VERSION 5.8 ;
BUSBITCHARS "[]" ;
DIVIDERCHAR "/" ;
UNITS
    DATABASE MICRONS 1000 ;
END UNITS

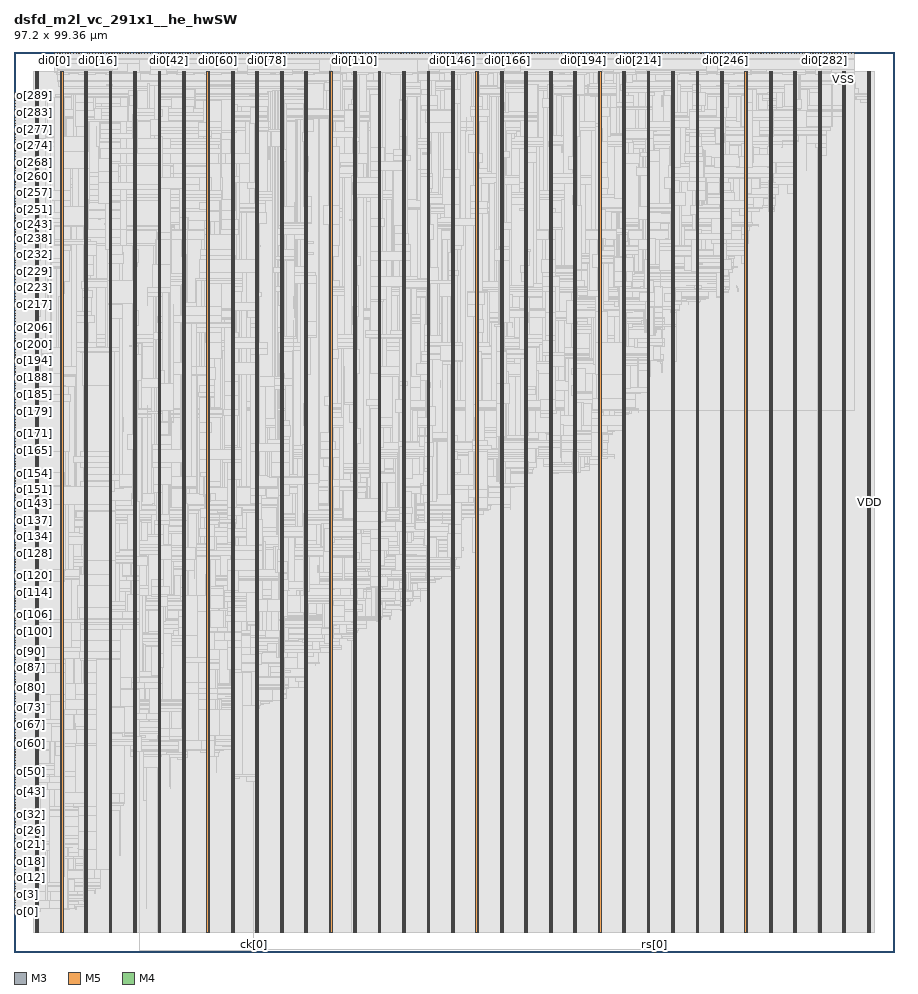
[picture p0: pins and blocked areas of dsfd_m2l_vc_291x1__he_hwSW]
MACRO dsfd_m2l_vc_291x1__he_hwSW
  FOREIGN dsfd_m2l_vc_291x1__he_hwSW 0 0 ;
  CLASS BLOCK ;
  SIZE 97.2 BY 99.36 ;
  PIN ck[0]
    DIRECTION INPUT ;
    USE SIGNAL ;
    PORT
      LAYER M3 ;
        RECT  26.46 0 26.478 0.144 ;
    END
    PORT
      LAYER M3 ;
        RECT  26.46 0.108 26.478 0.221 ;
    END
  END ck[0]
  PIN di0[0]
    DIRECTION INPUT ;
    USE SIGNAL ;
    PORT
      LAYER M3 ;
        RECT  4.464 99.216 4.482 99.36 ;
    END
  END di0[0]
  PIN di0[100]
    DIRECTION INPUT ;
    USE SIGNAL ;
    PORT
      LAYER M3 ;
        RECT  34.596 99.216 34.614 99.36 ;
    END
  END di0[100]
  PIN di0[101]
    DIRECTION INPUT ;
    USE SIGNAL ;
    PORT
      LAYER M5 ;
        RECT  34.896 99.168 34.92 99.36 ;
    END
  END di0[101]
  PIN di0[102]
    DIRECTION INPUT ;
    USE SIGNAL ;
    PORT
      LAYER M3 ;
        RECT  35.172 99.216 35.19 99.36 ;
    END
  END di0[102]
  PIN di0[103]
    DIRECTION INPUT ;
    USE SIGNAL ;
    PORT
      LAYER M5 ;
        RECT  35.472 99.168 35.496 99.36 ;
    END
  END di0[103]
  PIN di0[104]
    DIRECTION INPUT ;
    USE SIGNAL ;
    PORT
      LAYER M3 ;
        RECT  35.784 99.216 35.802 99.36 ;
    END
  END di0[104]
  PIN di0[105]
    DIRECTION INPUT ;
    USE SIGNAL ;
    PORT
      LAYER M5 ;
        RECT  36.096 99.168 36.12 99.36 ;
    END
  END di0[105]
  PIN di0[106]
    DIRECTION INPUT ;
    USE SIGNAL ;
    PORT
      LAYER M3 ;
        RECT  36.396 99.216 36.414 99.36 ;
    END
  END di0[106]
  PIN di0[107]
    DIRECTION INPUT ;
    USE SIGNAL ;
    PORT
      LAYER M5 ;
        RECT  36.672 99.168 36.696 99.36 ;
    END
  END di0[107]
  PIN di0[108]
    DIRECTION INPUT ;
    USE SIGNAL ;
    PORT
      LAYER M3 ;
        RECT  37.008 99.216 37.026 99.36 ;
    END
  END di0[108]
  PIN di0[109]
    DIRECTION INPUT ;
    USE SIGNAL ;
    PORT
      LAYER M5 ;
        RECT  37.296 99.168 37.32 99.36 ;
    END
  END di0[109]
  PIN di0[10]
    DIRECTION INPUT ;
    USE SIGNAL ;
    PORT
      LAYER M3 ;
        RECT  7.488 99.216 7.506 99.36 ;
    END
  END di0[10]
  PIN di0[110]
    DIRECTION INPUT ;
    USE SIGNAL ;
    PORT
      LAYER M3 ;
        RECT  37.584 99.216 37.602 99.36 ;
    END
  END di0[110]
  PIN di0[111]
    DIRECTION INPUT ;
    USE SIGNAL ;
    PORT
      LAYER M5 ;
        RECT  37.872 99.168 37.896 99.36 ;
    END
  END di0[111]
  PIN di0[112]
    DIRECTION INPUT ;
    USE SIGNAL ;
    PORT
      LAYER M3 ;
        RECT  38.196 99.216 38.214 99.36 ;
    END
  END di0[112]
  PIN di0[113]
    DIRECTION INPUT ;
    USE SIGNAL ;
    PORT
      LAYER M5 ;
        RECT  38.496 99.168 38.52 99.36 ;
    END
  END di0[113]
  PIN di0[114]
    DIRECTION INPUT ;
    USE SIGNAL ;
    PORT
      LAYER M3 ;
        RECT  38.808 99.216 38.826 99.36 ;
    END
  END di0[114]
  PIN di0[115]
    DIRECTION INPUT ;
    USE SIGNAL ;
    PORT
      LAYER M5 ;
        RECT  39.12 99.168 39.144 99.36 ;
    END
  END di0[115]
  PIN di0[116]
    DIRECTION INPUT ;
    USE SIGNAL ;
    PORT
      LAYER M3 ;
        RECT  39.42 99.216 39.438 99.36 ;
    END
  END di0[116]
  PIN di0[117]
    DIRECTION INPUT ;
    USE SIGNAL ;
    PORT
      LAYER M5 ;
        RECT  39.696 99.168 39.72 99.36 ;
    END
  END di0[117]
  PIN di0[118]
    DIRECTION INPUT ;
    USE SIGNAL ;
    PORT
      LAYER M3 ;
        RECT  39.996 99.216 40.014 99.36 ;
    END
  END di0[118]
  PIN di0[119]
    DIRECTION INPUT ;
    USE SIGNAL ;
    PORT
      LAYER M5 ;
        RECT  40.32 99.168 40.344 99.36 ;
    END
  END di0[119]
  PIN di0[11]
    DIRECTION INPUT ;
    USE SIGNAL ;
    PORT
      LAYER M5 ;
        RECT  7.776 99.168 7.8 99.36 ;
    END
  END di0[11]
  PIN di0[120]
    DIRECTION INPUT ;
    USE SIGNAL ;
    PORT
      LAYER M3 ;
        RECT  40.608 99.216 40.626 99.36 ;
    END
  END di0[120]
  PIN di0[121]
    DIRECTION INPUT ;
    USE SIGNAL ;
    PORT
      LAYER M5 ;
        RECT  40.896 99.168 40.92 99.36 ;
    END
  END di0[121]
  PIN di0[122]
    DIRECTION INPUT ;
    USE SIGNAL ;
    PORT
      LAYER M3 ;
        RECT  41.22 99.216 41.238 99.36 ;
    END
  END di0[122]
  PIN di0[123]
    DIRECTION INPUT ;
    USE SIGNAL ;
    PORT
      LAYER M5 ;
        RECT  41.52 99.168 41.544 99.36 ;
    END
  END di0[123]
  PIN di0[124]
    DIRECTION INPUT ;
    USE SIGNAL ;
    PORT
      LAYER M3 ;
        RECT  41.796 99.216 41.814 99.36 ;
    END
  END di0[124]
  PIN di0[125]
    DIRECTION INPUT ;
    USE SIGNAL ;
    PORT
      LAYER M5 ;
        RECT  42.096 99.168 42.12 99.36 ;
    END
  END di0[125]
  PIN di0[126]
    DIRECTION INPUT ;
    USE SIGNAL ;
    PORT
      LAYER M3 ;
        RECT  42.408 99.216 42.426 99.36 ;
    END
  END di0[126]
  PIN di0[127]
    DIRECTION INPUT ;
    USE SIGNAL ;
    PORT
      LAYER M5 ;
        RECT  42.72 99.168 42.744 99.36 ;
    END
  END di0[127]
  PIN di0[128]
    DIRECTION INPUT ;
    USE SIGNAL ;
    PORT
      LAYER M3 ;
        RECT  43.02 99.216 43.038 99.36 ;
    END
  END di0[128]
  PIN di0[129]
    DIRECTION INPUT ;
    USE SIGNAL ;
    PORT
      LAYER M5 ;
        RECT  43.296 99.168 43.32 99.36 ;
    END
  END di0[129]
  PIN di0[12]
    DIRECTION INPUT ;
    USE SIGNAL ;
    PORT
      LAYER M3 ;
        RECT  8.064 99.216 8.082 99.36 ;
    END
  END di0[12]
  PIN di0[130]
    DIRECTION INPUT ;
    USE SIGNAL ;
    PORT
      LAYER M3 ;
        RECT  43.632 99.216 43.65 99.36 ;
    END
  END di0[130]
  PIN di0[131]
    DIRECTION INPUT ;
    USE SIGNAL ;
    PORT
      LAYER M5 ;
        RECT  43.92 99.168 43.944 99.36 ;
    END
  END di0[131]
  PIN di0[132]
    DIRECTION INPUT ;
    USE SIGNAL ;
    PORT
      LAYER M3 ;
        RECT  44.208 99.216 44.226 99.36 ;
    END
  END di0[132]
  PIN di0[133]
    DIRECTION INPUT ;
    USE SIGNAL ;
    PORT
      LAYER M5 ;
        RECT  44.544 99.168 44.568 99.36 ;
    END
  END di0[133]
  PIN di0[134]
    DIRECTION INPUT ;
    USE SIGNAL ;
    PORT
      LAYER M3 ;
        RECT  44.82 99.216 44.838 99.36 ;
    END
  END di0[134]
  PIN di0[135]
    DIRECTION INPUT ;
    USE SIGNAL ;
    PORT
      LAYER M5 ;
        RECT  45.12 99.168 45.144 99.36 ;
    END
  END di0[135]
  PIN di0[136]
    DIRECTION INPUT ;
    USE SIGNAL ;
    PORT
      LAYER M3 ;
        RECT  45.432 99.216 45.45 99.36 ;
    END
  END di0[136]
  PIN di0[137]
    DIRECTION INPUT ;
    USE SIGNAL ;
    PORT
      LAYER M5 ;
        RECT  45.744 99.168 45.768 99.36 ;
    END
  END di0[137]
  PIN di0[138]
    DIRECTION INPUT ;
    USE SIGNAL ;
    PORT
      LAYER M3 ;
        RECT  46.044 99.216 46.062 99.36 ;
    END
  END di0[138]
  PIN di0[139]
    DIRECTION INPUT ;
    USE SIGNAL ;
    PORT
      LAYER M5 ;
        RECT  46.32 99.168 46.344 99.36 ;
    END
  END di0[139]
  PIN di0[13]
    DIRECTION INPUT ;
    USE SIGNAL ;
    PORT
      LAYER M5 ;
        RECT  8.352 99.168 8.376 99.36 ;
    END
  END di0[13]
  PIN di0[140]
    DIRECTION INPUT ;
    USE SIGNAL ;
    PORT
      LAYER M3 ;
        RECT  46.62 99.216 46.638 99.36 ;
    END
  END di0[140]
  PIN di0[141]
    DIRECTION INPUT ;
    USE SIGNAL ;
    PORT
      LAYER M5 ;
        RECT  46.944 99.168 46.968 99.36 ;
    END
  END di0[141]
  PIN di0[142]
    DIRECTION INPUT ;
    USE SIGNAL ;
    PORT
      LAYER M3 ;
        RECT  47.232 99.216 47.25 99.36 ;
    END
  END di0[142]
  PIN di0[143]
    DIRECTION INPUT ;
    USE SIGNAL ;
    PORT
      LAYER M5 ;
        RECT  47.52 99.168 47.544 99.36 ;
    END
  END di0[143]
  PIN di0[144]
    DIRECTION INPUT ;
    USE SIGNAL ;
    PORT
      LAYER M3 ;
        RECT  47.844 99.216 47.862 99.36 ;
    END
  END di0[144]
  PIN di0[145]
    DIRECTION INPUT ;
    USE SIGNAL ;
    PORT
      LAYER M5 ;
        RECT  48.144 99.168 48.168 99.36 ;
    END
  END di0[145]
  PIN di0[146]
    DIRECTION INPUT ;
    USE SIGNAL ;
    PORT
      LAYER M3 ;
        RECT  48.456 99.216 48.474 99.36 ;
    END
  END di0[146]
  PIN di0[147]
    DIRECTION INPUT ;
    USE SIGNAL ;
    PORT
      LAYER M5 ;
        RECT  48.72 99.168 48.744 99.36 ;
    END
  END di0[147]
  PIN di0[148]
    DIRECTION INPUT ;
    USE SIGNAL ;
    PORT
      LAYER M3 ;
        RECT  49.032 99.216 49.05 99.36 ;
    END
  END di0[148]
  PIN di0[149]
    DIRECTION INPUT ;
    USE SIGNAL ;
    PORT
      LAYER M5 ;
        RECT  49.344 99.168 49.368 99.36 ;
    END
  END di0[149]
  PIN di0[14]
    DIRECTION INPUT ;
    USE SIGNAL ;
    PORT
      LAYER M3 ;
        RECT  8.676 99.216 8.694 99.36 ;
    END
  END di0[14]
  PIN di0[150]
    DIRECTION INPUT ;
    USE SIGNAL ;
    PORT
      LAYER M3 ;
        RECT  49.644 99.216 49.662 99.36 ;
    END
  END di0[150]
  PIN di0[151]
    DIRECTION INPUT ;
    USE SIGNAL ;
    PORT
      LAYER M5 ;
        RECT  49.92 99.168 49.944 99.36 ;
    END
  END di0[151]
  PIN di0[152]
    DIRECTION INPUT ;
    USE SIGNAL ;
    PORT
      LAYER M3 ;
        RECT  50.256 99.216 50.274 99.36 ;
    END
  END di0[152]
  PIN di0[153]
    DIRECTION INPUT ;
    USE SIGNAL ;
    PORT
      LAYER M5 ;
        RECT  50.544 99.168 50.568 99.36 ;
    END
  END di0[153]
  PIN di0[154]
    DIRECTION INPUT ;
    USE SIGNAL ;
    PORT
      LAYER M3 ;
        RECT  50.868 99.216 50.886 99.36 ;
    END
  END di0[154]
  PIN di0[155]
    DIRECTION INPUT ;
    USE SIGNAL ;
    PORT
      LAYER M5 ;
        RECT  51.168 99.168 51.192 99.36 ;
    END
  END di0[155]
  PIN di0[156]
    DIRECTION INPUT ;
    USE SIGNAL ;
    PORT
      LAYER M3 ;
        RECT  51.444 99.216 51.462 99.36 ;
    END
  END di0[156]
  PIN di0[157]
    DIRECTION INPUT ;
    USE SIGNAL ;
    PORT
      LAYER M5 ;
        RECT  51.744 99.168 51.768 99.36 ;
    END
  END di0[157]
  PIN di0[158]
    DIRECTION INPUT ;
    USE SIGNAL ;
    PORT
      LAYER M3 ;
        RECT  52.056 99.216 52.074 99.36 ;
    END
  END di0[158]
  PIN di0[159]
    DIRECTION INPUT ;
    USE SIGNAL ;
    PORT
      LAYER M5 ;
        RECT  52.368 99.168 52.392 99.36 ;
    END
  END di0[159]
  PIN di0[15]
    DIRECTION INPUT ;
    USE SIGNAL ;
    PORT
      LAYER M5 ;
        RECT  8.976 99.168 9 99.36 ;
    END
  END di0[15]
  PIN di0[160]
    DIRECTION INPUT ;
    USE SIGNAL ;
    PORT
      LAYER M3 ;
        RECT  52.668 99.216 52.686 99.36 ;
    END
  END di0[160]
  PIN di0[161]
    DIRECTION INPUT ;
    USE SIGNAL ;
    PORT
      LAYER M5 ;
        RECT  52.944 99.168 52.968 99.36 ;
    END
  END di0[161]
  PIN di0[162]
    DIRECTION INPUT ;
    USE SIGNAL ;
    PORT
      LAYER M3 ;
        RECT  53.244 99.216 53.262 99.36 ;
    END
  END di0[162]
  PIN di0[163]
    DIRECTION INPUT ;
    USE SIGNAL ;
    PORT
      LAYER M5 ;
        RECT  53.568 99.168 53.592 99.36 ;
    END
  END di0[163]
  PIN di0[164]
    DIRECTION INPUT ;
    USE SIGNAL ;
    PORT
      LAYER M3 ;
        RECT  53.856 99.216 53.874 99.36 ;
    END
  END di0[164]
  PIN di0[165]
    DIRECTION INPUT ;
    USE SIGNAL ;
    PORT
      LAYER M5 ;
        RECT  54.144 99.168 54.168 99.36 ;
    END
  END di0[165]
  PIN di0[166]
    DIRECTION INPUT ;
    USE SIGNAL ;
    PORT
      LAYER M3 ;
        RECT  54.468 99.216 54.486 99.36 ;
    END
  END di0[166]
  PIN di0[167]
    DIRECTION INPUT ;
    USE SIGNAL ;
    PORT
      LAYER M5 ;
        RECT  54.768 99.168 54.792 99.36 ;
    END
  END di0[167]
  PIN di0[168]
    DIRECTION INPUT ;
    USE SIGNAL ;
    PORT
      LAYER M3 ;
        RECT  55.08 99.216 55.098 99.36 ;
    END
  END di0[168]
  PIN di0[169]
    DIRECTION INPUT ;
    USE SIGNAL ;
    PORT
      LAYER M5 ;
        RECT  55.344 99.168 55.368 99.36 ;
    END
  END di0[169]
  PIN di0[16]
    DIRECTION INPUT ;
    USE SIGNAL ;
    PORT
      LAYER M3 ;
        RECT  9.288 99.216 9.306 99.36 ;
    END
  END di0[16]
  PIN di0[170]
    DIRECTION INPUT ;
    USE SIGNAL ;
    PORT
      LAYER M3 ;
        RECT  55.656 99.216 55.674 99.36 ;
    END
  END di0[170]
  PIN di0[171]
    DIRECTION INPUT ;
    USE SIGNAL ;
    PORT
      LAYER M5 ;
        RECT  55.968 99.168 55.992 99.36 ;
    END
  END di0[171]
  PIN di0[172]
    DIRECTION INPUT ;
    USE SIGNAL ;
    PORT
      LAYER M3 ;
        RECT  56.268 99.216 56.286 99.36 ;
    END
  END di0[172]
  PIN di0[173]
    DIRECTION INPUT ;
    USE SIGNAL ;
    PORT
      LAYER M5 ;
        RECT  56.592 99.168 56.616 99.36 ;
    END
  END di0[173]
  PIN di0[174]
    DIRECTION INPUT ;
    USE SIGNAL ;
    PORT
      LAYER M3 ;
        RECT  56.88 99.216 56.898 99.36 ;
    END
  END di0[174]
  PIN di0[175]
    DIRECTION INPUT ;
    USE SIGNAL ;
    PORT
      LAYER M5 ;
        RECT  57.168 99.168 57.192 99.36 ;
    END
  END di0[175]
  PIN di0[176]
    DIRECTION INPUT ;
    USE SIGNAL ;
    PORT
      LAYER M3 ;
        RECT  57.492 99.216 57.51 99.36 ;
    END
  END di0[176]
  PIN di0[177]
    DIRECTION INPUT ;
    USE SIGNAL ;
    PORT
      LAYER M5 ;
        RECT  57.792 99.168 57.816 99.36 ;
    END
  END di0[177]
  PIN di0[178]
    DIRECTION INPUT ;
    USE SIGNAL ;
    PORT
      LAYER M3 ;
        RECT  58.068 99.216 58.086 99.36 ;
    END
  END di0[178]
  PIN di0[179]
    DIRECTION INPUT ;
    USE SIGNAL ;
    PORT
      LAYER M5 ;
        RECT  58.368 99.168 58.392 99.36 ;
    END
  END di0[179]
  PIN di0[17]
    DIRECTION INPUT ;
    USE SIGNAL ;
    PORT
      LAYER M5 ;
        RECT  9.6 99.168 9.624 99.36 ;
    END
  END di0[17]
  PIN di0[180]
    DIRECTION INPUT ;
    USE SIGNAL ;
    PORT
      LAYER M3 ;
        RECT  58.68 99.216 58.698 99.36 ;
    END
  END di0[180]
  PIN di0[181]
    DIRECTION INPUT ;
    USE SIGNAL ;
    PORT
      LAYER M5 ;
        RECT  58.992 99.168 59.016 99.36 ;
    END
  END di0[181]
  PIN di0[182]
    DIRECTION INPUT ;
    USE SIGNAL ;
    PORT
      LAYER M3 ;
        RECT  59.292 99.216 59.31 99.36 ;
    END
  END di0[182]
  PIN di0[183]
    DIRECTION INPUT ;
    USE SIGNAL ;
    PORT
      LAYER M5 ;
        RECT  59.568 99.168 59.592 99.36 ;
    END
  END di0[183]
  PIN di0[184]
    DIRECTION INPUT ;
    USE SIGNAL ;
    PORT
      LAYER M3 ;
        RECT  59.904 99.216 59.922 99.36 ;
    END
  END di0[184]
  PIN di0[185]
    DIRECTION INPUT ;
    USE SIGNAL ;
    PORT
      LAYER M5 ;
        RECT  60.192 99.168 60.216 99.36 ;
    END
  END di0[185]
  PIN di0[186]
    DIRECTION INPUT ;
    USE SIGNAL ;
    PORT
      LAYER M3 ;
        RECT  60.48 99.216 60.498 99.36 ;
    END
  END di0[186]
  PIN di0[187]
    DIRECTION INPUT ;
    USE SIGNAL ;
    PORT
      LAYER M5 ;
        RECT  60.768 99.168 60.792 99.36 ;
    END
  END di0[187]
  PIN di0[188]
    DIRECTION INPUT ;
    USE SIGNAL ;
    PORT
      LAYER M3 ;
        RECT  61.092 99.216 61.11 99.36 ;
    END
  END di0[188]
  PIN di0[189]
    DIRECTION INPUT ;
    USE SIGNAL ;
    PORT
      LAYER M5 ;
        RECT  61.392 99.168 61.416 99.36 ;
    END
  END di0[189]
  PIN di0[18]
    DIRECTION INPUT ;
    USE SIGNAL ;
    PORT
      LAYER M3 ;
        RECT  9.9 99.216 9.918 99.36 ;
    END
  END di0[18]
  PIN di0[190]
    DIRECTION INPUT ;
    USE SIGNAL ;
    PORT
      LAYER M3 ;
        RECT  61.704 99.216 61.722 99.36 ;
    END
  END di0[190]
  PIN di0[191]
    DIRECTION INPUT ;
    USE SIGNAL ;
    PORT
      LAYER M5 ;
        RECT  62.016 99.168 62.04 99.36 ;
    END
  END di0[191]
  PIN di0[192]
    DIRECTION INPUT ;
    USE SIGNAL ;
    PORT
      LAYER M3 ;
        RECT  62.28 99.216 62.298 99.36 ;
    END
  END di0[192]
  PIN di0[193]
    DIRECTION INPUT ;
    USE SIGNAL ;
    PORT
      LAYER M5 ;
        RECT  62.592 99.168 62.616 99.36 ;
    END
  END di0[193]
  PIN di0[194]
    DIRECTION INPUT ;
    USE SIGNAL ;
    PORT
      LAYER M3 ;
        RECT  62.892 99.216 62.91 99.36 ;
    END
  END di0[194]
  PIN di0[195]
    DIRECTION INPUT ;
    USE SIGNAL ;
    PORT
      LAYER M5 ;
        RECT  63.216 99.168 63.24 99.36 ;
    END
  END di0[195]
  PIN di0[196]
    DIRECTION INPUT ;
    USE SIGNAL ;
    PORT
      LAYER M3 ;
        RECT  63.504 99.216 63.522 99.36 ;
    END
  END di0[196]
  PIN di0[197]
    DIRECTION INPUT ;
    USE SIGNAL ;
    PORT
      LAYER M5 ;
        RECT  63.792 99.168 63.816 99.36 ;
    END
  END di0[197]
  PIN di0[198]
    DIRECTION INPUT ;
    USE SIGNAL ;
    PORT
      LAYER M3 ;
        RECT  64.116 99.216 64.134 99.36 ;
    END
  END di0[198]
  PIN di0[199]
    DIRECTION INPUT ;
    USE SIGNAL ;
    PORT
      LAYER M5 ;
        RECT  64.416 99.168 64.44 99.36 ;
    END
  END di0[199]
  PIN di0[19]
    DIRECTION INPUT ;
    USE SIGNAL ;
    PORT
      LAYER M5 ;
        RECT  10.176 99.168 10.2 99.36 ;
    END
  END di0[19]
  PIN di0[1]
    DIRECTION INPUT ;
    USE SIGNAL ;
    PORT
      LAYER M5 ;
        RECT  4.752 99.168 4.776 99.36 ;
    END
  END di0[1]
  PIN di0[200]
    DIRECTION INPUT ;
    USE SIGNAL ;
    PORT
      LAYER M3 ;
        RECT  64.692 99.216 64.71 99.36 ;
    END
  END di0[200]
  PIN di0[201]
    DIRECTION INPUT ;
    USE SIGNAL ;
    PORT
      LAYER M5 ;
        RECT  64.992 99.168 65.016 99.36 ;
    END
  END di0[201]
  PIN di0[202]
    DIRECTION INPUT ;
    USE SIGNAL ;
    PORT
      LAYER M3 ;
        RECT  65.304 99.216 65.322 99.36 ;
    END
  END di0[202]
  PIN di0[203]
    DIRECTION INPUT ;
    USE SIGNAL ;
    PORT
      LAYER M5 ;
        RECT  65.616 99.168 65.64 99.36 ;
    END
  END di0[203]
  PIN di0[204]
    DIRECTION INPUT ;
    USE SIGNAL ;
    PORT
      LAYER M3 ;
        RECT  65.916 99.216 65.934 99.36 ;
    END
  END di0[204]
  PIN di0[205]
    DIRECTION INPUT ;
    USE SIGNAL ;
    PORT
      LAYER M5 ;
        RECT  66.192 99.168 66.216 99.36 ;
    END
  END di0[205]
  PIN di0[206]
    DIRECTION INPUT ;
    USE SIGNAL ;
    PORT
      LAYER M3 ;
        RECT  66.528 99.216 66.546 99.36 ;
    END
  END di0[206]
  PIN di0[207]
    DIRECTION INPUT ;
    USE SIGNAL ;
    PORT
      LAYER M5 ;
        RECT  66.816 99.168 66.84 99.36 ;
    END
  END di0[207]
  PIN di0[208]
    DIRECTION INPUT ;
    USE SIGNAL ;
    PORT
      LAYER M3 ;
        RECT  67.104 99.216 67.122 99.36 ;
    END
  END di0[208]
  PIN di0[209]
    DIRECTION INPUT ;
    USE SIGNAL ;
    PORT
      LAYER M5 ;
        RECT  67.392 99.168 67.416 99.36 ;
    END
  END di0[209]
  PIN di0[20]
    DIRECTION INPUT ;
    USE SIGNAL ;
    PORT
      LAYER M3 ;
        RECT  10.476 99.216 10.494 99.36 ;
    END
  END di0[20]
  PIN di0[210]
    DIRECTION INPUT ;
    USE SIGNAL ;
    PORT
      LAYER M3 ;
        RECT  67.716 99.216 67.734 99.36 ;
    END
  END di0[210]
  PIN di0[211]
    DIRECTION INPUT ;
    USE SIGNAL ;
    PORT
      LAYER M5 ;
        RECT  68.016 99.168 68.04 99.36 ;
    END
  END di0[211]
  PIN di0[212]
    DIRECTION INPUT ;
    USE SIGNAL ;
    PORT
      LAYER M3 ;
        RECT  68.328 99.216 68.346 99.36 ;
    END
  END di0[212]
  PIN di0[213]
    DIRECTION INPUT ;
    USE SIGNAL ;
    PORT
      LAYER M5 ;
        RECT  68.64 99.168 68.664 99.36 ;
    END
  END di0[213]
  PIN di0[214]
    DIRECTION INPUT ;
    USE SIGNAL ;
    PORT
      LAYER M3 ;
        RECT  68.94 99.216 68.958 99.36 ;
    END
  END di0[214]
  PIN di0[215]
    DIRECTION INPUT ;
    USE SIGNAL ;
    PORT
      LAYER M5 ;
        RECT  69.216 99.168 69.24 99.36 ;
    END
  END di0[215]
  PIN di0[216]
    DIRECTION INPUT ;
    USE SIGNAL ;
    PORT
      LAYER M3 ;
        RECT  69.516 99.216 69.534 99.36 ;
    END
  END di0[216]
  PIN di0[217]
    DIRECTION INPUT ;
    USE SIGNAL ;
    PORT
      LAYER M5 ;
        RECT  69.84 99.168 69.864 99.36 ;
    END
  END di0[217]
  PIN di0[218]
    DIRECTION INPUT ;
    USE SIGNAL ;
    PORT
      LAYER M3 ;
        RECT  70.128 99.216 70.146 99.36 ;
    END
  END di0[218]
  PIN di0[219]
    DIRECTION INPUT ;
    USE SIGNAL ;
    PORT
      LAYER M5 ;
        RECT  70.416 99.168 70.44 99.36 ;
    END
  END di0[219]
  PIN di0[21]
    DIRECTION INPUT ;
    USE SIGNAL ;
    PORT
      LAYER M5 ;
        RECT  10.8 99.168 10.824 99.36 ;
    END
  END di0[21]
  PIN di0[220]
    DIRECTION INPUT ;
    USE SIGNAL ;
    PORT
      LAYER M3 ;
        RECT  70.74 99.216 70.758 99.36 ;
    END
  END di0[220]
  PIN di0[221]
    DIRECTION INPUT ;
    USE SIGNAL ;
    PORT
      LAYER M5 ;
        RECT  71.04 99.168 71.064 99.36 ;
    END
  END di0[221]
  PIN di0[222]
    DIRECTION INPUT ;
    USE SIGNAL ;
    PORT
      LAYER M3 ;
        RECT  71.316 99.216 71.334 99.36 ;
    END
  END di0[222]
  PIN di0[223]
    DIRECTION INPUT ;
    USE SIGNAL ;
    PORT
      LAYER M5 ;
        RECT  71.616 99.168 71.64 99.36 ;
    END
  END di0[223]
  PIN di0[224]
    DIRECTION INPUT ;
    USE SIGNAL ;
    PORT
      LAYER M3 ;
        RECT  71.928 99.216 71.946 99.36 ;
    END
  END di0[224]
  PIN di0[225]
    DIRECTION INPUT ;
    USE SIGNAL ;
    PORT
      LAYER M5 ;
        RECT  72.24 99.168 72.264 99.36 ;
    END
  END di0[225]
  PIN di0[226]
    DIRECTION INPUT ;
    USE SIGNAL ;
    PORT
      LAYER M3 ;
        RECT  72.54 99.216 72.558 99.36 ;
    END
  END di0[226]
  PIN di0[227]
    DIRECTION INPUT ;
    USE SIGNAL ;
    PORT
      LAYER M5 ;
        RECT  72.816 99.168 72.84 99.36 ;
    END
  END di0[227]
  PIN di0[228]
    DIRECTION INPUT ;
    USE SIGNAL ;
    PORT
      LAYER M3 ;
        RECT  73.152 99.216 73.17 99.36 ;
    END
  END di0[228]
  PIN di0[229]
    DIRECTION INPUT ;
    USE SIGNAL ;
    PORT
      LAYER M5 ;
        RECT  73.44 99.168 73.464 99.36 ;
    END
  END di0[229]
  PIN di0[22]
    DIRECTION INPUT ;
    USE SIGNAL ;
    PORT
      LAYER M3 ;
        RECT  11.088 99.216 11.106 99.36 ;
    END
  END di0[22]
  PIN di0[230]
    DIRECTION INPUT ;
    USE SIGNAL ;
    PORT
      LAYER M3 ;
        RECT  73.728 99.216 73.746 99.36 ;
    END
  END di0[230]
  PIN di0[231]
    DIRECTION INPUT ;
    USE SIGNAL ;
    PORT
      LAYER M5 ;
        RECT  74.064 99.168 74.088 99.36 ;
    END
  END di0[231]
  PIN di0[232]
    DIRECTION INPUT ;
    USE SIGNAL ;
    PORT
      LAYER M3 ;
        RECT  74.34 99.216 74.358 99.36 ;
    END
  END di0[232]
  PIN di0[233]
    DIRECTION INPUT ;
    USE SIGNAL ;
    PORT
      LAYER M5 ;
        RECT  74.64 99.168 74.664 99.36 ;
    END
  END di0[233]
  PIN di0[234]
    DIRECTION INPUT ;
    USE SIGNAL ;
    PORT
      LAYER M3 ;
        RECT  74.952 99.216 74.97 99.36 ;
    END
  END di0[234]
  PIN di0[235]
    DIRECTION INPUT ;
    USE SIGNAL ;
    PORT
      LAYER M5 ;
        RECT  75.264 99.168 75.288 99.36 ;
    END
  END di0[235]
  PIN di0[236]
    DIRECTION INPUT ;
    USE SIGNAL ;
    PORT
      LAYER M3 ;
        RECT  75.564 99.216 75.582 99.36 ;
    END
  END di0[236]
  PIN di0[237]
    DIRECTION INPUT ;
    USE SIGNAL ;
    PORT
      LAYER M5 ;
        RECT  75.84 99.168 75.864 99.36 ;
    END
  END di0[237]
  PIN di0[238]
    DIRECTION INPUT ;
    USE SIGNAL ;
    PORT
      LAYER M3 ;
        RECT  76.14 99.216 76.158 99.36 ;
    END
  END di0[238]
  PIN di0[239]
    DIRECTION INPUT ;
    USE SIGNAL ;
    PORT
      LAYER M5 ;
        RECT  76.464 99.168 76.488 99.36 ;
    END
  END di0[239]
  PIN di0[23]
    DIRECTION INPUT ;
    USE SIGNAL ;
    PORT
      LAYER M5 ;
        RECT  11.376 99.168 11.4 99.36 ;
    END
  END di0[23]
  PIN di0[240]
    DIRECTION INPUT ;
    USE SIGNAL ;
    PORT
      LAYER M3 ;
        RECT  76.752 99.216 76.77 99.36 ;
    END
  END di0[240]
  PIN di0[241]
    DIRECTION INPUT ;
    USE SIGNAL ;
    PORT
      LAYER M5 ;
        RECT  77.04 99.168 77.064 99.36 ;
    END
  END di0[241]
  PIN di0[242]
    DIRECTION INPUT ;
    USE SIGNAL ;
    PORT
      LAYER M3 ;
        RECT  77.364 99.216 77.382 99.36 ;
    END
  END di0[242]
  PIN di0[243]
    DIRECTION INPUT ;
    USE SIGNAL ;
    PORT
      LAYER M5 ;
        RECT  77.664 99.168 77.688 99.36 ;
    END
  END di0[243]
  PIN di0[244]
    DIRECTION INPUT ;
    USE SIGNAL ;
    PORT
      LAYER M3 ;
        RECT  77.976 99.216 77.994 99.36 ;
    END
  END di0[244]
  PIN di0[245]
    DIRECTION INPUT ;
    USE SIGNAL ;
    PORT
      LAYER M5 ;
        RECT  78.24 99.168 78.264 99.36 ;
    END
  END di0[245]
  PIN di0[246]
    DIRECTION INPUT ;
    USE SIGNAL ;
    PORT
      LAYER M3 ;
        RECT  78.552 99.216 78.57 99.36 ;
    END
  END di0[246]
  PIN di0[247]
    DIRECTION INPUT ;
    USE SIGNAL ;
    PORT
      LAYER M5 ;
        RECT  78.864 99.168 78.888 99.36 ;
    END
  END di0[247]
  PIN di0[248]
    DIRECTION INPUT ;
    USE SIGNAL ;
    PORT
      LAYER M3 ;
        RECT  79.164 99.216 79.182 99.36 ;
    END
  END di0[248]
  PIN di0[249]
    DIRECTION INPUT ;
    USE SIGNAL ;
    PORT
      LAYER M5 ;
        RECT  79.44 99.168 79.464 99.36 ;
    END
  END di0[249]
  PIN di0[24]
    DIRECTION INPUT ;
    USE SIGNAL ;
    PORT
      LAYER M3 ;
        RECT  11.7 99.216 11.718 99.36 ;
    END
  END di0[24]
  PIN di0[250]
    DIRECTION INPUT ;
    USE SIGNAL ;
    PORT
      LAYER M3 ;
        RECT  79.776 99.216 79.794 99.36 ;
    END
  END di0[250]
  PIN di0[251]
    DIRECTION INPUT ;
    USE SIGNAL ;
    PORT
      LAYER M5 ;
        RECT  80.064 99.168 80.088 99.36 ;
    END
  END di0[251]
  PIN di0[252]
    DIRECTION INPUT ;
    USE SIGNAL ;
    PORT
      LAYER M3 ;
        RECT  80.388 99.216 80.406 99.36 ;
    END
  END di0[252]
  PIN di0[253]
    DIRECTION INPUT ;
    USE SIGNAL ;
    PORT
      LAYER M5 ;
        RECT  80.688 99.168 80.712 99.36 ;
    END
  END di0[253]
  PIN di0[254]
    DIRECTION INPUT ;
    USE SIGNAL ;
    PORT
      LAYER M3 ;
        RECT  80.964 99.216 80.982 99.36 ;
    END
  END di0[254]
  PIN di0[255]
    DIRECTION INPUT ;
    USE SIGNAL ;
    PORT
      LAYER M5 ;
        RECT  81.264 99.168 81.288 99.36 ;
    END
  END di0[255]
  PIN di0[256]
    DIRECTION INPUT ;
    USE SIGNAL ;
    PORT
      LAYER M3 ;
        RECT  81.576 99.216 81.594 99.36 ;
    END
  END di0[256]
  PIN di0[257]
    DIRECTION INPUT ;
    USE SIGNAL ;
    PORT
      LAYER M5 ;
        RECT  81.888 99.168 81.912 99.36 ;
    END
  END di0[257]
  PIN di0[258]
    DIRECTION INPUT ;
    USE SIGNAL ;
    PORT
      LAYER M3 ;
        RECT  82.188 99.216 82.206 99.36 ;
    END
  END di0[258]
  PIN di0[259]
    DIRECTION INPUT ;
    USE SIGNAL ;
    PORT
      LAYER M5 ;
        RECT  82.464 99.168 82.488 99.36 ;
    END
  END di0[259]
  PIN di0[25]
    DIRECTION INPUT ;
    USE SIGNAL ;
    PORT
      LAYER M5 ;
        RECT  12 99.168 12.024 99.36 ;
    END
  END di0[25]
  PIN di0[260]
    DIRECTION INPUT ;
    USE SIGNAL ;
    PORT
      LAYER M3 ;
        RECT  82.764 99.216 82.782 99.36 ;
    END
  END di0[260]
  PIN di0[261]
    DIRECTION INPUT ;
    USE SIGNAL ;
    PORT
      LAYER M5 ;
        RECT  83.088 99.168 83.112 99.36 ;
    END
  END di0[261]
  PIN di0[262]
    DIRECTION INPUT ;
    USE SIGNAL ;
    PORT
      LAYER M3 ;
        RECT  83.376 99.216 83.394 99.36 ;
    END
  END di0[262]
  PIN di0[263]
    DIRECTION INPUT ;
    USE SIGNAL ;
    PORT
      LAYER M5 ;
        RECT  83.664 99.168 83.688 99.36 ;
    END
  END di0[263]
  PIN di0[264]
    DIRECTION INPUT ;
    USE SIGNAL ;
    PORT
      LAYER M3 ;
        RECT  83.988 99.216 84.006 99.36 ;
    END
  END di0[264]
  PIN di0[265]
    DIRECTION INPUT ;
    USE SIGNAL ;
    PORT
      LAYER M5 ;
        RECT  84.288 99.168 84.312 99.36 ;
    END
  END di0[265]
  PIN di0[266]
    DIRECTION INPUT ;
    USE SIGNAL ;
    PORT
      LAYER M3 ;
        RECT  84.6 99.216 84.618 99.36 ;
    END
  END di0[266]
  PIN di0[267]
    DIRECTION INPUT ;
    USE SIGNAL ;
    PORT
      LAYER M5 ;
        RECT  84.864 99.168 84.888 99.36 ;
    END
  END di0[267]
  PIN di0[268]
    DIRECTION INPUT ;
    USE SIGNAL ;
    PORT
      LAYER M3 ;
        RECT  85.176 99.216 85.194 99.36 ;
    END
  END di0[268]
  PIN di0[269]
    DIRECTION INPUT ;
    USE SIGNAL ;
    PORT
      LAYER M5 ;
        RECT  85.488 99.168 85.512 99.36 ;
    END
  END di0[269]
  PIN di0[26]
    DIRECTION INPUT ;
    USE SIGNAL ;
    PORT
      LAYER M3 ;
        RECT  12.276 99.216 12.294 99.36 ;
    END
  END di0[26]
  PIN di0[270]
    DIRECTION INPUT ;
    USE SIGNAL ;
    PORT
      LAYER M3 ;
        RECT  85.788 99.216 85.806 99.36 ;
    END
  END di0[270]
  PIN di0[271]
    DIRECTION INPUT ;
    USE SIGNAL ;
    PORT
      LAYER M5 ;
        RECT  86.112 99.168 86.136 99.36 ;
    END
  END di0[271]
  PIN di0[272]
    DIRECTION INPUT ;
    USE SIGNAL ;
    PORT
      LAYER M3 ;
        RECT  86.4 99.216 86.418 99.36 ;
    END
  END di0[272]
  PIN di0[273]
    DIRECTION INPUT ;
    USE SIGNAL ;
    PORT
      LAYER M5 ;
        RECT  86.688 99.168 86.712 99.36 ;
    END
  END di0[273]
  PIN di0[274]
    DIRECTION INPUT ;
    USE SIGNAL ;
    PORT
      LAYER M3 ;
        RECT  87.012 99.216 87.03 99.36 ;
    END
  END di0[274]
  PIN di0[275]
    DIRECTION INPUT ;
    USE SIGNAL ;
    PORT
      LAYER M5 ;
        RECT  87.312 99.168 87.336 99.36 ;
    END
  END di0[275]
  PIN di0[276]
    DIRECTION INPUT ;
    USE SIGNAL ;
    PORT
      LAYER M3 ;
        RECT  87.588 99.216 87.606 99.36 ;
    END
  END di0[276]
  PIN di0[277]
    DIRECTION INPUT ;
    USE SIGNAL ;
    PORT
      LAYER M5 ;
        RECT  87.888 99.168 87.912 99.36 ;
    END
  END di0[277]
  PIN di0[278]
    DIRECTION INPUT ;
    USE SIGNAL ;
    PORT
      LAYER M3 ;
        RECT  88.2 99.216 88.218 99.36 ;
    END
  END di0[278]
  PIN di0[279]
    DIRECTION INPUT ;
    USE SIGNAL ;
    PORT
      LAYER M5 ;
        RECT  88.512 99.168 88.536 99.36 ;
    END
  END di0[279]
  PIN di0[27]
    DIRECTION INPUT ;
    USE SIGNAL ;
    PORT
      LAYER M5 ;
        RECT  12.576 99.168 12.6 99.36 ;
    END
  END di0[27]
  PIN di0[280]
    DIRECTION INPUT ;
    USE SIGNAL ;
    PORT
      LAYER M3 ;
        RECT  88.812 99.216 88.83 99.36 ;
    END
  END di0[280]
  PIN di0[281]
    DIRECTION INPUT ;
    USE SIGNAL ;
    PORT
      LAYER M5 ;
        RECT  89.088 99.168 89.112 99.36 ;
    END
  END di0[281]
  PIN di0[282]
    DIRECTION INPUT ;
    USE SIGNAL ;
    PORT
      LAYER M3 ;
        RECT  89.424 99.216 89.442 99.36 ;
    END
  END di0[282]
  PIN di0[283]
    DIRECTION INPUT ;
    USE SIGNAL ;
    PORT
      LAYER M5 ;
        RECT  89.712 99.168 89.736 99.36 ;
    END
  END di0[283]
  PIN di0[284]
    DIRECTION INPUT ;
    USE SIGNAL ;
    PORT
      LAYER M3 ;
        RECT  90 99.216 90.018 99.36 ;
    END
  END di0[284]
  PIN di0[285]
    DIRECTION INPUT ;
    USE SIGNAL ;
    PORT
      LAYER M5 ;
        RECT  90.288 99.168 90.312 99.36 ;
    END
  END di0[285]
  PIN di0[286]
    DIRECTION INPUT ;
    USE SIGNAL ;
    PORT
      LAYER M3 ;
        RECT  90.612 99.216 90.63 99.36 ;
    END
  END di0[286]
  PIN di0[287]
    DIRECTION INPUT ;
    USE SIGNAL ;
    PORT
      LAYER M5 ;
        RECT  90.912 99.168 90.936 99.36 ;
    END
  END di0[287]
  PIN di0[288]
    DIRECTION INPUT ;
    USE SIGNAL ;
    PORT
      LAYER M3 ;
        RECT  91.224 99.216 91.242 99.36 ;
    END
  END di0[288]
  PIN di0[289]
    DIRECTION INPUT ;
    USE SIGNAL ;
    PORT
      LAYER M5 ;
        RECT  91.536 99.168 91.56 99.36 ;
    END
  END di0[289]
  PIN di0[28]
    DIRECTION INPUT ;
    USE SIGNAL ;
    PORT
      LAYER M3 ;
        RECT  12.888 99.216 12.906 99.36 ;
    END
  END di0[28]
  PIN di0[290]
    DIRECTION INPUT ;
    USE SIGNAL ;
    PORT
      LAYER M3 ;
        RECT  91.8 99.216 91.818 99.36 ;
    END
  END di0[290]
  PIN di0[291]
    DIRECTION INPUT ;
    USE SIGNAL ;
    PORT
      LAYER M5 ;
        RECT  92.112 99.168 92.136 99.36 ;
    END
  END di0[291]
  PIN di0[292]
    DIRECTION INPUT ;
    USE SIGNAL ;
    PORT
      LAYER M3 ;
        RECT  92.412 99.216 92.43 99.36 ;
    END
  END di0[292]
  PIN di0[29]
    DIRECTION INPUT ;
    USE SIGNAL ;
    PORT
      LAYER M5 ;
        RECT  13.2 99.168 13.224 99.36 ;
    END
  END di0[29]
  PIN di0[2]
    DIRECTION INPUT ;
    USE SIGNAL ;
    PORT
      LAYER M3 ;
        RECT  5.076 99.216 5.094 99.36 ;
    END
  END di0[2]
  PIN di0[30]
    DIRECTION INPUT ;
    USE SIGNAL ;
    PORT
      LAYER M3 ;
        RECT  13.5 99.216 13.518 99.36 ;
    END
  END di0[30]
  PIN di0[31]
    DIRECTION INPUT ;
    USE SIGNAL ;
    PORT
      LAYER M5 ;
        RECT  13.776 99.168 13.8 99.36 ;
    END
  END di0[31]
  PIN di0[32]
    DIRECTION INPUT ;
    USE SIGNAL ;
    PORT
      LAYER M3 ;
        RECT  14.112 99.216 14.13 99.36 ;
    END
  END di0[32]
  PIN di0[33]
    DIRECTION INPUT ;
    USE SIGNAL ;
    PORT
      LAYER M5 ;
        RECT  14.4 99.168 14.424 99.36 ;
    END
  END di0[33]
  PIN di0[34]
    DIRECTION INPUT ;
    USE SIGNAL ;
    PORT
      LAYER M3 ;
        RECT  14.688 99.216 14.706 99.36 ;
    END
  END di0[34]
  PIN di0[35]
    DIRECTION INPUT ;
    USE SIGNAL ;
    PORT
      LAYER M5 ;
        RECT  15.024 99.168 15.048 99.36 ;
    END
  END di0[35]
  PIN di0[36]
    DIRECTION INPUT ;
    USE SIGNAL ;
    PORT
      LAYER M3 ;
        RECT  15.3 99.216 15.318 99.36 ;
    END
  END di0[36]
  PIN di0[37]
    DIRECTION INPUT ;
    USE SIGNAL ;
    PORT
      LAYER M5 ;
        RECT  15.6 99.168 15.624 99.36 ;
    END
  END di0[37]
  PIN di0[38]
    DIRECTION INPUT ;
    USE SIGNAL ;
    PORT
      LAYER M3 ;
        RECT  15.912 99.216 15.93 99.36 ;
    END
  END di0[38]
  PIN di0[39]
    DIRECTION INPUT ;
    USE SIGNAL ;
    PORT
      LAYER M5 ;
        RECT  16.224 99.168 16.248 99.36 ;
    END
  END di0[39]
  PIN di0[3]
    DIRECTION INPUT ;
    USE SIGNAL ;
    PORT
      LAYER M5 ;
        RECT  5.376 99.168 5.4 99.36 ;
    END
  END di0[3]
  PIN di0[40]
    DIRECTION INPUT ;
    USE SIGNAL ;
    PORT
      LAYER M3 ;
        RECT  16.524 99.216 16.542 99.36 ;
    END
  END di0[40]
  PIN di0[41]
    DIRECTION INPUT ;
    USE SIGNAL ;
    PORT
      LAYER M5 ;
        RECT  16.8 99.168 16.824 99.36 ;
    END
  END di0[41]
  PIN di0[42]
    DIRECTION INPUT ;
    USE SIGNAL ;
    PORT
      LAYER M3 ;
        RECT  17.1 99.216 17.118 99.36 ;
    END
  END di0[42]
  PIN di0[43]
    DIRECTION INPUT ;
    USE SIGNAL ;
    PORT
      LAYER M5 ;
        RECT  17.424 99.168 17.448 99.36 ;
    END
  END di0[43]
  PIN di0[44]
    DIRECTION INPUT ;
    USE SIGNAL ;
    PORT
      LAYER M3 ;
        RECT  17.712 99.216 17.73 99.36 ;
    END
  END di0[44]
  PIN di0[45]
    DIRECTION INPUT ;
    USE SIGNAL ;
    PORT
      LAYER M5 ;
        RECT  18 99.168 18.024 99.36 ;
    END
  END di0[45]
  PIN di0[46]
    DIRECTION INPUT ;
    USE SIGNAL ;
    PORT
      LAYER M3 ;
        RECT  18.324 99.216 18.342 99.36 ;
    END
  END di0[46]
  PIN di0[47]
    DIRECTION INPUT ;
    USE SIGNAL ;
    PORT
      LAYER M5 ;
        RECT  18.624 99.168 18.648 99.36 ;
    END
  END di0[47]
  PIN di0[48]
    DIRECTION INPUT ;
    USE SIGNAL ;
    PORT
      LAYER M3 ;
        RECT  18.936 99.216 18.954 99.36 ;
    END
  END di0[48]
  PIN di0[49]
    DIRECTION INPUT ;
    USE SIGNAL ;
    PORT
      LAYER M5 ;
        RECT  19.2 99.168 19.224 99.36 ;
    END
  END di0[49]
  PIN di0[4]
    DIRECTION INPUT ;
    USE SIGNAL ;
    PORT
      LAYER M3 ;
        RECT  5.652 99.216 5.67 99.36 ;
    END
  END di0[4]
  PIN di0[50]
    DIRECTION INPUT ;
    USE SIGNAL ;
    PORT
      LAYER M3 ;
        RECT  19.512 99.216 19.53 99.36 ;
    END
  END di0[50]
  PIN di0[51]
    DIRECTION INPUT ;
    USE SIGNAL ;
    PORT
      LAYER M5 ;
        RECT  19.824 99.168 19.848 99.36 ;
    END
  END di0[51]
  PIN di0[52]
    DIRECTION INPUT ;
    USE SIGNAL ;
    PORT
      LAYER M3 ;
        RECT  20.124 99.216 20.142 99.36 ;
    END
  END di0[52]
  PIN di0[53]
    DIRECTION INPUT ;
    USE SIGNAL ;
    PORT
      LAYER M5 ;
        RECT  20.4 99.168 20.424 99.36 ;
    END
  END di0[53]
  PIN di0[54]
    DIRECTION INPUT ;
    USE SIGNAL ;
    PORT
      LAYER M3 ;
        RECT  20.736 99.216 20.754 99.36 ;
    END
  END di0[54]
  PIN di0[55]
    DIRECTION INPUT ;
    USE SIGNAL ;
    PORT
      LAYER M5 ;
        RECT  21.024 99.168 21.048 99.36 ;
    END
  END di0[55]
  PIN di0[56]
    DIRECTION INPUT ;
    USE SIGNAL ;
    PORT
      LAYER M3 ;
        RECT  21.348 99.216 21.366 99.36 ;
    END
  END di0[56]
  PIN di0[57]
    DIRECTION INPUT ;
    USE SIGNAL ;
    PORT
      LAYER M5 ;
        RECT  21.648 99.168 21.672 99.36 ;
    END
  END di0[57]
  PIN di0[58]
    DIRECTION INPUT ;
    USE SIGNAL ;
    PORT
      LAYER M3 ;
        RECT  21.924 99.216 21.942 99.36 ;
    END
  END di0[58]
  PIN di0[59]
    DIRECTION INPUT ;
    USE SIGNAL ;
    PORT
      LAYER M5 ;
        RECT  22.224 99.168 22.248 99.36 ;
    END
  END di0[59]
  PIN di0[5]
    DIRECTION INPUT ;
    USE SIGNAL ;
    PORT
      LAYER M5 ;
        RECT  5.952 99.168 5.976 99.36 ;
    END
  END di0[5]
  PIN di0[60]
    DIRECTION INPUT ;
    USE SIGNAL ;
    PORT
      LAYER M3 ;
        RECT  22.536 99.216 22.554 99.36 ;
    END
  END di0[60]
  PIN di0[61]
    DIRECTION INPUT ;
    USE SIGNAL ;
    PORT
      LAYER M5 ;
        RECT  22.848 99.168 22.872 99.36 ;
    END
  END di0[61]
  PIN di0[62]
    DIRECTION INPUT ;
    USE SIGNAL ;
    PORT
      LAYER M3 ;
        RECT  23.148 99.216 23.166 99.36 ;
    END
  END di0[62]
  PIN di0[63]
    DIRECTION INPUT ;
    USE SIGNAL ;
    PORT
      LAYER M5 ;
        RECT  23.424 99.168 23.448 99.36 ;
    END
  END di0[63]
  PIN di0[64]
    DIRECTION INPUT ;
    USE SIGNAL ;
    PORT
      LAYER M3 ;
        RECT  23.724 99.216 23.742 99.36 ;
    END
  END di0[64]
  PIN di0[65]
    DIRECTION INPUT ;
    USE SIGNAL ;
    PORT
      LAYER M5 ;
        RECT  24.048 99.168 24.072 99.36 ;
    END
  END di0[65]
  PIN di0[66]
    DIRECTION INPUT ;
    USE SIGNAL ;
    PORT
      LAYER M3 ;
        RECT  24.336 99.216 24.354 99.36 ;
    END
  END di0[66]
  PIN di0[67]
    DIRECTION INPUT ;
    USE SIGNAL ;
    PORT
      LAYER M5 ;
        RECT  24.624 99.168 24.648 99.36 ;
    END
  END di0[67]
  PIN di0[68]
    DIRECTION INPUT ;
    USE SIGNAL ;
    PORT
      LAYER M3 ;
        RECT  24.948 99.216 24.966 99.36 ;
    END
  END di0[68]
  PIN di0[69]
    DIRECTION INPUT ;
    USE SIGNAL ;
    PORT
      LAYER M5 ;
        RECT  25.248 99.168 25.272 99.36 ;
    END
  END di0[69]
  PIN di0[6]
    DIRECTION INPUT ;
    USE SIGNAL ;
    PORT
      LAYER M3 ;
        RECT  6.264 99.216 6.282 99.36 ;
    END
  END di0[6]
  PIN di0[70]
    DIRECTION INPUT ;
    USE SIGNAL ;
    PORT
      LAYER M3 ;
        RECT  25.56 99.216 25.578 99.36 ;
    END
  END di0[70]
  PIN di0[71]
    DIRECTION INPUT ;
    USE SIGNAL ;
    PORT
      LAYER M5 ;
        RECT  25.824 99.168 25.848 99.36 ;
    END
  END di0[71]
  PIN di0[72]
    DIRECTION INPUT ;
    USE SIGNAL ;
    PORT
      LAYER M3 ;
        RECT  26.136 99.216 26.154 99.36 ;
    END
  END di0[72]
  PIN di0[73]
    DIRECTION INPUT ;
    USE SIGNAL ;
    PORT
      LAYER M5 ;
        RECT  26.448 99.168 26.472 99.36 ;
    END
  END di0[73]
  PIN di0[74]
    DIRECTION INPUT ;
    USE SIGNAL ;
    PORT
      LAYER M3 ;
        RECT  26.748 99.216 26.766 99.36 ;
    END
  END di0[74]
  PIN di0[75]
    DIRECTION INPUT ;
    USE SIGNAL ;
    PORT
      LAYER M5 ;
        RECT  27.072 99.168 27.096 99.36 ;
    END
  END di0[75]
  PIN di0[76]
    DIRECTION INPUT ;
    USE SIGNAL ;
    PORT
      LAYER M3 ;
        RECT  27.36 99.216 27.378 99.36 ;
    END
  END di0[76]
  PIN di0[77]
    DIRECTION INPUT ;
    USE SIGNAL ;
    PORT
      LAYER M5 ;
        RECT  27.648 99.168 27.672 99.36 ;
    END
  END di0[77]
  PIN di0[78]
    DIRECTION INPUT ;
    USE SIGNAL ;
    PORT
      LAYER M3 ;
        RECT  27.972 99.216 27.99 99.36 ;
    END
  END di0[78]
  PIN di0[79]
    DIRECTION INPUT ;
    USE SIGNAL ;
    PORT
      LAYER M5 ;
        RECT  28.272 99.168 28.296 99.36 ;
    END
  END di0[79]
  PIN di0[7]
    DIRECTION INPUT ;
    USE SIGNAL ;
    PORT
      LAYER M5 ;
        RECT  6.576 99.168 6.6 99.36 ;
    END
  END di0[7]
  PIN di0[80]
    DIRECTION INPUT ;
    USE SIGNAL ;
    PORT
      LAYER M3 ;
        RECT  28.548 99.216 28.566 99.36 ;
    END
  END di0[80]
  PIN di0[81]
    DIRECTION INPUT ;
    USE SIGNAL ;
    PORT
      LAYER M5 ;
        RECT  28.848 99.168 28.872 99.36 ;
    END
  END di0[81]
  PIN di0[82]
    DIRECTION INPUT ;
    USE SIGNAL ;
    PORT
      LAYER M3 ;
        RECT  29.16 99.216 29.178 99.36 ;
    END
  END di0[82]
  PIN di0[83]
    DIRECTION INPUT ;
    USE SIGNAL ;
    PORT
      LAYER M5 ;
        RECT  29.472 99.168 29.496 99.36 ;
    END
  END di0[83]
  PIN di0[84]
    DIRECTION INPUT ;
    USE SIGNAL ;
    PORT
      LAYER M3 ;
        RECT  29.772 99.216 29.79 99.36 ;
    END
  END di0[84]
  PIN di0[85]
    DIRECTION INPUT ;
    USE SIGNAL ;
    PORT
      LAYER M5 ;
        RECT  30.048 99.168 30.072 99.36 ;
    END
  END di0[85]
  PIN di0[86]
    DIRECTION INPUT ;
    USE SIGNAL ;
    PORT
      LAYER M3 ;
        RECT  30.384 99.216 30.402 99.36 ;
    END
  END di0[86]
  PIN di0[87]
    DIRECTION INPUT ;
    USE SIGNAL ;
    PORT
      LAYER M5 ;
        RECT  30.672 99.168 30.696 99.36 ;
    END
  END di0[87]
  PIN di0[88]
    DIRECTION INPUT ;
    USE SIGNAL ;
    PORT
      LAYER M3 ;
        RECT  30.96 99.216 30.978 99.36 ;
    END
  END di0[88]
  PIN di0[89]
    DIRECTION INPUT ;
    USE SIGNAL ;
    PORT
      LAYER M5 ;
        RECT  31.248 99.168 31.272 99.36 ;
    END
  END di0[89]
  PIN di0[8]
    DIRECTION INPUT ;
    USE SIGNAL ;
    PORT
      LAYER M3 ;
        RECT  6.876 99.216 6.894 99.36 ;
    END
  END di0[8]
  PIN di0[90]
    DIRECTION INPUT ;
    USE SIGNAL ;
    PORT
      LAYER M3 ;
        RECT  31.572 99.216 31.59 99.36 ;
    END
  END di0[90]
  PIN di0[91]
    DIRECTION INPUT ;
    USE SIGNAL ;
    PORT
      LAYER M5 ;
        RECT  31.872 99.168 31.896 99.36 ;
    END
  END di0[91]
  PIN di0[92]
    DIRECTION INPUT ;
    USE SIGNAL ;
    PORT
      LAYER M3 ;
        RECT  32.184 99.216 32.202 99.36 ;
    END
  END di0[92]
  PIN di0[93]
    DIRECTION INPUT ;
    USE SIGNAL ;
    PORT
      LAYER M5 ;
        RECT  32.496 99.168 32.52 99.36 ;
    END
  END di0[93]
  PIN di0[94]
    DIRECTION INPUT ;
    USE SIGNAL ;
    PORT
      LAYER M3 ;
        RECT  32.76 99.216 32.778 99.36 ;
    END
  END di0[94]
  PIN di0[95]
    DIRECTION INPUT ;
    USE SIGNAL ;
    PORT
      LAYER M5 ;
        RECT  33.072 99.168 33.096 99.36 ;
    END
  END di0[95]
  PIN di0[96]
    DIRECTION INPUT ;
    USE SIGNAL ;
    PORT
      LAYER M3 ;
        RECT  33.372 99.216 33.39 99.36 ;
    END
  END di0[96]
  PIN di0[97]
    DIRECTION INPUT ;
    USE SIGNAL ;
    PORT
      LAYER M5 ;
        RECT  33.696 99.168 33.72 99.36 ;
    END
  END di0[97]
  PIN di0[98]
    DIRECTION INPUT ;
    USE SIGNAL ;
    PORT
      LAYER M3 ;
        RECT  33.984 99.216 34.002 99.36 ;
    END
  END di0[98]
  PIN di0[99]
    DIRECTION INPUT ;
    USE SIGNAL ;
    PORT
      LAYER M5 ;
        RECT  34.272 99.168 34.296 99.36 ;
    END
  END di0[99]
  PIN di0[9]
    DIRECTION INPUT ;
    USE SIGNAL ;
    PORT
      LAYER M5 ;
        RECT  7.152 99.168 7.176 99.36 ;
    END
  END di0[9]
  PIN fi0[0]
    DIRECTION INPUT ;
    USE SIGNAL ;
    PORT
      LAYER M5 ;
        RECT  92.736 99.168 92.76 99.36 ;
    END
  END fi0[0]
  PIN o[0]
    DIRECTION OUTPUT ;
    USE SIGNAL ;
    PORT
      LAYER M4 ;
        RECT  0 4.464 0.192 4.488 ;
    END
  END o[0]
  PIN o[100]
    DIRECTION OUTPUT ;
    USE SIGNAL ;
    PORT
      LAYER M4 ;
        RECT  0 35.328 0.192 35.352 ;
    END
  END o[100]
  PIN o[101]
    DIRECTION OUTPUT ;
    USE SIGNAL ;
    PORT
      LAYER M4 ;
        RECT  0 35.664 0.192 35.688 ;
    END
  END o[101]
  PIN o[102]
    DIRECTION OUTPUT ;
    USE SIGNAL ;
    PORT
      LAYER M4 ;
        RECT  0 35.952 0.192 35.976 ;
    END
  END o[102]
  PIN o[103]
    DIRECTION OUTPUT ;
    USE SIGNAL ;
    PORT
      LAYER M4 ;
        RECT  0 36.288 0.192 36.312 ;
    END
  END o[103]
  PIN o[104]
    DIRECTION OUTPUT ;
    USE SIGNAL ;
    PORT
      LAYER M4 ;
        RECT  0 36.576 0.192 36.6 ;
    END
  END o[104]
  PIN o[105]
    DIRECTION OUTPUT ;
    USE SIGNAL ;
    PORT
      LAYER M4 ;
        RECT  0 36.864 0.192 36.888 ;
    END
  END o[105]
  PIN o[106]
    DIRECTION OUTPUT ;
    USE SIGNAL ;
    PORT
      LAYER M4 ;
        RECT  0 37.2 0.192 37.224 ;
    END
  END o[106]
  PIN o[107]
    DIRECTION OUTPUT ;
    USE SIGNAL ;
    PORT
      LAYER M4 ;
        RECT  0 37.488 0.192 37.512 ;
    END
  END o[107]
  PIN o[108]
    DIRECTION OUTPUT ;
    USE SIGNAL ;
    PORT
      LAYER M4 ;
        RECT  0 37.824 0.192 37.848 ;
    END
  END o[108]
  PIN o[109]
    DIRECTION OUTPUT ;
    USE SIGNAL ;
    PORT
      LAYER M4 ;
        RECT  0 38.112 0.192 38.136 ;
    END
  END o[109]
  PIN o[10]
    DIRECTION OUTPUT ;
    USE SIGNAL ;
    PORT
      LAYER M4 ;
        RECT  0 7.584 0.192 7.608 ;
    END
  END o[10]
  PIN o[110]
    DIRECTION OUTPUT ;
    USE SIGNAL ;
    PORT
      LAYER M4 ;
        RECT  0 38.448 0.192 38.472 ;
    END
  END o[110]
  PIN o[111]
    DIRECTION OUTPUT ;
    USE SIGNAL ;
    PORT
      LAYER M4 ;
        RECT  0 38.736 0.192 38.76 ;
    END
  END o[111]
  PIN o[112]
    DIRECTION OUTPUT ;
    USE SIGNAL ;
    PORT
      LAYER M4 ;
        RECT  0 39.024 0.192 39.048 ;
    END
  END o[112]
  PIN o[113]
    DIRECTION OUTPUT ;
    USE SIGNAL ;
    PORT
      LAYER M4 ;
        RECT  0 39.36 0.192 39.384 ;
    END
  END o[113]
  PIN o[114]
    DIRECTION OUTPUT ;
    USE SIGNAL ;
    PORT
      LAYER M4 ;
        RECT  0 39.648 0.192 39.672 ;
    END
  END o[114]
  PIN o[115]
    DIRECTION OUTPUT ;
    USE SIGNAL ;
    PORT
      LAYER M4 ;
        RECT  0 39.984 0.192 40.008 ;
    END
  END o[115]
  PIN o[116]
    DIRECTION OUTPUT ;
    USE SIGNAL ;
    PORT
      LAYER M4 ;
        RECT  0 40.272 0.192 40.296 ;
    END
  END o[116]
  PIN o[117]
    DIRECTION OUTPUT ;
    USE SIGNAL ;
    PORT
      LAYER M4 ;
        RECT  0 40.608 0.192 40.632 ;
    END
  END o[117]
  PIN o[118]
    DIRECTION OUTPUT ;
    USE SIGNAL ;
    PORT
      LAYER M4 ;
        RECT  0 40.896 0.192 40.92 ;
    END
  END o[118]
  PIN o[119]
    DIRECTION OUTPUT ;
    USE SIGNAL ;
    PORT
      LAYER M4 ;
        RECT  0 41.184 0.192 41.208 ;
    END
  END o[119]
  PIN o[11]
    DIRECTION OUTPUT ;
    USE SIGNAL ;
    PORT
      LAYER M4 ;
        RECT  0 7.872 0.192 7.896 ;
    END
  END o[11]
  PIN o[120]
    DIRECTION OUTPUT ;
    USE SIGNAL ;
    PORT
      LAYER M4 ;
        RECT  0 41.52 0.192 41.544 ;
    END
  END o[120]
  PIN o[121]
    DIRECTION OUTPUT ;
    USE SIGNAL ;
    PORT
      LAYER M4 ;
        RECT  0 41.808 0.192 41.832 ;
    END
  END o[121]
  PIN o[122]
    DIRECTION OUTPUT ;
    USE SIGNAL ;
    PORT
      LAYER M4 ;
        RECT  0 42.144 0.192 42.168 ;
    END
  END o[122]
  PIN o[123]
    DIRECTION OUTPUT ;
    USE SIGNAL ;
    PORT
      LAYER M4 ;
        RECT  0 42.432 0.192 42.456 ;
    END
  END o[123]
  PIN o[124]
    DIRECTION OUTPUT ;
    USE SIGNAL ;
    PORT
      LAYER M4 ;
        RECT  0 42.768 0.192 42.792 ;
    END
  END o[124]
  PIN o[125]
    DIRECTION OUTPUT ;
    USE SIGNAL ;
    PORT
      LAYER M4 ;
        RECT  0 43.056 0.192 43.08 ;
    END
  END o[125]
  PIN o[126]
    DIRECTION OUTPUT ;
    USE SIGNAL ;
    PORT
      LAYER M4 ;
        RECT  0 43.344 0.192 43.368 ;
    END
  END o[126]
  PIN o[127]
    DIRECTION OUTPUT ;
    USE SIGNAL ;
    PORT
      LAYER M4 ;
        RECT  0 43.68 0.192 43.704 ;
    END
  END o[127]
  PIN o[128]
    DIRECTION OUTPUT ;
    USE SIGNAL ;
    PORT
      LAYER M4 ;
        RECT  0 43.968 0.192 43.992 ;
    END
  END o[128]
  PIN o[129]
    DIRECTION OUTPUT ;
    USE SIGNAL ;
    PORT
      LAYER M4 ;
        RECT  0 44.304 0.192 44.328 ;
    END
  END o[129]
  PIN o[12]
    DIRECTION OUTPUT ;
    USE SIGNAL ;
    PORT
      LAYER M4 ;
        RECT  0 8.208 0.192 8.232 ;
    END
  END o[12]
  PIN o[130]
    DIRECTION OUTPUT ;
    USE SIGNAL ;
    PORT
      LAYER M4 ;
        RECT  0 44.592 0.192 44.616 ;
    END
  END o[130]
  PIN o[131]
    DIRECTION OUTPUT ;
    USE SIGNAL ;
    PORT
      LAYER M4 ;
        RECT  0 44.928 0.192 44.952 ;
    END
  END o[131]
  PIN o[132]
    DIRECTION OUTPUT ;
    USE SIGNAL ;
    PORT
      LAYER M4 ;
        RECT  0 45.216 0.192 45.24 ;
    END
  END o[132]
  PIN o[133]
    DIRECTION OUTPUT ;
    USE SIGNAL ;
    PORT
      LAYER M4 ;
        RECT  0 45.504 0.192 45.528 ;
    END
  END o[133]
  PIN o[134]
    DIRECTION OUTPUT ;
    USE SIGNAL ;
    PORT
      LAYER M4 ;
        RECT  0 45.84 0.192 45.864 ;
    END
  END o[134]
  PIN o[135]
    DIRECTION OUTPUT ;
    USE SIGNAL ;
    PORT
      LAYER M4 ;
        RECT  0 46.128 0.192 46.152 ;
    END
  END o[135]
  PIN o[136]
    DIRECTION OUTPUT ;
    USE SIGNAL ;
    PORT
      LAYER M4 ;
        RECT  0 46.464 0.192 46.488 ;
    END
  END o[136]
  PIN o[137]
    DIRECTION OUTPUT ;
    USE SIGNAL ;
    PORT
      LAYER M4 ;
        RECT  0 46.752 0.192 46.776 ;
    END
  END o[137]
  PIN o[138]
    DIRECTION OUTPUT ;
    USE SIGNAL ;
    PORT
      LAYER M4 ;
        RECT  0 47.088 0.192 47.112 ;
    END
  END o[138]
  PIN o[139]
    DIRECTION OUTPUT ;
    USE SIGNAL ;
    PORT
      LAYER M4 ;
        RECT  0 47.376 0.192 47.4 ;
    END
  END o[139]
  PIN o[13]
    DIRECTION OUTPUT ;
    USE SIGNAL ;
    PORT
      LAYER M4 ;
        RECT  0 8.496 0.192 8.52 ;
    END
  END o[13]
  PIN o[140]
    DIRECTION OUTPUT ;
    USE SIGNAL ;
    PORT
      LAYER M4 ;
        RECT  0 47.664 0.192 47.688 ;
    END
  END o[140]
  PIN o[141]
    DIRECTION OUTPUT ;
    USE SIGNAL ;
    PORT
      LAYER M4 ;
        RECT  0 48 0.192 48.024 ;
    END
  END o[141]
  PIN o[142]
    DIRECTION OUTPUT ;
    USE SIGNAL ;
    PORT
      LAYER M4 ;
        RECT  0 48.288 0.192 48.312 ;
    END
  END o[142]
  PIN o[143]
    DIRECTION OUTPUT ;
    USE SIGNAL ;
    PORT
      LAYER M4 ;
        RECT  0 48.624 0.192 48.648 ;
    END
  END o[143]
  PIN o[144]
    DIRECTION OUTPUT ;
    USE SIGNAL ;
    PORT
      LAYER M4 ;
        RECT  0 48.912 0.192 48.936 ;
    END
  END o[144]
  PIN o[145]
    DIRECTION OUTPUT ;
    USE SIGNAL ;
    PORT
      LAYER M4 ;
        RECT  0 49.248 0.192 49.272 ;
    END
  END o[145]
  PIN o[146]
    DIRECTION OUTPUT ;
    USE SIGNAL ;
    PORT
      LAYER M4 ;
        RECT  0 49.536 0.192 49.56 ;
    END
  END o[146]
  PIN o[147]
    DIRECTION OUTPUT ;
    USE SIGNAL ;
    PORT
      LAYER M4 ;
        RECT  0 49.824 0.192 49.848 ;
    END
  END o[147]
  PIN o[148]
    DIRECTION OUTPUT ;
    USE SIGNAL ;
    PORT
      LAYER M4 ;
        RECT  0 50.16 0.192 50.184 ;
    END
  END o[148]
  PIN o[149]
    DIRECTION OUTPUT ;
    USE SIGNAL ;
    PORT
      LAYER M4 ;
        RECT  0 50.448 0.192 50.472 ;
    END
  END o[149]
  PIN o[14]
    DIRECTION OUTPUT ;
    USE SIGNAL ;
    PORT
      LAYER M4 ;
        RECT  0 8.784 0.192 8.808 ;
    END
  END o[14]
  PIN o[150]
    DIRECTION OUTPUT ;
    USE SIGNAL ;
    PORT
      LAYER M4 ;
        RECT  0 50.784 0.192 50.808 ;
    END
  END o[150]
  PIN o[151]
    DIRECTION OUTPUT ;
    USE SIGNAL ;
    PORT
      LAYER M4 ;
        RECT  0 51.072 0.192 51.096 ;
    END
  END o[151]
  PIN o[152]
    DIRECTION OUTPUT ;
    USE SIGNAL ;
    PORT
      LAYER M4 ;
        RECT  0 51.408 0.192 51.432 ;
    END
  END o[152]
  PIN o[153]
    DIRECTION OUTPUT ;
    USE SIGNAL ;
    PORT
      LAYER M4 ;
        RECT  0 51.696 0.192 51.72 ;
    END
  END o[153]
  PIN o[154]
    DIRECTION OUTPUT ;
    USE SIGNAL ;
    PORT
      LAYER M4 ;
        RECT  0 51.984 0.192 52.008 ;
    END
  END o[154]
  PIN o[155]
    DIRECTION OUTPUT ;
    USE SIGNAL ;
    PORT
      LAYER M4 ;
        RECT  0 52.32 0.192 52.344 ;
    END
  END o[155]
  PIN o[156]
    DIRECTION OUTPUT ;
    USE SIGNAL ;
    PORT
      LAYER M4 ;
        RECT  0 52.608 0.192 52.632 ;
    END
  END o[156]
  PIN o[157]
    DIRECTION OUTPUT ;
    USE SIGNAL ;
    PORT
      LAYER M4 ;
        RECT  0 52.944 0.192 52.968 ;
    END
  END o[157]
  PIN o[158]
    DIRECTION OUTPUT ;
    USE SIGNAL ;
    PORT
      LAYER M4 ;
        RECT  0 53.232 0.192 53.256 ;
    END
  END o[158]
  PIN o[159]
    DIRECTION OUTPUT ;
    USE SIGNAL ;
    PORT
      LAYER M4 ;
        RECT  0 53.568 0.192 53.592 ;
    END
  END o[159]
  PIN o[15]
    DIRECTION OUTPUT ;
    USE SIGNAL ;
    PORT
      LAYER M4 ;
        RECT  0 9.12 0.192 9.144 ;
    END
  END o[15]
  PIN o[160]
    DIRECTION OUTPUT ;
    USE SIGNAL ;
    PORT
      LAYER M4 ;
        RECT  0 53.856 0.192 53.88 ;
    END
  END o[160]
  PIN o[161]
    DIRECTION OUTPUT ;
    USE SIGNAL ;
    PORT
      LAYER M4 ;
        RECT  0 54.144 0.192 54.168 ;
    END
  END o[161]
  PIN o[162]
    DIRECTION OUTPUT ;
    USE SIGNAL ;
    PORT
      LAYER M4 ;
        RECT  0 54.48 0.192 54.504 ;
    END
  END o[162]
  PIN o[163]
    DIRECTION OUTPUT ;
    USE SIGNAL ;
    PORT
      LAYER M4 ;
        RECT  0 54.768 0.192 54.792 ;
    END
  END o[163]
  PIN o[164]
    DIRECTION OUTPUT ;
    USE SIGNAL ;
    PORT
      LAYER M4 ;
        RECT  0 55.104 0.192 55.128 ;
    END
  END o[164]
  PIN o[165]
    DIRECTION OUTPUT ;
    USE SIGNAL ;
    PORT
      LAYER M4 ;
        RECT  0 55.392 0.192 55.416 ;
    END
  END o[165]
  PIN o[166]
    DIRECTION OUTPUT ;
    USE SIGNAL ;
    PORT
      LAYER M4 ;
        RECT  0 55.728 0.192 55.752 ;
    END
  END o[166]
  PIN o[167]
    DIRECTION OUTPUT ;
    USE SIGNAL ;
    PORT
      LAYER M4 ;
        RECT  0 56.016 0.192 56.04 ;
    END
  END o[167]
  PIN o[168]
    DIRECTION OUTPUT ;
    USE SIGNAL ;
    PORT
      LAYER M4 ;
        RECT  0 56.304 0.192 56.328 ;
    END
  END o[168]
  PIN o[169]
    DIRECTION OUTPUT ;
    USE SIGNAL ;
    PORT
      LAYER M4 ;
        RECT  0 56.64 0.192 56.664 ;
    END
  END o[169]
  PIN o[16]
    DIRECTION OUTPUT ;
    USE SIGNAL ;
    PORT
      LAYER M4 ;
        RECT  0 9.408 0.192 9.432 ;
    END
  END o[16]
  PIN o[170]
    DIRECTION OUTPUT ;
    USE SIGNAL ;
    PORT
      LAYER M4 ;
        RECT  0 56.928 0.192 56.952 ;
    END
  END o[170]
  PIN o[171]
    DIRECTION OUTPUT ;
    USE SIGNAL ;
    PORT
      LAYER M4 ;
        RECT  0 57.264 0.192 57.288 ;
    END
  END o[171]
  PIN o[172]
    DIRECTION OUTPUT ;
    USE SIGNAL ;
    PORT
      LAYER M4 ;
        RECT  0 57.552 0.192 57.576 ;
    END
  END o[172]
  PIN o[173]
    DIRECTION OUTPUT ;
    USE SIGNAL ;
    PORT
      LAYER M4 ;
        RECT  0 57.888 0.192 57.912 ;
    END
  END o[173]
  PIN o[174]
    DIRECTION OUTPUT ;
    USE SIGNAL ;
    PORT
      LAYER M4 ;
        RECT  0 58.176 0.192 58.2 ;
    END
  END o[174]
  PIN o[175]
    DIRECTION OUTPUT ;
    USE SIGNAL ;
    PORT
      LAYER M4 ;
        RECT  0 58.464 0.192 58.488 ;
    END
  END o[175]
  PIN o[176]
    DIRECTION OUTPUT ;
    USE SIGNAL ;
    PORT
      LAYER M4 ;
        RECT  0 58.8 0.192 58.824 ;
    END
  END o[176]
  PIN o[177]
    DIRECTION OUTPUT ;
    USE SIGNAL ;
    PORT
      LAYER M4 ;
        RECT  0 59.088 0.192 59.112 ;
    END
  END o[177]
  PIN o[178]
    DIRECTION OUTPUT ;
    USE SIGNAL ;
    PORT
      LAYER M4 ;
        RECT  0 59.424 0.192 59.448 ;
    END
  END o[178]
  PIN o[179]
    DIRECTION OUTPUT ;
    USE SIGNAL ;
    PORT
      LAYER M4 ;
        RECT  0 59.712 0.192 59.736 ;
    END
  END o[179]
  PIN o[17]
    DIRECTION OUTPUT ;
    USE SIGNAL ;
    PORT
      LAYER M4 ;
        RECT  0 9.744 0.192 9.768 ;
    END
  END o[17]
  PIN o[180]
    DIRECTION OUTPUT ;
    USE SIGNAL ;
    PORT
      LAYER M4 ;
        RECT  0 60.048 0.192 60.072 ;
    END
  END o[180]
  PIN o[181]
    DIRECTION OUTPUT ;
    USE SIGNAL ;
    PORT
      LAYER M4 ;
        RECT  0 60.336 0.192 60.36 ;
    END
  END o[181]
  PIN o[182]
    DIRECTION OUTPUT ;
    USE SIGNAL ;
    PORT
      LAYER M4 ;
        RECT  0 60.624 0.192 60.648 ;
    END
  END o[182]
  PIN o[183]
    DIRECTION OUTPUT ;
    USE SIGNAL ;
    PORT
      LAYER M4 ;
        RECT  0 60.96 0.192 60.984 ;
    END
  END o[183]
  PIN o[184]
    DIRECTION OUTPUT ;
    USE SIGNAL ;
    PORT
      LAYER M4 ;
        RECT  0 61.248 0.192 61.272 ;
    END
  END o[184]
  PIN o[185]
    DIRECTION OUTPUT ;
    USE SIGNAL ;
    PORT
      LAYER M4 ;
        RECT  0 61.584 0.192 61.608 ;
    END
  END o[185]
  PIN o[186]
    DIRECTION OUTPUT ;
    USE SIGNAL ;
    PORT
      LAYER M4 ;
        RECT  0 61.872 0.192 61.896 ;
    END
  END o[186]
  PIN o[187]
    DIRECTION OUTPUT ;
    USE SIGNAL ;
    PORT
      LAYER M4 ;
        RECT  0 62.208 0.192 62.232 ;
    END
  END o[187]
  PIN o[188]
    DIRECTION OUTPUT ;
    USE SIGNAL ;
    PORT
      LAYER M4 ;
        RECT  0 62.496 0.192 62.52 ;
    END
  END o[188]
  PIN o[189]
    DIRECTION OUTPUT ;
    USE SIGNAL ;
    PORT
      LAYER M4 ;
        RECT  0 62.784 0.192 62.808 ;
    END
  END o[189]
  PIN o[18]
    DIRECTION OUTPUT ;
    USE SIGNAL ;
    PORT
      LAYER M4 ;
        RECT  0 10.032 0.192 10.056 ;
    END
  END o[18]
  PIN o[190]
    DIRECTION OUTPUT ;
    USE SIGNAL ;
    PORT
      LAYER M4 ;
        RECT  0 63.12 0.192 63.144 ;
    END
  END o[190]
  PIN o[191]
    DIRECTION OUTPUT ;
    USE SIGNAL ;
    PORT
      LAYER M4 ;
        RECT  0 63.408 0.192 63.432 ;
    END
  END o[191]
  PIN o[192]
    DIRECTION OUTPUT ;
    USE SIGNAL ;
    PORT
      LAYER M4 ;
        RECT  0 63.744 0.192 63.768 ;
    END
  END o[192]
  PIN o[193]
    DIRECTION OUTPUT ;
    USE SIGNAL ;
    PORT
      LAYER M4 ;
        RECT  0 64.032 0.192 64.056 ;
    END
  END o[193]
  PIN o[194]
    DIRECTION OUTPUT ;
    USE SIGNAL ;
    PORT
      LAYER M4 ;
        RECT  0 64.368 0.192 64.392 ;
    END
  END o[194]
  PIN o[195]
    DIRECTION OUTPUT ;
    USE SIGNAL ;
    PORT
      LAYER M4 ;
        RECT  0 64.656 0.192 64.68 ;
    END
  END o[195]
  PIN o[196]
    DIRECTION OUTPUT ;
    USE SIGNAL ;
    PORT
      LAYER M4 ;
        RECT  0 64.944 0.192 64.968 ;
    END
  END o[196]
  PIN o[197]
    DIRECTION OUTPUT ;
    USE SIGNAL ;
    PORT
      LAYER M4 ;
        RECT  0 65.28 0.192 65.304 ;
    END
  END o[197]
  PIN o[198]
    DIRECTION OUTPUT ;
    USE SIGNAL ;
    PORT
      LAYER M4 ;
        RECT  0 65.568 0.192 65.592 ;
    END
  END o[198]
  PIN o[199]
    DIRECTION OUTPUT ;
    USE SIGNAL ;
    PORT
      LAYER M4 ;
        RECT  0 65.904 0.192 65.928 ;
    END
  END o[199]
  PIN o[19]
    DIRECTION OUTPUT ;
    USE SIGNAL ;
    PORT
      LAYER M4 ;
        RECT  0 10.368 0.192 10.392 ;
    END
  END o[19]
  PIN o[1]
    DIRECTION OUTPUT ;
    USE SIGNAL ;
    PORT
      LAYER M4 ;
        RECT  0 4.8 0.192 4.824 ;
    END
  END o[1]
  PIN o[200]
    DIRECTION OUTPUT ;
    USE SIGNAL ;
    PORT
      LAYER M4 ;
        RECT  0 66.192 0.192 66.216 ;
    END
  END o[200]
  PIN o[201]
    DIRECTION OUTPUT ;
    USE SIGNAL ;
    PORT
      LAYER M4 ;
        RECT  0 66.528 0.192 66.552 ;
    END
  END o[201]
  PIN o[202]
    DIRECTION OUTPUT ;
    USE SIGNAL ;
    PORT
      LAYER M4 ;
        RECT  0 66.816 0.192 66.84 ;
    END
  END o[202]
  PIN o[203]
    DIRECTION OUTPUT ;
    USE SIGNAL ;
    PORT
      LAYER M4 ;
        RECT  0 67.104 0.192 67.128 ;
    END
  END o[203]
  PIN o[204]
    DIRECTION OUTPUT ;
    USE SIGNAL ;
    PORT
      LAYER M4 ;
        RECT  0 67.44 0.192 67.464 ;
    END
  END o[204]
  PIN o[205]
    DIRECTION OUTPUT ;
    USE SIGNAL ;
    PORT
      LAYER M4 ;
        RECT  0 67.728 0.192 67.752 ;
    END
  END o[205]
  PIN o[206]
    DIRECTION OUTPUT ;
    USE SIGNAL ;
    PORT
      LAYER M4 ;
        RECT  0 68.064 0.192 68.088 ;
    END
  END o[206]
  PIN o[207]
    DIRECTION OUTPUT ;
    USE SIGNAL ;
    PORT
      LAYER M4 ;
        RECT  0 68.352 0.192 68.376 ;
    END
  END o[207]
  PIN o[208]
    DIRECTION OUTPUT ;
    USE SIGNAL ;
    PORT
      LAYER M4 ;
        RECT  0 68.688 0.192 68.712 ;
    END
  END o[208]
  PIN o[209]
    DIRECTION OUTPUT ;
    USE SIGNAL ;
    PORT
      LAYER M4 ;
        RECT  0 68.976 0.192 69 ;
    END
  END o[209]
  PIN o[20]
    DIRECTION OUTPUT ;
    USE SIGNAL ;
    PORT
      LAYER M4 ;
        RECT  0 10.656 0.192 10.68 ;
    END
  END o[20]
  PIN o[210]
    DIRECTION OUTPUT ;
    USE SIGNAL ;
    PORT
      LAYER M4 ;
        RECT  0 69.264 0.192 69.288 ;
    END
  END o[210]
  PIN o[211]
    DIRECTION OUTPUT ;
    USE SIGNAL ;
    PORT
      LAYER M4 ;
        RECT  0 69.6 0.192 69.624 ;
    END
  END o[211]
  PIN o[212]
    DIRECTION OUTPUT ;
    USE SIGNAL ;
    PORT
      LAYER M4 ;
        RECT  0 69.888 0.192 69.912 ;
    END
  END o[212]
  PIN o[213]
    DIRECTION OUTPUT ;
    USE SIGNAL ;
    PORT
      LAYER M4 ;
        RECT  0 70.224 0.192 70.248 ;
    END
  END o[213]
  PIN o[214]
    DIRECTION OUTPUT ;
    USE SIGNAL ;
    PORT
      LAYER M4 ;
        RECT  0 70.512 0.192 70.536 ;
    END
  END o[214]
  PIN o[215]
    DIRECTION OUTPUT ;
    USE SIGNAL ;
    PORT
      LAYER M4 ;
        RECT  0 70.848 0.192 70.872 ;
    END
  END o[215]
  PIN o[216]
    DIRECTION OUTPUT ;
    USE SIGNAL ;
    PORT
      LAYER M4 ;
        RECT  0 71.136 0.192 71.16 ;
    END
  END o[216]
  PIN o[217]
    DIRECTION OUTPUT ;
    USE SIGNAL ;
    PORT
      LAYER M4 ;
        RECT  0 71.424 0.192 71.448 ;
    END
  END o[217]
  PIN o[218]
    DIRECTION OUTPUT ;
    USE SIGNAL ;
    PORT
      LAYER M4 ;
        RECT  0 71.76 0.192 71.784 ;
    END
  END o[218]
  PIN o[219]
    DIRECTION OUTPUT ;
    USE SIGNAL ;
    PORT
      LAYER M4 ;
        RECT  0 72.048 0.192 72.072 ;
    END
  END o[219]
  PIN o[21]
    DIRECTION OUTPUT ;
    USE SIGNAL ;
    PORT
      LAYER M4 ;
        RECT  0 10.944 0.192 10.968 ;
    END
  END o[21]
  PIN o[220]
    DIRECTION OUTPUT ;
    USE SIGNAL ;
    PORT
      LAYER M4 ;
        RECT  0 72.384 0.192 72.408 ;
    END
  END o[220]
  PIN o[221]
    DIRECTION OUTPUT ;
    USE SIGNAL ;
    PORT
      LAYER M4 ;
        RECT  0 72.672 0.192 72.696 ;
    END
  END o[221]
  PIN o[222]
    DIRECTION OUTPUT ;
    USE SIGNAL ;
    PORT
      LAYER M4 ;
        RECT  0 73.008 0.192 73.032 ;
    END
  END o[222]
  PIN o[223]
    DIRECTION OUTPUT ;
    USE SIGNAL ;
    PORT
      LAYER M4 ;
        RECT  0 73.296 0.192 73.32 ;
    END
  END o[223]
  PIN o[224]
    DIRECTION OUTPUT ;
    USE SIGNAL ;
    PORT
      LAYER M4 ;
        RECT  0 73.584 0.192 73.608 ;
    END
  END o[224]
  PIN o[225]
    DIRECTION OUTPUT ;
    USE SIGNAL ;
    PORT
      LAYER M4 ;
        RECT  0 73.92 0.192 73.944 ;
    END
  END o[225]
  PIN o[226]
    DIRECTION OUTPUT ;
    USE SIGNAL ;
    PORT
      LAYER M4 ;
        RECT  0 74.208 0.192 74.232 ;
    END
  END o[226]
  PIN o[227]
    DIRECTION OUTPUT ;
    USE SIGNAL ;
    PORT
      LAYER M4 ;
        RECT  0 74.544 0.192 74.568 ;
    END
  END o[227]
  PIN o[228]
    DIRECTION OUTPUT ;
    USE SIGNAL ;
    PORT
      LAYER M4 ;
        RECT  0 74.832 0.192 74.856 ;
    END
  END o[228]
  PIN o[229]
    DIRECTION OUTPUT ;
    USE SIGNAL ;
    PORT
      LAYER M4 ;
        RECT  0 75.168 0.192 75.192 ;
    END
  END o[229]
  PIN o[22]
    DIRECTION OUTPUT ;
    USE SIGNAL ;
    PORT
      LAYER M4 ;
        RECT  0 11.28 0.192 11.304 ;
    END
  END o[22]
  PIN o[230]
    DIRECTION OUTPUT ;
    USE SIGNAL ;
    PORT
      LAYER M4 ;
        RECT  0 75.456 0.192 75.48 ;
    END
  END o[230]
  PIN o[231]
    DIRECTION OUTPUT ;
    USE SIGNAL ;
    PORT
      LAYER M4 ;
        RECT  0 75.744 0.192 75.768 ;
    END
  END o[231]
  PIN o[232]
    DIRECTION OUTPUT ;
    USE SIGNAL ;
    PORT
      LAYER M4 ;
        RECT  0 76.08 0.192 76.104 ;
    END
  END o[232]
  PIN o[233]
    DIRECTION OUTPUT ;
    USE SIGNAL ;
    PORT
      LAYER M4 ;
        RECT  0 76.368 0.192 76.392 ;
    END
  END o[233]
  PIN o[234]
    DIRECTION OUTPUT ;
    USE SIGNAL ;
    PORT
      LAYER M4 ;
        RECT  0 76.704 0.192 76.728 ;
    END
  END o[234]
  PIN o[235]
    DIRECTION OUTPUT ;
    USE SIGNAL ;
    PORT
      LAYER M4 ;
        RECT  0 76.992 0.192 77.016 ;
    END
  END o[235]
  PIN o[236]
    DIRECTION OUTPUT ;
    USE SIGNAL ;
    PORT
      LAYER M4 ;
        RECT  0 77.328 0.192 77.352 ;
    END
  END o[236]
  PIN o[237]
    DIRECTION OUTPUT ;
    USE SIGNAL ;
    PORT
      LAYER M4 ;
        RECT  0 77.616 0.192 77.64 ;
    END
  END o[237]
  PIN o[238]
    DIRECTION OUTPUT ;
    USE SIGNAL ;
    PORT
      LAYER M4 ;
        RECT  0 77.904 0.192 77.928 ;
    END
  END o[238]
  PIN o[239]
    DIRECTION OUTPUT ;
    USE SIGNAL ;
    PORT
      LAYER M4 ;
        RECT  0 78.24 0.192 78.264 ;
    END
  END o[239]
  PIN o[23]
    DIRECTION OUTPUT ;
    USE SIGNAL ;
    PORT
      LAYER M4 ;
        RECT  0 11.568 0.192 11.592 ;
    END
  END o[23]
  PIN o[240]
    DIRECTION OUTPUT ;
    USE SIGNAL ;
    PORT
      LAYER M4 ;
        RECT  0 78.528 0.192 78.552 ;
    END
  END o[240]
  PIN o[241]
    DIRECTION OUTPUT ;
    USE SIGNAL ;
    PORT
      LAYER M4 ;
        RECT  0 78.864 0.192 78.888 ;
    END
  END o[241]
  PIN o[242]
    DIRECTION OUTPUT ;
    USE SIGNAL ;
    PORT
      LAYER M4 ;
        RECT  0 79.152 0.192 79.176 ;
    END
  END o[242]
  PIN o[243]
    DIRECTION OUTPUT ;
    USE SIGNAL ;
    PORT
      LAYER M4 ;
        RECT  0 79.488 0.192 79.512 ;
    END
  END o[243]
  PIN o[244]
    DIRECTION OUTPUT ;
    USE SIGNAL ;
    PORT
      LAYER M4 ;
        RECT  0 79.776 0.192 79.8 ;
    END
  END o[244]
  PIN o[245]
    DIRECTION OUTPUT ;
    USE SIGNAL ;
    PORT
      LAYER M4 ;
        RECT  0 80.064 0.192 80.088 ;
    END
  END o[245]
  PIN o[246]
    DIRECTION OUTPUT ;
    USE SIGNAL ;
    PORT
      LAYER M4 ;
        RECT  0 80.4 0.192 80.424 ;
    END
  END o[246]
  PIN o[247]
    DIRECTION OUTPUT ;
    USE SIGNAL ;
    PORT
      LAYER M4 ;
        RECT  0 80.688 0.192 80.712 ;
    END
  END o[247]
  PIN o[248]
    DIRECTION OUTPUT ;
    USE SIGNAL ;
    PORT
      LAYER M4 ;
        RECT  0 81.024 0.192 81.048 ;
    END
  END o[248]
  PIN o[249]
    DIRECTION OUTPUT ;
    USE SIGNAL ;
    PORT
      LAYER M4 ;
        RECT  0 81.312 0.192 81.336 ;
    END
  END o[249]
  PIN o[24]
    DIRECTION OUTPUT ;
    USE SIGNAL ;
    PORT
      LAYER M4 ;
        RECT  0 11.904 0.192 11.928 ;
    END
  END o[24]
  PIN o[250]
    DIRECTION OUTPUT ;
    USE SIGNAL ;
    PORT
      LAYER M4 ;
        RECT  0 81.648 0.192 81.672 ;
    END
  END o[250]
  PIN o[251]
    DIRECTION OUTPUT ;
    USE SIGNAL ;
    PORT
      LAYER M4 ;
        RECT  0 81.936 0.192 81.96 ;
    END
  END o[251]
  PIN o[252]
    DIRECTION OUTPUT ;
    USE SIGNAL ;
    PORT
      LAYER M4 ;
        RECT  0 82.224 0.192 82.248 ;
    END
  END o[252]
  PIN o[253]
    DIRECTION OUTPUT ;
    USE SIGNAL ;
    PORT
      LAYER M4 ;
        RECT  0 82.56 0.192 82.584 ;
    END
  END o[253]
  PIN o[254]
    DIRECTION OUTPUT ;
    USE SIGNAL ;
    PORT
      LAYER M4 ;
        RECT  0 82.848 0.192 82.872 ;
    END
  END o[254]
  PIN o[255]
    DIRECTION OUTPUT ;
    USE SIGNAL ;
    PORT
      LAYER M4 ;
        RECT  0 83.184 0.192 83.208 ;
    END
  END o[255]
  PIN o[256]
    DIRECTION OUTPUT ;
    USE SIGNAL ;
    PORT
      LAYER M4 ;
        RECT  0 83.472 0.192 83.496 ;
    END
  END o[256]
  PIN o[257]
    DIRECTION OUTPUT ;
    USE SIGNAL ;
    PORT
      LAYER M4 ;
        RECT  0 83.808 0.192 83.832 ;
    END
  END o[257]
  PIN o[258]
    DIRECTION OUTPUT ;
    USE SIGNAL ;
    PORT
      LAYER M4 ;
        RECT  0 84.096 0.192 84.12 ;
    END
  END o[258]
  PIN o[259]
    DIRECTION OUTPUT ;
    USE SIGNAL ;
    PORT
      LAYER M4 ;
        RECT  0 84.384 0.192 84.408 ;
    END
  END o[259]
  PIN o[25]
    DIRECTION OUTPUT ;
    USE SIGNAL ;
    PORT
      LAYER M4 ;
        RECT  0 12.192 0.192 12.216 ;
    END
  END o[25]
  PIN o[260]
    DIRECTION OUTPUT ;
    USE SIGNAL ;
    PORT
      LAYER M4 ;
        RECT  0 84.72 0.192 84.744 ;
    END
  END o[260]
  PIN o[261]
    DIRECTION OUTPUT ;
    USE SIGNAL ;
    PORT
      LAYER M4 ;
        RECT  0 85.008 0.192 85.032 ;
    END
  END o[261]
  PIN o[262]
    DIRECTION OUTPUT ;
    USE SIGNAL ;
    PORT
      LAYER M4 ;
        RECT  0 85.344 0.192 85.368 ;
    END
  END o[262]
  PIN o[263]
    DIRECTION OUTPUT ;
    USE SIGNAL ;
    PORT
      LAYER M4 ;
        RECT  0 85.632 0.192 85.656 ;
    END
  END o[263]
  PIN o[264]
    DIRECTION OUTPUT ;
    USE SIGNAL ;
    PORT
      LAYER M4 ;
        RECT  0 85.968 0.192 85.992 ;
    END
  END o[264]
  PIN o[265]
    DIRECTION OUTPUT ;
    USE SIGNAL ;
    PORT
      LAYER M4 ;
        RECT  0 86.256 0.192 86.28 ;
    END
  END o[265]
  PIN o[266]
    DIRECTION OUTPUT ;
    USE SIGNAL ;
    PORT
      LAYER M4 ;
        RECT  0 86.544 0.192 86.568 ;
    END
  END o[266]
  PIN o[267]
    DIRECTION OUTPUT ;
    USE SIGNAL ;
    PORT
      LAYER M4 ;
        RECT  0 86.88 0.192 86.904 ;
    END
  END o[267]
  PIN o[268]
    DIRECTION OUTPUT ;
    USE SIGNAL ;
    PORT
      LAYER M4 ;
        RECT  0 87.168 0.192 87.192 ;
    END
  END o[268]
  PIN o[269]
    DIRECTION OUTPUT ;
    USE SIGNAL ;
    PORT
      LAYER M4 ;
        RECT  0 87.504 0.192 87.528 ;
    END
  END o[269]
  PIN o[26]
    DIRECTION OUTPUT ;
    USE SIGNAL ;
    PORT
      LAYER M4 ;
        RECT  0 12.528 0.192 12.552 ;
    END
  END o[26]
  PIN o[270]
    DIRECTION OUTPUT ;
    USE SIGNAL ;
    PORT
      LAYER M4 ;
        RECT  0 87.792 0.192 87.816 ;
    END
  END o[270]
  PIN o[271]
    DIRECTION OUTPUT ;
    USE SIGNAL ;
    PORT
      LAYER M4 ;
        RECT  0 88.128 0.192 88.152 ;
    END
  END o[271]
  PIN o[272]
    DIRECTION OUTPUT ;
    USE SIGNAL ;
    PORT
      LAYER M4 ;
        RECT  0 88.416 0.192 88.44 ;
    END
  END o[272]
  PIN o[273]
    DIRECTION OUTPUT ;
    USE SIGNAL ;
    PORT
      LAYER M4 ;
        RECT  0 88.704 0.192 88.728 ;
    END
  END o[273]
  PIN o[274]
    DIRECTION OUTPUT ;
    USE SIGNAL ;
    PORT
      LAYER M4 ;
        RECT  0 89.04 0.192 89.064 ;
    END
  END o[274]
  PIN o[275]
    DIRECTION OUTPUT ;
    USE SIGNAL ;
    PORT
      LAYER M4 ;
        RECT  0 89.328 0.192 89.352 ;
    END
  END o[275]
  PIN o[276]
    DIRECTION OUTPUT ;
    USE SIGNAL ;
    PORT
      LAYER M4 ;
        RECT  0 89.664 0.192 89.688 ;
    END
  END o[276]
  PIN o[277]
    DIRECTION OUTPUT ;
    USE SIGNAL ;
    PORT
      LAYER M4 ;
        RECT  0 89.952 0.192 89.976 ;
    END
  END o[277]
  PIN o[278]
    DIRECTION OUTPUT ;
    USE SIGNAL ;
    PORT
      LAYER M4 ;
        RECT  0 90.288 0.192 90.312 ;
    END
  END o[278]
  PIN o[279]
    DIRECTION OUTPUT ;
    USE SIGNAL ;
    PORT
      LAYER M4 ;
        RECT  0 90.576 0.192 90.6 ;
    END
  END o[279]
  PIN o[27]
    DIRECTION OUTPUT ;
    USE SIGNAL ;
    PORT
      LAYER M4 ;
        RECT  0 12.816 0.192 12.84 ;
    END
  END o[27]
  PIN o[280]
    DIRECTION OUTPUT ;
    USE SIGNAL ;
    PORT
      LAYER M4 ;
        RECT  0 90.864 0.192 90.888 ;
    END
  END o[280]
  PIN o[281]
    DIRECTION OUTPUT ;
    USE SIGNAL ;
    PORT
      LAYER M4 ;
        RECT  0 91.2 0.192 91.224 ;
    END
  END o[281]
  PIN o[282]
    DIRECTION OUTPUT ;
    USE SIGNAL ;
    PORT
      LAYER M4 ;
        RECT  0 91.488 0.192 91.512 ;
    END
  END o[282]
  PIN o[283]
    DIRECTION OUTPUT ;
    USE SIGNAL ;
    PORT
      LAYER M4 ;
        RECT  0 91.824 0.192 91.848 ;
    END
  END o[283]
  PIN o[284]
    DIRECTION OUTPUT ;
    USE SIGNAL ;
    PORT
      LAYER M4 ;
        RECT  0 92.112 0.192 92.136 ;
    END
  END o[284]
  PIN o[285]
    DIRECTION OUTPUT ;
    USE SIGNAL ;
    PORT
      LAYER M4 ;
        RECT  0 92.448 0.192 92.472 ;
    END
  END o[285]
  PIN o[286]
    DIRECTION OUTPUT ;
    USE SIGNAL ;
    PORT
      LAYER M4 ;
        RECT  0 92.736 0.192 92.76 ;
    END
  END o[286]
  PIN o[287]
    DIRECTION OUTPUT ;
    USE SIGNAL ;
    PORT
      LAYER M4 ;
        RECT  0 93.024 0.192 93.048 ;
    END
  END o[287]
  PIN o[288]
    DIRECTION OUTPUT ;
    USE SIGNAL ;
    PORT
      LAYER M4 ;
        RECT  0 93.36 0.192 93.384 ;
    END
  END o[288]
  PIN o[289]
    DIRECTION OUTPUT ;
    USE SIGNAL ;
    PORT
      LAYER M4 ;
        RECT  0 93.648 0.192 93.672 ;
    END
  END o[289]
  PIN o[28]
    DIRECTION OUTPUT ;
    USE SIGNAL ;
    PORT
      LAYER M4 ;
        RECT  0 13.104 0.192 13.128 ;
    END
  END o[28]
  PIN o[290]
    DIRECTION OUTPUT ;
    USE SIGNAL ;
    PORT
      LAYER M4 ;
        RECT  0 93.984 0.192 94.008 ;
    END
  END o[290]
  PIN o[291]
    DIRECTION OUTPUT ;
    USE SIGNAL ;
    PORT
      LAYER M4 ;
        RECT  0 94.272 0.192 94.296 ;
    END
  END o[291]
  PIN o[292]
    DIRECTION OUTPUT ;
    USE SIGNAL ;
    PORT
      LAYER M4 ;
        RECT  0 94.608 0.192 94.632 ;
    END
  END o[292]
  PIN o[293]
    DIRECTION OUTPUT ;
    USE SIGNAL ;
    PORT
      LAYER M4 ;
        RECT  0 94.896 0.192 94.92 ;
    END
  END o[293]
  PIN o[29]
    DIRECTION OUTPUT ;
    USE SIGNAL ;
    PORT
      LAYER M4 ;
        RECT  0 13.44 0.192 13.464 ;
    END
  END o[29]
  PIN o[2]
    DIRECTION OUTPUT ;
    USE SIGNAL ;
    PORT
      LAYER M4 ;
        RECT  0 5.088 0.192 5.112 ;
    END
  END o[2]
  PIN o[30]
    DIRECTION OUTPUT ;
    USE SIGNAL ;
    PORT
      LAYER M4 ;
        RECT  0 13.728 0.192 13.752 ;
    END
  END o[30]
  PIN o[31]
    DIRECTION OUTPUT ;
    USE SIGNAL ;
    PORT
      LAYER M4 ;
        RECT  0 14.064 0.192 14.088 ;
    END
  END o[31]
  PIN o[32]
    DIRECTION OUTPUT ;
    USE SIGNAL ;
    PORT
      LAYER M4 ;
        RECT  0 14.352 0.192 14.376 ;
    END
  END o[32]
  PIN o[33]
    DIRECTION OUTPUT ;
    USE SIGNAL ;
    PORT
      LAYER M4 ;
        RECT  0 14.688 0.192 14.712 ;
    END
  END o[33]
  PIN o[34]
    DIRECTION OUTPUT ;
    USE SIGNAL ;
    PORT
      LAYER M4 ;
        RECT  0 14.976 0.192 15 ;
    END
  END o[34]
  PIN o[35]
    DIRECTION OUTPUT ;
    USE SIGNAL ;
    PORT
      LAYER M4 ;
        RECT  0 15.264 0.192 15.288 ;
    END
  END o[35]
  PIN o[36]
    DIRECTION OUTPUT ;
    USE SIGNAL ;
    PORT
      LAYER M4 ;
        RECT  0 15.6 0.192 15.624 ;
    END
  END o[36]
  PIN o[37]
    DIRECTION OUTPUT ;
    USE SIGNAL ;
    PORT
      LAYER M4 ;
        RECT  0 15.888 0.192 15.912 ;
    END
  END o[37]
  PIN o[38]
    DIRECTION OUTPUT ;
    USE SIGNAL ;
    PORT
      LAYER M4 ;
        RECT  0 16.224 0.192 16.248 ;
    END
  END o[38]
  PIN o[39]
    DIRECTION OUTPUT ;
    USE SIGNAL ;
    PORT
      LAYER M4 ;
        RECT  0 16.512 0.192 16.536 ;
    END
  END o[39]
  PIN o[3]
    DIRECTION OUTPUT ;
    USE SIGNAL ;
    PORT
      LAYER M4 ;
        RECT  0 5.424 0.192 5.448 ;
    END
  END o[3]
  PIN o[40]
    DIRECTION OUTPUT ;
    USE SIGNAL ;
    PORT
      LAYER M4 ;
        RECT  0 16.848 0.192 16.872 ;
    END
  END o[40]
  PIN o[41]
    DIRECTION OUTPUT ;
    USE SIGNAL ;
    PORT
      LAYER M4 ;
        RECT  0 17.136 0.192 17.16 ;
    END
  END o[41]
  PIN o[42]
    DIRECTION OUTPUT ;
    USE SIGNAL ;
    PORT
      LAYER M4 ;
        RECT  0 17.424 0.192 17.448 ;
    END
  END o[42]
  PIN o[43]
    DIRECTION OUTPUT ;
    USE SIGNAL ;
    PORT
      LAYER M4 ;
        RECT  0 17.76 0.192 17.784 ;
    END
  END o[43]
  PIN o[44]
    DIRECTION OUTPUT ;
    USE SIGNAL ;
    PORT
      LAYER M4 ;
        RECT  0 18.048 0.192 18.072 ;
    END
  END o[44]
  PIN o[45]
    DIRECTION OUTPUT ;
    USE SIGNAL ;
    PORT
      LAYER M4 ;
        RECT  0 18.384 0.192 18.408 ;
    END
  END o[45]
  PIN o[46]
    DIRECTION OUTPUT ;
    USE SIGNAL ;
    PORT
      LAYER M4 ;
        RECT  0 18.672 0.192 18.696 ;
    END
  END o[46]
  PIN o[47]
    DIRECTION OUTPUT ;
    USE SIGNAL ;
    PORT
      LAYER M4 ;
        RECT  0 19.008 0.192 19.032 ;
    END
  END o[47]
  PIN o[48]
    DIRECTION OUTPUT ;
    USE SIGNAL ;
    PORT
      LAYER M4 ;
        RECT  0 19.296 0.192 19.32 ;
    END
  END o[48]
  PIN o[49]
    DIRECTION OUTPUT ;
    USE SIGNAL ;
    PORT
      LAYER M4 ;
        RECT  0 19.584 0.192 19.608 ;
    END
  END o[49]
  PIN o[4]
    DIRECTION OUTPUT ;
    USE SIGNAL ;
    PORT
      LAYER M4 ;
        RECT  0 5.712 0.192 5.736 ;
    END
  END o[4]
  PIN o[50]
    DIRECTION OUTPUT ;
    USE SIGNAL ;
    PORT
      LAYER M4 ;
        RECT  0 19.92 0.192 19.944 ;
    END
  END o[50]
  PIN o[51]
    DIRECTION OUTPUT ;
    USE SIGNAL ;
    PORT
      LAYER M4 ;
        RECT  0 20.208 0.192 20.232 ;
    END
  END o[51]
  PIN o[52]
    DIRECTION OUTPUT ;
    USE SIGNAL ;
    PORT
      LAYER M4 ;
        RECT  0 20.544 0.192 20.568 ;
    END
  END o[52]
  PIN o[53]
    DIRECTION OUTPUT ;
    USE SIGNAL ;
    PORT
      LAYER M4 ;
        RECT  0 20.832 0.192 20.856 ;
    END
  END o[53]
  PIN o[54]
    DIRECTION OUTPUT ;
    USE SIGNAL ;
    PORT
      LAYER M4 ;
        RECT  0 21.168 0.192 21.192 ;
    END
  END o[54]
  PIN o[55]
    DIRECTION OUTPUT ;
    USE SIGNAL ;
    PORT
      LAYER M4 ;
        RECT  0 21.456 0.192 21.48 ;
    END
  END o[55]
  PIN o[56]
    DIRECTION OUTPUT ;
    USE SIGNAL ;
    PORT
      LAYER M4 ;
        RECT  0 21.744 0.192 21.768 ;
    END
  END o[56]
  PIN o[57]
    DIRECTION OUTPUT ;
    USE SIGNAL ;
    PORT
      LAYER M4 ;
        RECT  0 22.08 0.192 22.104 ;
    END
  END o[57]
  PIN o[58]
    DIRECTION OUTPUT ;
    USE SIGNAL ;
    PORT
      LAYER M4 ;
        RECT  0 22.368 0.192 22.392 ;
    END
  END o[58]
  PIN o[59]
    DIRECTION OUTPUT ;
    USE SIGNAL ;
    PORT
      LAYER M4 ;
        RECT  0 22.704 0.192 22.728 ;
    END
  END o[59]
  PIN o[5]
    DIRECTION OUTPUT ;
    USE SIGNAL ;
    PORT
      LAYER M4 ;
        RECT  0 6.048 0.192 6.072 ;
    END
  END o[5]
  PIN o[60]
    DIRECTION OUTPUT ;
    USE SIGNAL ;
    PORT
      LAYER M4 ;
        RECT  0 22.992 0.192 23.016 ;
    END
  END o[60]
  PIN o[61]
    DIRECTION OUTPUT ;
    USE SIGNAL ;
    PORT
      LAYER M4 ;
        RECT  0 23.328 0.192 23.352 ;
    END
  END o[61]
  PIN o[62]
    DIRECTION OUTPUT ;
    USE SIGNAL ;
    PORT
      LAYER M4 ;
        RECT  0 23.616 0.192 23.64 ;
    END
  END o[62]
  PIN o[63]
    DIRECTION OUTPUT ;
    USE SIGNAL ;
    PORT
      LAYER M4 ;
        RECT  0 23.904 0.192 23.928 ;
    END
  END o[63]
  PIN o[64]
    DIRECTION OUTPUT ;
    USE SIGNAL ;
    PORT
      LAYER M4 ;
        RECT  0 24.24 0.192 24.264 ;
    END
  END o[64]
  PIN o[65]
    DIRECTION OUTPUT ;
    USE SIGNAL ;
    PORT
      LAYER M4 ;
        RECT  0 24.528 0.192 24.552 ;
    END
  END o[65]
  PIN o[66]
    DIRECTION OUTPUT ;
    USE SIGNAL ;
    PORT
      LAYER M4 ;
        RECT  0 24.864 0.192 24.888 ;
    END
  END o[66]
  PIN o[67]
    DIRECTION OUTPUT ;
    USE SIGNAL ;
    PORT
      LAYER M4 ;
        RECT  0 25.152 0.192 25.176 ;
    END
  END o[67]
  PIN o[68]
    DIRECTION OUTPUT ;
    USE SIGNAL ;
    PORT
      LAYER M4 ;
        RECT  0 25.488 0.192 25.512 ;
    END
  END o[68]
  PIN o[69]
    DIRECTION OUTPUT ;
    USE SIGNAL ;
    PORT
      LAYER M4 ;
        RECT  0 25.776 0.192 25.8 ;
    END
  END o[69]
  PIN o[6]
    DIRECTION OUTPUT ;
    USE SIGNAL ;
    PORT
      LAYER M4 ;
        RECT  0 6.336 0.192 6.36 ;
    END
  END o[6]
  PIN o[70]
    DIRECTION OUTPUT ;
    USE SIGNAL ;
    PORT
      LAYER M4 ;
        RECT  0 26.064 0.192 26.088 ;
    END
  END o[70]
  PIN o[71]
    DIRECTION OUTPUT ;
    USE SIGNAL ;
    PORT
      LAYER M4 ;
        RECT  0 26.4 0.192 26.424 ;
    END
  END o[71]
  PIN o[72]
    DIRECTION OUTPUT ;
    USE SIGNAL ;
    PORT
      LAYER M4 ;
        RECT  0 26.688 0.192 26.712 ;
    END
  END o[72]
  PIN o[73]
    DIRECTION OUTPUT ;
    USE SIGNAL ;
    PORT
      LAYER M4 ;
        RECT  0 27.024 0.192 27.048 ;
    END
  END o[73]
  PIN o[74]
    DIRECTION OUTPUT ;
    USE SIGNAL ;
    PORT
      LAYER M4 ;
        RECT  0 27.312 0.192 27.336 ;
    END
  END o[74]
  PIN o[75]
    DIRECTION OUTPUT ;
    USE SIGNAL ;
    PORT
      LAYER M4 ;
        RECT  0 27.648 0.192 27.672 ;
    END
  END o[75]
  PIN o[76]
    DIRECTION OUTPUT ;
    USE SIGNAL ;
    PORT
      LAYER M4 ;
        RECT  0 27.936 0.192 27.96 ;
    END
  END o[76]
  PIN o[77]
    DIRECTION OUTPUT ;
    USE SIGNAL ;
    PORT
      LAYER M4 ;
        RECT  0 28.224 0.192 28.248 ;
    END
  END o[77]
  PIN o[78]
    DIRECTION OUTPUT ;
    USE SIGNAL ;
    PORT
      LAYER M4 ;
        RECT  0 28.56 0.192 28.584 ;
    END
  END o[78]
  PIN o[79]
    DIRECTION OUTPUT ;
    USE SIGNAL ;
    PORT
      LAYER M4 ;
        RECT  0 28.848 0.192 28.872 ;
    END
  END o[79]
  PIN o[7]
    DIRECTION OUTPUT ;
    USE SIGNAL ;
    PORT
      LAYER M4 ;
        RECT  0 6.624 0.192 6.648 ;
    END
  END o[7]
  PIN o[80]
    DIRECTION OUTPUT ;
    USE SIGNAL ;
    PORT
      LAYER M4 ;
        RECT  0 29.184 0.192 29.208 ;
    END
  END o[80]
  PIN o[81]
    DIRECTION OUTPUT ;
    USE SIGNAL ;
    PORT
      LAYER M4 ;
        RECT  0 29.472 0.192 29.496 ;
    END
  END o[81]
  PIN o[82]
    DIRECTION OUTPUT ;
    USE SIGNAL ;
    PORT
      LAYER M4 ;
        RECT  0 29.808 0.192 29.832 ;
    END
  END o[82]
  PIN o[83]
    DIRECTION OUTPUT ;
    USE SIGNAL ;
    PORT
      LAYER M4 ;
        RECT  0 30.096 0.192 30.12 ;
    END
  END o[83]
  PIN o[84]
    DIRECTION OUTPUT ;
    USE SIGNAL ;
    PORT
      LAYER M4 ;
        RECT  0 30.384 0.192 30.408 ;
    END
  END o[84]
  PIN o[85]
    DIRECTION OUTPUT ;
    USE SIGNAL ;
    PORT
      LAYER M4 ;
        RECT  0 30.72 0.192 30.744 ;
    END
  END o[85]
  PIN o[86]
    DIRECTION OUTPUT ;
    USE SIGNAL ;
    PORT
      LAYER M4 ;
        RECT  0 31.008 0.192 31.032 ;
    END
  END o[86]
  PIN o[87]
    DIRECTION OUTPUT ;
    USE SIGNAL ;
    PORT
      LAYER M4 ;
        RECT  0 31.344 0.192 31.368 ;
    END
  END o[87]
  PIN o[88]
    DIRECTION OUTPUT ;
    USE SIGNAL ;
    PORT
      LAYER M4 ;
        RECT  0 31.632 0.192 31.656 ;
    END
  END o[88]
  PIN o[89]
    DIRECTION OUTPUT ;
    USE SIGNAL ;
    PORT
      LAYER M4 ;
        RECT  0 31.968 0.192 31.992 ;
    END
  END o[89]
  PIN o[8]
    DIRECTION OUTPUT ;
    USE SIGNAL ;
    PORT
      LAYER M4 ;
        RECT  0 6.96 0.192 6.984 ;
    END
  END o[8]
  PIN o[90]
    DIRECTION OUTPUT ;
    USE SIGNAL ;
    PORT
      LAYER M4 ;
        RECT  0 32.256 0.192 32.28 ;
    END
  END o[90]
  PIN o[91]
    DIRECTION OUTPUT ;
    USE SIGNAL ;
    PORT
      LAYER M4 ;
        RECT  0 32.544 0.192 32.568 ;
    END
  END o[91]
  PIN o[92]
    DIRECTION OUTPUT ;
    USE SIGNAL ;
    PORT
      LAYER M4 ;
        RECT  0 32.88 0.192 32.904 ;
    END
  END o[92]
  PIN o[93]
    DIRECTION OUTPUT ;
    USE SIGNAL ;
    PORT
      LAYER M4 ;
        RECT  0 33.168 0.192 33.192 ;
    END
  END o[93]
  PIN o[94]
    DIRECTION OUTPUT ;
    USE SIGNAL ;
    PORT
      LAYER M4 ;
        RECT  0 33.504 0.192 33.528 ;
    END
  END o[94]
  PIN o[95]
    DIRECTION OUTPUT ;
    USE SIGNAL ;
    PORT
      LAYER M4 ;
        RECT  0 33.792 0.192 33.816 ;
    END
  END o[95]
  PIN o[96]
    DIRECTION OUTPUT ;
    USE SIGNAL ;
    PORT
      LAYER M4 ;
        RECT  0 34.128 0.192 34.152 ;
    END
  END o[96]
  PIN o[97]
    DIRECTION OUTPUT ;
    USE SIGNAL ;
    PORT
      LAYER M4 ;
        RECT  0 34.416 0.192 34.44 ;
    END
  END o[97]
  PIN o[98]
    DIRECTION OUTPUT ;
    USE SIGNAL ;
    PORT
      LAYER M4 ;
        RECT  0 34.704 0.192 34.728 ;
    END
  END o[98]
  PIN o[99]
    DIRECTION OUTPUT ;
    USE SIGNAL ;
    PORT
      LAYER M4 ;
        RECT  0 35.04 0.192 35.064 ;
    END
  END o[99]
  PIN o[9]
    DIRECTION OUTPUT ;
    USE SIGNAL ;
    PORT
      LAYER M4 ;
        RECT  0 7.248 0.192 7.272 ;
    END
  END o[9]
  PIN rs[0]
    DIRECTION INPUT ;
    USE SIGNAL ;
    PORT
      LAYER M5 ;
        RECT  70.752 0 70.776 0.192 ;
    END
    PORT
      LAYER M5 ;
        RECT  70.752 0.144 70.776 0.323 ;
    END
  END rs[0]
  PIN VDD
    DIRECTION INOUT ;
    USE POWER ;
    PORT
      LAYER M5 ;
        RECT  94.392 2.151 94.512 97.209 ;
        RECT  91.692 2.151 91.812 97.209 ;
        RECT  88.992 2.151 89.112 97.209 ;
        RECT  86.292 2.151 86.412 97.209 ;
        RECT  83.592 2.151 83.712 97.209 ;
        RECT  80.892 2.151 81.012 97.209 ;
        RECT  78.192 2.151 78.312 97.209 ;
        RECT  75.492 2.151 75.612 97.209 ;
        RECT  72.792 2.151 72.912 97.209 ;
        RECT  70.092 2.151 70.212 97.209 ;
        RECT  67.392 2.151 67.512 97.209 ;
        RECT  64.692 2.151 64.812 97.209 ;
        RECT  61.992 2.151 62.112 97.209 ;
        RECT  59.292 2.151 59.412 97.209 ;
        RECT  56.592 2.151 56.712 97.209 ;
        RECT  53.892 2.151 54.012 97.209 ;
        RECT  51.192 2.151 51.312 97.209 ;
        RECT  48.492 2.151 48.612 97.209 ;
        RECT  45.792 2.151 45.912 97.209 ;
        RECT  43.092 2.151 43.212 97.209 ;
        RECT  40.392 2.151 40.512 97.209 ;
        RECT  37.692 2.151 37.812 97.209 ;
        RECT  34.992 2.151 35.112 97.209 ;
        RECT  32.292 2.151 32.412 97.209 ;
        RECT  29.592 2.151 29.712 97.209 ;
        RECT  26.892 2.151 27.012 97.209 ;
        RECT  24.192 2.151 24.312 97.209 ;
        RECT  21.492 2.151 21.612 97.209 ;
        RECT  18.792 2.151 18.912 97.209 ;
        RECT  16.092 2.151 16.212 97.209 ;
        RECT  13.392 2.151 13.512 97.209 ;
        RECT  10.692 2.151 10.812 97.209 ;
        RECT  7.992 2.151 8.112 97.209 ;
        RECT  5.292 2.151 5.412 97.209 ;
        RECT  2.592 2.151 2.712 97.209 ;
    END
  END VDD
  PIN VSS
    DIRECTION INOUT ;
    USE GROUND ;
    PORT
      LAYER M5 ;
        RECT  94.2 2.137 94.32 97.223 ;
        RECT  91.5 2.137 91.62 97.223 ;
        RECT  88.8 2.137 88.92 97.223 ;
        RECT  86.1 2.137 86.22 97.223 ;
        RECT  83.4 2.137 83.52 97.223 ;
        RECT  80.7 2.137 80.82 97.223 ;
        RECT  78 2.137 78.12 97.223 ;
        RECT  75.3 2.137 75.42 97.223 ;
        RECT  72.6 2.137 72.72 97.223 ;
        RECT  69.9 2.137 70.02 97.223 ;
        RECT  67.2 2.137 67.32 97.223 ;
        RECT  64.5 2.137 64.62 97.223 ;
        RECT  61.8 2.137 61.92 97.223 ;
        RECT  59.1 2.137 59.22 97.223 ;
        RECT  56.4 2.137 56.52 97.223 ;
        RECT  53.7 2.137 53.82 97.223 ;
        RECT  51 2.137 51.12 97.223 ;
        RECT  48.3 2.137 48.42 97.223 ;
        RECT  45.6 2.137 45.72 97.223 ;
        RECT  42.9 2.137 43.02 97.223 ;
        RECT  40.2 2.137 40.32 97.223 ;
        RECT  37.5 2.137 37.62 97.223 ;
        RECT  34.8 2.137 34.92 97.223 ;
        RECT  32.1 2.137 32.22 97.223 ;
        RECT  29.4 2.137 29.52 97.223 ;
        RECT  26.7 2.137 26.82 97.223 ;
        RECT  24 2.137 24.12 97.223 ;
        RECT  21.3 2.137 21.42 97.223 ;
        RECT  18.6 2.137 18.72 97.223 ;
        RECT  15.9 2.137 16.02 97.223 ;
        RECT  13.2 2.137 13.32 97.223 ;
        RECT  10.5 2.137 10.62 97.223 ;
        RECT  7.8 2.137 7.92 97.223 ;
        RECT  5.1 2.137 5.22 97.223 ;
        RECT  2.4 2.137 2.52 97.223 ;
    END
  END VSS
  # OT_OBS_CLOSED layer=M5 d_um=1.536 added=591
  OBS
    LAYER RVTN ;
     RECT  2.16 2.16 95.04 2.295 ;
     RECT  2.16 2.565 95.04 2.835 ;
     RECT  2.16 3.105 95.04 3.375 ;
     RECT  2.16 3.645 95.04 3.915 ;
     RECT  2.16 4.185 95.04 4.455 ;
     RECT  2.16 4.725 95.04 4.995 ;
     RECT  2.16 5.265 95.04 5.535 ;
     RECT  2.16 5.805 95.04 6.075 ;
     RECT  2.16 6.345 95.04 6.615 ;
     RECT  2.16 6.885 95.04 7.155 ;
     RECT  2.16 7.425 95.04 7.695 ;
     RECT  2.16 7.965 95.04 8.235 ;
     RECT  2.16 8.505 95.04 8.775 ;
     RECT  2.16 9.045 95.04 9.315 ;
     RECT  2.16 9.585 95.04 9.855 ;
     RECT  2.16 10.125 95.04 10.395 ;
     RECT  2.16 10.665 95.04 10.935 ;
     RECT  2.16 11.205 95.04 11.475 ;
     RECT  2.16 11.745 95.04 12.015 ;
     RECT  2.16 12.285 95.04 12.555 ;
     RECT  2.16 12.825 95.04 13.095 ;
     RECT  2.16 13.365 95.04 13.635 ;
     RECT  2.16 13.905 95.04 14.175 ;
     RECT  2.16 14.445 95.04 14.715 ;
     RECT  2.16 14.985 95.04 15.255 ;
     RECT  2.16 15.525 95.04 15.795 ;
     RECT  2.16 16.065 95.04 16.335 ;
     RECT  2.16 16.605 95.04 16.875 ;
     RECT  2.16 17.145 95.04 17.415 ;
     RECT  2.16 17.685 95.04 17.955 ;
     RECT  2.16 18.225 95.04 18.495 ;
     RECT  2.16 18.765 95.04 19.035 ;
     RECT  2.16 19.305 95.04 19.575 ;
     RECT  2.16 19.845 95.04 20.115 ;
     RECT  2.16 20.385 95.04 20.655 ;
     RECT  2.16 20.925 95.04 21.195 ;
     RECT  2.16 21.465 95.04 21.735 ;
     RECT  2.16 22.005 95.04 22.275 ;
     RECT  2.16 22.545 95.04 22.815 ;
     RECT  2.16 23.085 95.04 23.355 ;
     RECT  2.16 23.625 95.04 23.895 ;
     RECT  2.16 24.165 95.04 24.435 ;
     RECT  2.16 24.705 95.04 24.975 ;
     RECT  2.16 25.245 95.04 25.515 ;
     RECT  2.16 25.785 95.04 26.055 ;
     RECT  2.16 26.325 95.04 26.595 ;
     RECT  2.16 26.865 95.04 27.135 ;
     RECT  2.16 27.405 95.04 27.675 ;
     RECT  2.16 27.945 95.04 28.215 ;
     RECT  2.16 28.485 95.04 28.755 ;
     RECT  2.16 29.025 95.04 29.295 ;
     RECT  2.16 29.565 95.04 29.835 ;
     RECT  2.16 30.105 95.04 30.375 ;
     RECT  2.16 30.645 95.04 30.915 ;
     RECT  2.16 31.185 95.04 31.455 ;
     RECT  2.16 31.725 95.04 31.995 ;
     RECT  2.16 32.265 95.04 32.535 ;
     RECT  2.16 32.805 95.04 33.075 ;
     RECT  2.16 33.345 95.04 33.615 ;
     RECT  2.16 33.885 95.04 34.155 ;
     RECT  2.16 34.425 95.04 34.695 ;
     RECT  2.16 34.965 95.04 35.235 ;
     RECT  2.16 35.505 95.04 35.775 ;
     RECT  2.16 36.045 95.04 36.315 ;
     RECT  2.16 36.585 95.04 36.855 ;
     RECT  2.16 37.125 95.04 37.395 ;
     RECT  2.16 37.665 95.04 37.935 ;
     RECT  2.16 38.205 95.04 38.475 ;
     RECT  2.16 38.745 95.04 39.015 ;
     RECT  2.16 39.285 95.04 39.555 ;
     RECT  2.16 39.825 95.04 40.095 ;
     RECT  2.16 40.365 95.04 40.635 ;
     RECT  2.16 40.905 95.04 41.175 ;
     RECT  2.16 41.445 95.04 41.715 ;
     RECT  2.16 41.985 95.04 42.255 ;
     RECT  2.16 42.525 95.04 42.795 ;
     RECT  2.16 43.065 95.04 43.335 ;
     RECT  2.16 43.605 95.04 43.875 ;
     RECT  2.16 44.145 95.04 44.415 ;
     RECT  2.16 44.685 95.04 44.955 ;
     RECT  2.16 45.225 95.04 45.495 ;
     RECT  2.16 45.765 95.04 46.035 ;
     RECT  2.16 46.305 95.04 46.575 ;
     RECT  2.16 46.845 95.04 47.115 ;
     RECT  2.16 47.385 95.04 47.655 ;
     RECT  2.16 47.925 95.04 48.195 ;
     RECT  2.16 48.465 95.04 48.735 ;
     RECT  2.16 49.005 95.04 49.275 ;
     RECT  2.16 49.545 95.04 49.815 ;
     RECT  2.16 50.085 95.04 50.355 ;
     RECT  2.16 50.625 95.04 50.895 ;
     RECT  2.16 51.165 95.04 51.435 ;
     RECT  2.16 51.705 95.04 51.975 ;
     RECT  2.16 52.245 95.04 52.515 ;
     RECT  2.16 52.785 95.04 53.055 ;
     RECT  2.16 53.325 95.04 53.595 ;
     RECT  2.16 53.865 95.04 54.135 ;
     RECT  2.16 54.405 95.04 54.675 ;
     RECT  2.16 54.945 95.04 55.215 ;
     RECT  2.16 55.485 95.04 55.755 ;
     RECT  2.16 56.025 95.04 56.295 ;
     RECT  2.16 56.565 95.04 56.835 ;
     RECT  2.16 57.105 95.04 57.375 ;
     RECT  2.16 57.645 95.04 57.915 ;
     RECT  2.16 58.185 95.04 58.455 ;
     RECT  2.16 58.725 95.04 58.995 ;
     RECT  2.16 59.265 95.04 59.535 ;
     RECT  2.16 59.805 95.04 60.075 ;
     RECT  2.16 60.345 95.04 60.615 ;
     RECT  2.16 60.885 95.04 61.155 ;
     RECT  2.16 61.425 95.04 61.695 ;
     RECT  2.16 61.965 95.04 62.235 ;
     RECT  2.16 62.505 95.04 62.775 ;
     RECT  2.16 63.045 95.04 63.315 ;
     RECT  2.16 63.585 95.04 63.855 ;
     RECT  2.16 64.125 95.04 64.395 ;
     RECT  2.16 64.665 95.04 64.935 ;
     RECT  2.16 65.205 95.04 65.475 ;
     RECT  2.16 65.745 95.04 66.015 ;
     RECT  2.16 66.285 95.04 66.555 ;
     RECT  2.16 66.825 95.04 67.095 ;
     RECT  2.16 67.365 95.04 67.635 ;
     RECT  2.16 67.905 95.04 68.175 ;
     RECT  2.16 68.445 95.04 68.715 ;
     RECT  2.16 68.985 95.04 69.255 ;
     RECT  2.16 69.525 95.04 69.795 ;
     RECT  2.16 70.065 95.04 70.335 ;
     RECT  2.16 70.605 95.04 70.875 ;
     RECT  2.16 71.145 95.04 71.415 ;
     RECT  2.16 71.685 95.04 71.955 ;
     RECT  2.16 72.225 95.04 72.495 ;
     RECT  2.16 72.765 95.04 73.035 ;
     RECT  2.16 73.305 95.04 73.575 ;
     RECT  2.16 73.845 95.04 74.115 ;
     RECT  2.16 74.385 95.04 74.655 ;
     RECT  2.16 74.925 95.04 75.195 ;
     RECT  2.16 75.465 95.04 75.735 ;
     RECT  2.16 76.005 95.04 76.275 ;
     RECT  2.16 76.545 95.04 76.815 ;
     RECT  2.16 77.085 95.04 77.355 ;
     RECT  2.16 77.625 95.04 77.895 ;
     RECT  2.16 78.165 95.04 78.435 ;
     RECT  2.16 78.705 95.04 78.975 ;
     RECT  2.16 79.245 95.04 79.515 ;
     RECT  2.16 79.785 95.04 80.055 ;
     RECT  2.16 80.325 95.04 80.595 ;
     RECT  2.16 80.865 95.04 81.135 ;
     RECT  2.16 81.405 95.04 81.675 ;
     RECT  2.16 81.945 95.04 82.215 ;
     RECT  2.16 82.485 95.04 82.755 ;
     RECT  2.16 83.025 95.04 83.295 ;
     RECT  2.16 83.565 95.04 83.835 ;
     RECT  2.16 84.105 95.04 84.375 ;
     RECT  2.16 84.645 95.04 84.915 ;
     RECT  2.16 85.185 95.04 85.455 ;
     RECT  2.16 85.725 95.04 85.995 ;
     RECT  2.16 86.265 95.04 86.535 ;
     RECT  2.16 86.805 95.04 87.075 ;
     RECT  2.16 87.345 95.04 87.615 ;
     RECT  2.16 87.885 95.04 88.155 ;
     RECT  2.16 88.425 95.04 88.695 ;
     RECT  2.16 88.965 95.04 89.235 ;
     RECT  2.16 89.505 95.04 89.775 ;
     RECT  2.16 90.045 95.04 90.315 ;
     RECT  2.16 90.585 95.04 90.855 ;
     RECT  2.16 91.125 95.04 91.395 ;
     RECT  2.16 91.665 95.04 91.935 ;
     RECT  2.16 92.205 95.04 92.475 ;
     RECT  2.16 92.745 95.04 93.015 ;
     RECT  2.16 93.285 95.04 93.555 ;
     RECT  2.16 93.825 95.04 94.095 ;
     RECT  2.16 94.365 95.04 94.635 ;
     RECT  2.16 94.905 95.04 95.175 ;
     RECT  2.16 95.445 95.04 95.715 ;
     RECT  2.16 95.985 95.04 96.255 ;
     RECT  2.16 96.525 95.04 96.795 ;
     RECT  2.16 97.065 95.04 97.2 ;
    LAYER RVTP ;
     RECT  2.16 2.295 95.04 2.565 ;
     RECT  2.16 2.835 95.04 3.105 ;
     RECT  2.16 3.375 95.04 3.645 ;
     RECT  2.16 3.915 95.04 4.185 ;
     RECT  2.16 4.455 95.04 4.725 ;
     RECT  2.16 4.995 95.04 5.265 ;
     RECT  2.16 5.535 95.04 5.805 ;
     RECT  2.16 6.075 95.04 6.345 ;
     RECT  2.16 6.615 95.04 6.885 ;
     RECT  2.16 7.155 95.04 7.425 ;
     RECT  2.16 7.695 95.04 7.965 ;
     RECT  2.16 8.235 95.04 8.505 ;
     RECT  2.16 8.775 95.04 9.045 ;
     RECT  2.16 9.315 95.04 9.585 ;
     RECT  2.16 9.855 95.04 10.125 ;
     RECT  2.16 10.395 95.04 10.665 ;
     RECT  2.16 10.935 95.04 11.205 ;
     RECT  2.16 11.475 95.04 11.745 ;
     RECT  2.16 12.015 95.04 12.285 ;
     RECT  2.16 12.555 95.04 12.825 ;
     RECT  2.16 13.095 95.04 13.365 ;
     RECT  2.16 13.635 95.04 13.905 ;
     RECT  2.16 14.175 95.04 14.445 ;
     RECT  2.16 14.715 95.04 14.985 ;
     RECT  2.16 15.255 95.04 15.525 ;
     RECT  2.16 15.795 95.04 16.065 ;
     RECT  2.16 16.335 95.04 16.605 ;
     RECT  2.16 16.875 95.04 17.145 ;
     RECT  2.16 17.415 95.04 17.685 ;
     RECT  2.16 17.955 95.04 18.225 ;
     RECT  2.16 18.495 95.04 18.765 ;
     RECT  2.16 19.035 95.04 19.305 ;
     RECT  2.16 19.575 95.04 19.845 ;
     RECT  2.16 20.115 95.04 20.385 ;
     RECT  2.16 20.655 95.04 20.925 ;
     RECT  2.16 21.195 95.04 21.465 ;
     RECT  2.16 21.735 95.04 22.005 ;
     RECT  2.16 22.275 95.04 22.545 ;
     RECT  2.16 22.815 95.04 23.085 ;
     RECT  2.16 23.355 95.04 23.625 ;
     RECT  2.16 23.895 95.04 24.165 ;
     RECT  2.16 24.435 95.04 24.705 ;
     RECT  2.16 24.975 95.04 25.245 ;
     RECT  2.16 25.515 95.04 25.785 ;
     RECT  2.16 26.055 95.04 26.325 ;
     RECT  2.16 26.595 95.04 26.865 ;
     RECT  2.16 27.135 95.04 27.405 ;
     RECT  2.16 27.675 95.04 27.945 ;
     RECT  2.16 28.215 95.04 28.485 ;
     RECT  2.16 28.755 95.04 29.025 ;
     RECT  2.16 29.295 95.04 29.565 ;
     RECT  2.16 29.835 95.04 30.105 ;
     RECT  2.16 30.375 95.04 30.645 ;
     RECT  2.16 30.915 95.04 31.185 ;
     RECT  2.16 31.455 95.04 31.725 ;
     RECT  2.16 31.995 95.04 32.265 ;
     RECT  2.16 32.535 95.04 32.805 ;
     RECT  2.16 33.075 95.04 33.345 ;
     RECT  2.16 33.615 95.04 33.885 ;
     RECT  2.16 34.155 95.04 34.425 ;
     RECT  2.16 34.695 95.04 34.965 ;
     RECT  2.16 35.235 95.04 35.505 ;
     RECT  2.16 35.775 95.04 36.045 ;
     RECT  2.16 36.315 95.04 36.585 ;
     RECT  2.16 36.855 95.04 37.125 ;
     RECT  2.16 37.395 95.04 37.665 ;
     RECT  2.16 37.935 95.04 38.205 ;
     RECT  2.16 38.475 95.04 38.745 ;
     RECT  2.16 39.015 95.04 39.285 ;
     RECT  2.16 39.555 95.04 39.825 ;
     RECT  2.16 40.095 95.04 40.365 ;
     RECT  2.16 40.635 95.04 40.905 ;
     RECT  2.16 41.175 95.04 41.445 ;
     RECT  2.16 41.715 95.04 41.985 ;
     RECT  2.16 42.255 95.04 42.525 ;
     RECT  2.16 42.795 95.04 43.065 ;
     RECT  2.16 43.335 95.04 43.605 ;
     RECT  2.16 43.875 95.04 44.145 ;
     RECT  2.16 44.415 95.04 44.685 ;
     RECT  2.16 44.955 95.04 45.225 ;
     RECT  2.16 45.495 95.04 45.765 ;
     RECT  2.16 46.035 95.04 46.305 ;
     RECT  2.16 46.575 95.04 46.845 ;
     RECT  2.16 47.115 95.04 47.385 ;
     RECT  2.16 47.655 95.04 47.925 ;
     RECT  2.16 48.195 95.04 48.465 ;
     RECT  2.16 48.735 95.04 49.005 ;
     RECT  2.16 49.275 95.04 49.545 ;
     RECT  2.16 49.815 95.04 50.085 ;
     RECT  2.16 50.355 95.04 50.625 ;
     RECT  2.16 50.895 95.04 51.165 ;
     RECT  2.16 51.435 95.04 51.705 ;
     RECT  2.16 51.975 95.04 52.245 ;
     RECT  2.16 52.515 95.04 52.785 ;
     RECT  2.16 53.055 95.04 53.325 ;
     RECT  2.16 53.595 95.04 53.865 ;
     RECT  2.16 54.135 95.04 54.405 ;
     RECT  2.16 54.675 95.04 54.945 ;
     RECT  2.16 55.215 95.04 55.485 ;
     RECT  2.16 55.755 95.04 56.025 ;
     RECT  2.16 56.295 95.04 56.565 ;
     RECT  2.16 56.835 95.04 57.105 ;
     RECT  2.16 57.375 95.04 57.645 ;
     RECT  2.16 57.915 95.04 58.185 ;
     RECT  2.16 58.455 95.04 58.725 ;
     RECT  2.16 58.995 95.04 59.265 ;
     RECT  2.16 59.535 95.04 59.805 ;
     RECT  2.16 60.075 95.04 60.345 ;
     RECT  2.16 60.615 95.04 60.885 ;
     RECT  2.16 61.155 95.04 61.425 ;
     RECT  2.16 61.695 95.04 61.965 ;
     RECT  2.16 62.235 95.04 62.505 ;
     RECT  2.16 62.775 95.04 63.045 ;
     RECT  2.16 63.315 95.04 63.585 ;
     RECT  2.16 63.855 95.04 64.125 ;
     RECT  2.16 64.395 95.04 64.665 ;
     RECT  2.16 64.935 95.04 65.205 ;
     RECT  2.16 65.475 95.04 65.745 ;
     RECT  2.16 66.015 95.04 66.285 ;
     RECT  2.16 66.555 95.04 66.825 ;
     RECT  2.16 67.095 95.04 67.365 ;
     RECT  2.16 67.635 95.04 67.905 ;
     RECT  2.16 68.175 95.04 68.445 ;
     RECT  2.16 68.715 95.04 68.985 ;
     RECT  2.16 69.255 95.04 69.525 ;
     RECT  2.16 69.795 95.04 70.065 ;
     RECT  2.16 70.335 95.04 70.605 ;
     RECT  2.16 70.875 95.04 71.145 ;
     RECT  2.16 71.415 95.04 71.685 ;
     RECT  2.16 71.955 95.04 72.225 ;
     RECT  2.16 72.495 95.04 72.765 ;
     RECT  2.16 73.035 95.04 73.305 ;
     RECT  2.16 73.575 95.04 73.845 ;
     RECT  2.16 74.115 95.04 74.385 ;
     RECT  2.16 74.655 95.04 74.925 ;
     RECT  2.16 75.195 95.04 75.465 ;
     RECT  2.16 75.735 95.04 76.005 ;
     RECT  2.16 76.275 95.04 76.545 ;
     RECT  2.16 76.815 95.04 77.085 ;
     RECT  2.16 77.355 95.04 77.625 ;
     RECT  2.16 77.895 95.04 78.165 ;
     RECT  2.16 78.435 95.04 78.705 ;
     RECT  2.16 78.975 95.04 79.245 ;
     RECT  2.16 79.515 95.04 79.785 ;
     RECT  2.16 80.055 95.04 80.325 ;
     RECT  2.16 80.595 95.04 80.865 ;
     RECT  2.16 81.135 95.04 81.405 ;
     RECT  2.16 81.675 95.04 81.945 ;
     RECT  2.16 82.215 95.04 82.485 ;
     RECT  2.16 82.755 95.04 83.025 ;
     RECT  2.16 83.295 95.04 83.565 ;
     RECT  2.16 83.835 95.04 84.105 ;
     RECT  2.16 84.375 95.04 84.645 ;
     RECT  2.16 84.915 95.04 85.185 ;
     RECT  2.16 85.455 95.04 85.725 ;
     RECT  2.16 85.995 95.04 86.265 ;
     RECT  2.16 86.535 95.04 86.805 ;
     RECT  2.16 87.075 95.04 87.345 ;
     RECT  2.16 87.615 95.04 87.885 ;
     RECT  2.16 88.155 95.04 88.425 ;
     RECT  2.16 88.695 95.04 88.965 ;
     RECT  2.16 89.235 95.04 89.505 ;
     RECT  2.16 89.775 95.04 90.045 ;
     RECT  2.16 90.315 95.04 90.585 ;
     RECT  2.16 90.855 95.04 91.125 ;
     RECT  2.16 91.395 95.04 91.665 ;
     RECT  2.16 91.935 95.04 92.205 ;
     RECT  2.16 92.475 95.04 92.745 ;
     RECT  2.16 93.015 95.04 93.285 ;
     RECT  2.16 93.555 95.04 93.825 ;
     RECT  2.16 94.095 95.04 94.365 ;
     RECT  2.16 94.635 95.04 94.905 ;
     RECT  2.16 95.175 95.04 95.445 ;
     RECT  2.16 95.715 95.04 95.985 ;
     RECT  2.16 96.255 95.04 96.525 ;
     RECT  2.16 96.795 95.04 97.065 ;
    LAYER M1 ;
     RECT  2.16 2.151 95.04 97.209 ;
    LAYER M2 ;
     RECT  0.211 88.326 0.535 88.344 ;
     RECT  0.211 93.996 0.535 94.014 ;
     RECT  0.211 5.004 2.16 5.022 ;
     RECT  0.535 6.156 2.16 6.174 ;
     RECT  0.535 8.586 2.16 8.604 ;
     RECT  0.211 11.556 2.16 11.574 ;
     RECT  0.211 15.498 2.16 16.254 ;
     RECT  0.211 19.548 2.16 19.566 ;
     RECT  0.211 20.394 2.16 20.412 ;
     RECT  0.247 22.716 2.16 22.734 ;
     RECT  0.211 37.026 2.16 37.044 ;
     RECT  0.247 42.426 2.16 42.444 ;
     RECT  0.211 43.236 2.16 43.254 ;
     RECT  0.211 52.416 2.16 52.434 ;
     RECT  0.211 53.496 2.16 53.514 ;
     RECT  0.535 66.096 2.16 66.114 ;
     RECT  0.535 73.476 2.16 73.494 ;
     RECT  0.535 76.518 2.16 76.536 ;
     RECT  0.535 81.414 2.16 81.432 ;
     RECT  0.535 87.048 2.16 87.066 ;
     RECT  0.535 87.93 2.16 88.344 ;
     RECT  0.535 90.018 2.16 90.036 ;
     RECT  0.535 93.996 2.16 94.554 ;
     RECT  2.16 2.151 15.835 97.209 ;
     RECT  15.835 2.151 15.935 97.29 ;
     RECT  15.935 2.151 21.343 97.209 ;
     RECT  21.343 2.151 21.479 97.29 ;
     RECT  26.671 98.586 26.771 98.604 ;
     RECT  21.479 2.151 32.071 97.209 ;
     RECT  32.071 2.151 32.207 97.29 ;
     RECT  32.207 2.151 37.219 97.209 ;
     RECT  37.219 2.151 37.607 97.29 ;
     RECT  42.871 98.586 43.043 98.604 ;
     RECT  70.123 98.586 70.259 98.604 ;
     RECT  75.451 98.586 75.587 98.604 ;
     RECT  37.607 2.151 88.735 97.209 ;
     RECT  88.735 2.151 88.835 97.29 ;
     RECT  88.835 2.151 95.04 97.209 ;
    LAYER M3 ;
     RECT  26.388 0.283 26.406 2.143 ;
     RECT  2.415 2.143 2.505 2.413 ;
     RECT  5.115 2.143 5.205 2.413 ;
     RECT  7.815 2.143 7.905 2.413 ;
     RECT  10.515 2.143 10.605 2.413 ;
     RECT  13.215 2.143 13.305 2.413 ;
     RECT  15.915 2.143 16.005 2.413 ;
     RECT  18.615 2.143 18.705 2.413 ;
     RECT  21.315 2.143 21.405 2.413 ;
     RECT  24.015 2.143 24.105 2.413 ;
     RECT  26.388 2.143 26.805 2.413 ;
     RECT  29.415 2.143 29.505 2.413 ;
     RECT  32.115 2.143 32.205 2.413 ;
     RECT  34.815 2.143 34.905 2.413 ;
     RECT  37.515 2.143 37.605 2.413 ;
     RECT  40.215 2.143 40.305 2.413 ;
     RECT  42.915 2.143 43.005 2.413 ;
     RECT  45.615 2.143 45.705 2.413 ;
     RECT  48.315 2.143 48.405 2.413 ;
     RECT  51.015 2.143 51.105 2.413 ;
     RECT  53.715 2.143 53.805 2.413 ;
     RECT  56.415 2.143 56.505 2.413 ;
     RECT  59.115 2.143 59.205 2.413 ;
     RECT  61.815 2.143 61.905 2.413 ;
     RECT  64.515 2.143 64.605 2.413 ;
     RECT  67.215 2.143 67.305 2.413 ;
     RECT  69.915 2.143 70.005 2.413 ;
     RECT  72.615 2.143 72.705 2.413 ;
     RECT  75.315 2.143 75.405 2.413 ;
     RECT  78.015 2.143 78.105 2.413 ;
     RECT  80.715 2.143 80.805 2.413 ;
     RECT  83.415 2.143 83.505 2.413 ;
     RECT  86.115 2.143 86.205 2.413 ;
     RECT  88.815 2.143 88.905 2.413 ;
     RECT  91.515 2.143 91.605 2.413 ;
     RECT  94.215 2.143 94.305 2.413 ;
     RECT  2.415 2.413 2.697 4.459 ;
     RECT  5.115 2.413 5.397 4.657 ;
     RECT  2.415 4.459 2.862 4.792 ;
     RECT  5.115 4.657 6.102 4.795 ;
     RECT  6.84 4.693 6.858 4.795 ;
     RECT  3.996 4.795 4.014 4.801 ;
     RECT  3.636 4.801 4.266 4.963 ;
     RECT  5.115 4.795 6.858 4.963 ;
     RECT  3.636 4.963 6.858 5.035 ;
     RECT  7.815 2.413 8.097 5.035 ;
     RECT  0.216 4.999 0.234 5.117 ;
     RECT  2.304 4.792 2.862 5.453 ;
     RECT  3.636 5.035 8.097 5.611 ;
     RECT  2.415 5.453 2.862 5.659 ;
     RECT  3.636 5.611 8.154 5.659 ;
     RECT  2.415 5.659 8.154 5.873 ;
     RECT  2.415 5.873 8.097 6.269 ;
     RECT  3.42 6.269 8.097 6.305 ;
     RECT  0.54 6.151 0.558 6.365 ;
     RECT  7.815 6.305 8.097 6.817 ;
     RECT  8.928 6.421 8.946 6.817 ;
     RECT  2.415 6.269 2.697 6.955 ;
     RECT  7.815 6.817 8.946 6.961 ;
     RECT  3.42 6.305 6.966 7.195 ;
     RECT  7.815 6.961 9.558 7.195 ;
     RECT  0.216 7.147 0.234 7.277 ;
     RECT  2.304 6.955 2.697 7.357 ;
     RECT  3.42 7.195 9.558 7.357 ;
     RECT  2.304 7.357 9.558 7.619 ;
     RECT  2.415 7.619 9.558 8.159 ;
     RECT  2.415 8.159 8.097 8.969 ;
     RECT  3.42 8.969 8.097 9.121 ;
     RECT  0.54 8.581 0.558 9.149 ;
     RECT  2.415 8.969 2.697 9.403 ;
     RECT  2.304 9.403 2.697 9.509 ;
     RECT  3.42 9.121 8.118 9.589 ;
     RECT  8.928 8.159 9.558 9.589 ;
     RECT  2.415 9.509 2.697 9.739 ;
     RECT  3.42 9.589 9.558 9.739 ;
     RECT  0.216 9.739 0.234 9.869 ;
     RECT  2.415 9.739 9.558 11.003 ;
     RECT  2.415 11.003 3.222 11.272 ;
     RECT  10.515 2.413 10.797 11.281 ;
     RECT  0.216 11.551 0.234 11.597 ;
     RECT  2.304 11.272 3.222 11.911 ;
     RECT  3.96 11.003 9.558 11.911 ;
     RECT  2.304 11.911 9.558 11.939 ;
     RECT  0.216 13.435 0.234 13.613 ;
     RECT  2.415 11.939 9.558 13.981 ;
     RECT  2.304 13.981 9.558 14.093 ;
     RECT  2.376 14.093 9.558 14.381 ;
     RECT  2.415 14.381 9.558 15.595 ;
     RECT  10.332 11.281 10.797 15.601 ;
     RECT  11.7 10.669 11.718 15.601 ;
     RECT  2.304 15.595 9.558 15.719 ;
     RECT  10.332 15.601 11.718 16.141 ;
     RECT  10.332 16.141 12.114 16.411 ;
     RECT  10.332 16.411 12.15 16.529 ;
     RECT  0.216 15.259 0.234 16.541 ;
     RECT  14.616 4.801 14.634 16.681 ;
     RECT  10.332 16.529 10.797 17.491 ;
     RECT  11.7 16.529 12.15 17.491 ;
     RECT  2.415 15.719 9.558 17.752 ;
     RECT  15.915 2.413 16.197 17.923 ;
     RECT  17.28 18.031 17.298 18.301 ;
     RECT  2.304 17.752 9.558 18.379 ;
     RECT  1.98 18.379 9.558 18.557 ;
     RECT  26.388 2.413 26.997 18.769 ;
     RECT  17.208 18.301 17.298 19.003 ;
     RECT  24.015 2.413 24.297 19.111 ;
     RECT  24.015 19.111 24.93 19.345 ;
     RECT  25.668 18.769 26.997 19.345 ;
     RECT  24.015 19.345 26.997 19.661 ;
     RECT  25.164 19.661 26.997 20.147 ;
     RECT  25.992 20.147 26.997 20.183 ;
     RECT  2.415 18.557 9.558 20.203 ;
     RECT  25.164 20.147 25.182 20.237 ;
     RECT  26.064 20.183 26.997 20.345 ;
     RECT  14.256 16.681 14.634 20.353 ;
     RECT  15.84 17.923 16.197 20.353 ;
     RECT  0.216 19.003 0.234 20.417 ;
     RECT  2.304 20.203 9.558 20.579 ;
     RECT  18.615 2.413 18.897 21.271 ;
     RECT  17.172 19.003 17.298 21.469 ;
     RECT  18.036 21.271 18.897 21.469 ;
     RECT  13.215 2.413 13.497 21.631 ;
     RECT  14.256 20.353 16.197 21.631 ;
     RECT  21.315 2.413 21.597 21.631 ;
     RECT  22.392 19.777 22.41 21.631 ;
     RECT  14.256 21.631 16.326 21.787 ;
     RECT  17.172 21.469 19.206 21.787 ;
     RECT  21.315 21.631 22.626 21.973 ;
     RECT  20.736 21.973 22.626 22.045 ;
     RECT  2.415 20.579 9.558 22.072 ;
     RECT  12.888 21.631 13.497 22.171 ;
     RECT  14.256 21.787 19.206 22.171 ;
     RECT  12.888 22.171 19.206 22.207 ;
     RECT  20.628 22.045 22.734 22.207 ;
     RECT  2.304 22.072 9.558 22.219 ;
     RECT  12.888 22.207 19.71 22.243 ;
     RECT  20.52 22.207 22.734 22.243 ;
     RECT  12.888 22.243 22.842 22.279 ;
     RECT  25.092 22.243 25.11 22.315 ;
     RECT  12.888 22.279 23.094 22.351 ;
     RECT  24.015 19.661 24.297 22.351 ;
     RECT  1.98 22.219 9.558 22.397 ;
     RECT  25.056 22.315 25.11 22.513 ;
     RECT  0.252 22.699 0.27 22.739 ;
     RECT  25.056 22.513 25.254 22.747 ;
     RECT  12.888 22.351 24.297 22.795 ;
     RECT  25.056 22.747 25.542 22.795 ;
     RECT  10.332 17.491 12.15 22.819 ;
     RECT  12.888 22.795 25.542 22.819 ;
     RECT  10.332 22.819 25.542 23.279 ;
     RECT  10.332 23.279 25.434 23.423 ;
     RECT  10.332 23.423 25.254 24.169 ;
     RECT  2.415 22.397 9.558 24.235 ;
     RECT  10.332 24.169 25.29 24.331 ;
     RECT  0.216 24.523 0.234 24.701 ;
     RECT  10.332 24.331 25.506 24.781 ;
     RECT  26.715 20.345 26.997 24.781 ;
     RECT  2.304 24.235 9.558 24.899 ;
     RECT  2.415 24.899 9.558 26.221 ;
     RECT  10.332 24.781 26.997 26.833 ;
     RECT  10.332 26.833 27.126 27.163 ;
     RECT  10.332 27.163 27.198 27.301 ;
     RECT  10.332 27.301 27.594 27.481 ;
     RECT  10.332 27.481 28.17 27.643 ;
     RECT  2.304 26.221 9.558 27.677 ;
     RECT  10.332 27.643 28.494 27.751 ;
     RECT  29.415 2.413 29.697 27.751 ;
     RECT  10.332 27.751 29.697 28.021 ;
     RECT  2.415 27.677 9.558 28.381 ;
     RECT  10.332 28.021 30.078 28.381 ;
     RECT  2.415 28.381 30.078 28.555 ;
     RECT  2.304 28.555 30.078 29.101 ;
     RECT  2.304 29.101 30.258 29.179 ;
     RECT  32.115 2.413 32.397 29.227 ;
     RECT  2.268 29.179 30.258 29.461 ;
     RECT  2.268 29.461 30.33 29.489 ;
     RECT  31.392 29.227 32.397 29.839 ;
     RECT  31.176 29.839 32.397 29.911 ;
     RECT  2.415 29.489 30.33 30.271 ;
     RECT  31.068 29.911 32.397 30.271 ;
     RECT  2.415 30.271 32.397 30.379 ;
     RECT  34.815 2.413 35.097 31.189 ;
     RECT  2.304 30.379 32.397 31.801 ;
     RECT  33.3 31.621 33.318 31.801 ;
     RECT  2.304 31.801 33.642 31.891 ;
     RECT  2.304 31.891 33.75 31.991 ;
     RECT  2.304 31.991 33.642 33.067 ;
     RECT  34.815 31.189 35.154 33.313 ;
     RECT  34.776 33.313 35.154 33.385 ;
     RECT  34.776 33.385 35.658 33.421 ;
     RECT  2.304 33.067 33.858 33.449 ;
     RECT  33.768 33.449 33.858 33.583 ;
     RECT  34.776 33.421 36.162 33.583 ;
     RECT  2.304 33.449 32.922 33.845 ;
     RECT  33.768 33.583 36.162 33.881 ;
     RECT  2.415 33.845 32.922 34.231 ;
     RECT  33.768 33.881 35.946 34.231 ;
     RECT  37.515 2.413 37.797 34.429 ;
     RECT  2.415 34.231 35.946 34.627 ;
     RECT  36.792 34.429 37.797 34.627 ;
     RECT  2.415 34.627 37.797 35.035 ;
     RECT  2.304 35.035 37.797 35.195 ;
     RECT  36.684 35.195 37.797 35.311 ;
     RECT  36.684 35.311 37.962 35.509 ;
     RECT  2.304 35.195 35.946 35.699 ;
     RECT  36.684 35.509 38.07 35.707 ;
     RECT  36.684 35.707 38.25 35.743 ;
     RECT  2.415 35.699 35.946 36.121 ;
     RECT  36.684 35.743 38.898 36.121 ;
     RECT  40.215 2.413 40.497 36.517 ;
     RECT  2.415 36.121 38.898 36.589 ;
     RECT  40.032 36.517 40.497 36.589 ;
     RECT  2.415 36.589 40.497 36.751 ;
     RECT  2.415 36.751 40.59 36.823 ;
     RECT  2.415 36.823 40.626 36.931 ;
     RECT  2.415 36.931 40.662 37.021 ;
     RECT  41.508 36.661 41.526 37.021 ;
     RECT  2.415 37.021 41.526 37.201 ;
     RECT  2.415 37.201 41.67 37.483 ;
     RECT  42.915 2.413 43.197 37.705 ;
     RECT  2.304 37.483 41.67 37.859 ;
     RECT  2.415 37.859 41.67 37.867 ;
     RECT  42.624 37.705 43.197 37.867 ;
     RECT  0.216 37.021 0.234 38.141 ;
     RECT  2.415 37.867 43.197 38.281 ;
     RECT  2.415 38.281 43.722 38.641 ;
     RECT  2.415 38.641 43.974 38.731 ;
     RECT  2.376 38.731 43.974 38.765 ;
     RECT  2.376 38.765 42.066 38.821 ;
     RECT  42.876 38.765 43.974 38.821 ;
     RECT  2.304 38.821 42.066 38.975 ;
     RECT  42.876 38.821 44.082 38.983 ;
     RECT  44.856 38.677 44.874 38.983 ;
     RECT  42.876 38.983 44.874 39.245 ;
     RECT  2.304 38.975 37.89 39.317 ;
     RECT  38.628 38.975 42.066 39.757 ;
     RECT  42.876 39.245 44.082 39.757 ;
     RECT  44.856 39.245 44.874 39.883 ;
     RECT  45.615 2.413 45.897 39.883 ;
     RECT  38.628 39.757 44.082 40.064 ;
     RECT  37.152 39.317 37.89 40.135 ;
     RECT  2.304 39.317 36.09 40.171 ;
     RECT  37.116 40.135 37.89 40.171 ;
     RECT  38.628 40.064 41.85 40.171 ;
     RECT  42.588 40.064 44.082 40.171 ;
     RECT  44.856 39.883 45.897 40.171 ;
     RECT  42.588 40.171 45.897 40.801 ;
     RECT  2.304 40.171 41.85 40.981 ;
     RECT  42.588 40.801 46.566 40.981 ;
     RECT  2.304 40.981 46.566 41.143 ;
     RECT  2.304 41.143 46.926 41.251 ;
     RECT  2.304 41.251 47.142 41.449 ;
     RECT  48.315 2.413 48.597 41.449 ;
     RECT  2.304 41.449 48.597 42.179 ;
     RECT  2.415 42.179 48.597 42.331 ;
     RECT  0.252 42.421 0.27 42.427 ;
     RECT  2.415 42.331 49.23 42.593 ;
     RECT  0.216 42.427 0.27 42.797 ;
     RECT  2.415 42.593 48.69 43.051 ;
     RECT  0.216 42.797 0.234 43.373 ;
     RECT  2.304 43.051 48.69 43.375 ;
     RECT  2.304 43.375 48.87 43.681 ;
     RECT  2.304 43.681 49.086 43.771 ;
     RECT  51.015 2.413 51.297 44.149 ;
     RECT  2.304 43.771 49.194 44.299 ;
     RECT  2.268 44.299 49.194 44.339 ;
     RECT  2.304 44.339 49.194 44.341 ;
     RECT  2.304 44.341 49.338 44.347 ;
     RECT  2.304 44.347 49.59 44.645 ;
     RECT  2.304 44.645 49.122 44.957 ;
     RECT  2.412 44.957 49.122 45.832 ;
     RECT  2.304 45.832 49.122 46.381 ;
     RECT  2.304 46.381 49.302 46.921 ;
     RECT  2.304 46.921 49.374 47.659 ;
     RECT  2.304 47.659 49.41 47.731 ;
     RECT  2.304 47.731 49.59 48.001 ;
     RECT  50.58 44.149 51.297 48.001 ;
     RECT  2.304 48.001 51.297 48.271 ;
     RECT  2.304 48.271 51.822 48.703 ;
     RECT  2.304 48.703 52.362 48.901 ;
     RECT  53.715 2.413 53.997 49.081 ;
     RECT  54.828 48.811 54.846 49.081 ;
     RECT  2.304 48.901 52.614 49.243 ;
     RECT  2.304 49.243 52.758 49.351 ;
     RECT  53.715 49.081 54.846 49.351 ;
     RECT  2.304 49.351 54.846 51.241 ;
     RECT  2.304 51.241 55.242 51.439 ;
     RECT  56.415 2.413 56.697 51.439 ;
     RECT  61.815 2.413 62.097 52.825 ;
     RECT  2.304 51.439 56.697 52.861 ;
     RECT  59.115 2.413 59.397 52.861 ;
     RECT  59.115 52.861 60.102 52.939 ;
     RECT  61.704 52.825 62.097 52.939 ;
     RECT  2.304 52.861 57.222 52.979 ;
     RECT  59.115 52.939 62.097 52.981 ;
     RECT  59.115 52.981 62.514 53.131 ;
     RECT  2.415 52.979 57.222 53.293 ;
     RECT  2.415 53.293 57.33 53.491 ;
     RECT  59.115 53.131 63.486 53.563 ;
     RECT  0.216 52.411 0.234 53.597 ;
     RECT  59.115 53.563 63.558 53.635 ;
     RECT  58.428 53.635 63.558 53.789 ;
     RECT  61.524 53.789 63.558 53.869 ;
     RECT  64.515 2.413 64.797 53.869 ;
     RECT  2.415 53.491 57.654 54.139 ;
     RECT  58.428 53.789 60.75 54.445 ;
     RECT  61.524 53.869 64.797 54.445 ;
     RECT  2.304 54.139 57.654 54.481 ;
     RECT  58.392 54.445 60.75 54.481 ;
     RECT  61.524 54.445 65.394 54.481 ;
     RECT  61.524 54.481 65.538 54.679 ;
     RECT  66.312 54.481 66.33 54.679 ;
     RECT  2.304 54.481 60.75 54.715 ;
     RECT  61.524 54.679 66.33 54.715 ;
     RECT  2.304 54.715 66.33 54.869 ;
     RECT  2.304 54.869 65.538 55.139 ;
     RECT  2.412 55.139 65.538 55.421 ;
     RECT  2.415 55.421 65.538 56.299 ;
     RECT  2.412 56.299 65.61 56.489 ;
     RECT  2.412 56.489 57.87 56.497 ;
     RECT  2.304 56.497 57.87 56.569 ;
     RECT  2.268 56.569 57.87 56.669 ;
     RECT  0.216 56.827 0.234 56.957 ;
     RECT  67.215 2.413 67.497 57.109 ;
     RECT  58.752 56.489 65.61 57.181 ;
     RECT  58.752 57.181 66.042 57.271 ;
     RECT  2.304 56.669 57.87 57.299 ;
     RECT  2.415 57.299 57.87 57.379 ;
     RECT  58.716 57.271 66.042 57.451 ;
     RECT  58.716 57.451 66.294 57.541 ;
     RECT  67.176 57.109 67.497 57.541 ;
     RECT  2.415 57.379 57.906 57.59 ;
     RECT  58.716 57.541 67.497 57.59 ;
     RECT  2.415 57.59 67.497 58.081 ;
     RECT  2.415 58.081 67.554 58.171 ;
     RECT  0.216 58.795 0.234 58.973 ;
     RECT  2.304 58.171 67.554 59.341 ;
     RECT  2.304 59.341 67.842 59.467 ;
     RECT  68.976 59.611 68.994 59.729 ;
     RECT  2.304 59.467 68.13 59.881 ;
     RECT  68.94 59.809 68.958 59.881 ;
     RECT  2.304 59.881 68.958 59.999 ;
     RECT  2.304 59.999 68.85 60.035 ;
     RECT  2.304 60.035 68.562 60.077 ;
     RECT  2.376 60.077 68.562 60.955 ;
     RECT  2.304 60.955 68.562 61.051 ;
     RECT  2.304 61.051 68.598 61.699 ;
     RECT  2.304 61.699 69.174 61.771 ;
     RECT  69.915 2.413 70.197 61.771 ;
     RECT  2.304 61.771 70.197 63.589 ;
     RECT  2.304 63.589 70.254 63.779 ;
     RECT  0.216 64.171 0.234 64.397 ;
     RECT  2.415 63.779 70.254 64.925 ;
     RECT  2.415 64.925 59.994 64.931 ;
     RECT  2.415 64.931 59.958 64.939 ;
     RECT  71.532 63.931 71.55 65.011 ;
     RECT  72.615 2.413 72.897 65.137 ;
     RECT  71.388 65.011 71.55 65.209 ;
     RECT  60.768 64.925 70.254 65.281 ;
     RECT  70.992 65.209 71.55 65.281 ;
     RECT  60.768 65.281 71.658 65.435 ;
     RECT  0.216 65.275 0.234 65.453 ;
     RECT  60.768 65.435 70.65 65.669 ;
     RECT  60.768 65.669 70.542 65.813 ;
     RECT  2.304 64.939 59.958 65.947 ;
     RECT  60.768 65.813 70.434 65.947 ;
     RECT  71.388 65.435 71.658 66.011 ;
     RECT  2.304 65.947 70.434 66.083 ;
     RECT  0.54 66.091 0.558 66.221 ;
     RECT  2.34 66.083 70.434 66.901 ;
     RECT  71.388 66.011 71.406 66.901 ;
     RECT  0.252 66.763 0.27 67.133 ;
     RECT  2.34 66.901 71.802 67.261 ;
     RECT  2.304 67.261 71.802 67.703 ;
     RECT  0.216 67.579 0.234 67.757 ;
     RECT  2.304 67.703 71.514 68.717 ;
     RECT  2.415 68.717 71.514 68.755 ;
     RECT  2.415 68.755 71.838 69.061 ;
     RECT  72.615 65.137 73.134 69.061 ;
     RECT  2.415 69.061 73.134 69.251 ;
     RECT  2.415 69.251 71.802 69.595 ;
     RECT  2.304 69.595 71.802 69.899 ;
     RECT  2.34 69.899 71.802 69.917 ;
     RECT  2.415 69.917 71.802 70.097 ;
     RECT  0.216 70.219 0.234 70.349 ;
     RECT  72.615 69.251 73.134 70.609 ;
     RECT  2.415 70.097 71.586 70.771 ;
     RECT  72.468 70.609 73.134 70.807 ;
     RECT  2.304 70.771 71.586 70.951 ;
     RECT  72.468 70.807 73.458 70.951 ;
     RECT  2.304 70.951 73.458 71.491 ;
     RECT  75.315 2.413 75.597 71.725 ;
     RECT  75.315 71.725 75.69 71.761 ;
     RECT  2.304 71.491 73.71 71.851 ;
     RECT  74.484 71.491 74.502 71.851 ;
     RECT  75.315 71.761 75.834 71.851 ;
     RECT  2.304 71.851 75.834 72.031 ;
     RECT  0.216 71.947 0.234 72.077 ;
     RECT  2.304 72.031 76.374 72.157 ;
     RECT  2.304 72.157 76.626 72.265 ;
     RECT  78.015 2.413 78.297 72.265 ;
     RECT  77.58 72.265 78.297 72.301 ;
     RECT  2.304 72.265 76.698 72.419 ;
     RECT  77.58 72.301 78.354 72.571 ;
     RECT  1.152 72.523 1.17 72.701 ;
     RECT  77.508 72.571 78.354 72.769 ;
     RECT  2.415 72.419 76.698 72.931 ;
     RECT  77.508 72.769 78.93 72.931 ;
     RECT  2.415 72.931 78.93 73.111 ;
     RECT  79.92 72.967 79.938 73.229 ;
     RECT  2.415 73.111 79.002 73.381 ;
     RECT  79.776 73.381 79.866 73.499 ;
     RECT  79.776 73.499 79.794 73.535 ;
     RECT  0.54 73.471 0.558 73.613 ;
     RECT  2.304 73.381 79.002 74.059 ;
     RECT  1.98 74.059 79.002 74.237 ;
     RECT  2.304 74.237 79.002 74.573 ;
     RECT  2.412 74.573 79.002 74.861 ;
     RECT  2.415 74.861 79.002 74.965 ;
     RECT  2.415 74.965 79.362 75.505 ;
     RECT  2.415 75.505 79.434 75.541 ;
     RECT  2.415 75.541 79.866 75.695 ;
     RECT  80.715 2.413 80.997 76.009 ;
     RECT  2.415 75.695 79.434 76.072 ;
     RECT  0.216 76.363 0.234 76.493 ;
     RECT  2.304 76.072 79.434 76.555 ;
     RECT  1.98 76.555 79.434 76.585 ;
     RECT  1.98 76.585 79.542 76.733 ;
     RECT  2.376 76.733 79.542 76.891 ;
     RECT  80.352 76.009 80.997 76.891 ;
     RECT  2.376 76.891 80.997 77.423 ;
     RECT  2.415 77.423 80.997 77.855 ;
     RECT  0.54 76.513 0.558 77.933 ;
     RECT  2.415 77.855 11.718 78.232 ;
     RECT  12.456 77.855 80.997 78.241 ;
     RECT  2.304 78.232 11.718 78.893 ;
     RECT  12.456 78.241 81.054 79.681 ;
     RECT  2.415 78.893 11.718 79.771 ;
     RECT  12.456 79.681 81.234 80.095 ;
     RECT  12.456 80.095 81.27 80.131 ;
     RECT  12.456 80.131 81.414 80.221 ;
     RECT  82.188 80.131 82.206 80.221 ;
     RECT  12.456 80.221 82.206 80.249 ;
     RECT  17.208 80.249 82.206 80.285 ;
     RECT  17.208 80.285 81.99 80.321 ;
     RECT  17.208 80.321 81.486 80.555 ;
     RECT  2.304 79.771 11.718 80.957 ;
     RECT  2.304 80.957 2.697 81.059 ;
     RECT  17.28 80.555 81.414 81.715 ;
     RECT  17.28 81.715 81.594 81.751 ;
     RECT  83.415 2.413 83.697 81.751 ;
     RECT  3.528 80.957 11.718 81.877 ;
     RECT  0.54 81.409 0.558 81.965 ;
     RECT  83.376 81.751 84.006 81.985 ;
     RECT  2.415 81.059 2.697 82.021 ;
     RECT  3.42 81.877 11.718 82.021 ;
     RECT  17.28 81.751 82.35 82.111 ;
     RECT  17.28 82.111 82.602 82.147 ;
     RECT  83.34 81.985 84.006 82.147 ;
     RECT  17.28 82.147 84.006 82.175 ;
     RECT  82.584 82.175 84.006 82.409 ;
     RECT  82.656 82.409 84.006 82.445 ;
     RECT  82.764 82.445 84.006 82.453 ;
     RECT  0.216 82.459 0.234 82.589 ;
     RECT  2.415 82.021 11.718 82.699 ;
     RECT  1.98 82.699 11.718 82.877 ;
     RECT  82.764 82.453 84.078 83.227 ;
     RECT  12.456 80.249 16.434 83.263 ;
     RECT  17.28 82.175 81.666 83.263 ;
     RECT  12.456 83.263 81.666 83.299 ;
     RECT  82.692 83.227 84.078 83.299 ;
     RECT  2.304 82.877 11.718 83.501 ;
     RECT  12.456 83.299 84.078 83.605 ;
     RECT  12.456 83.605 84.402 83.633 ;
     RECT  17.172 83.633 84.402 83.669 ;
     RECT  86.115 2.413 86.397 83.767 ;
     RECT  12.456 83.633 16.434 84.415 ;
     RECT  17.28 83.669 84.402 84.415 ;
     RECT  12.456 84.415 84.402 84.685 ;
     RECT  85.428 83.767 86.397 84.685 ;
     RECT  2.415 83.501 11.718 84.712 ;
     RECT  2.304 84.712 11.718 84.749 ;
     RECT  12.456 84.685 86.397 84.749 ;
     RECT  0.216 85.003 0.234 85.469 ;
     RECT  17.28 84.749 86.397 85.483 ;
     RECT  2.415 84.749 11.718 85.621 ;
     RECT  2.304 85.621 11.718 85.661 ;
     RECT  17.244 85.483 86.397 85.919 ;
     RECT  2.415 85.661 11.718 86.701 ;
     RECT  17.28 85.919 86.397 86.729 ;
     RECT  2.304 86.701 11.718 87.269 ;
     RECT  0.54 87.043 0.558 87.499 ;
     RECT  88.815 2.413 89.097 87.889 ;
     RECT  2.34 87.269 11.718 88.115 ;
     RECT  0.216 87.499 0.558 88.445 ;
     RECT  88.815 87.889 89.73 88.771 ;
     RECT  0.54 88.445 0.558 89.069 ;
     RECT  17.28 86.729 22.59 89.131 ;
     RECT  23.364 86.729 86.397 89.131 ;
     RECT  87.444 86.269 87.462 89.311 ;
     RECT  88.524 88.771 89.73 89.311 ;
     RECT  2.415 88.115 11.718 89.323 ;
     RECT  2.304 89.323 11.718 89.429 ;
     RECT  17.28 89.131 86.397 89.515 ;
     RECT  0.216 89.515 0.234 89.693 ;
     RECT  2.412 89.429 11.718 89.969 ;
     RECT  1.152 89.947 1.17 90.013 ;
     RECT  0.54 90.013 1.17 90.077 ;
     RECT  17.28 89.515 86.598 90.121 ;
     RECT  87.444 89.311 89.73 90.121 ;
     RECT  12.456 84.749 16.434 90.283 ;
     RECT  17.28 90.121 89.73 90.283 ;
     RECT  0.54 90.077 0.558 90.317 ;
     RECT  12.456 90.283 89.73 90.661 ;
     RECT  2.415 89.969 11.718 90.859 ;
     RECT  12.456 90.661 90.162 91.049 ;
     RECT  87.444 91.049 90.162 91.165 ;
     RECT  1.152 91.195 1.17 91.373 ;
     RECT  2.304 90.859 11.718 91.483 ;
     RECT  1.98 91.483 11.718 91.613 ;
     RECT  12.456 91.049 86.397 91.769 ;
     RECT  2.304 91.613 11.718 91.931 ;
     RECT  0.216 91.819 0.234 91.997 ;
     RECT  23.256 91.769 86.397 92.129 ;
     RECT  2.304 91.931 8.91 92.141 ;
     RECT  87.444 91.165 90.378 92.245 ;
     RECT  91.515 2.413 91.797 92.245 ;
     RECT  2.415 92.141 8.91 92.285 ;
     RECT  23.256 92.129 79.434 92.285 ;
     RECT  12.456 91.769 22.518 92.309 ;
     RECT  9.648 91.931 11.718 92.395 ;
     RECT  12.456 92.309 22.374 92.395 ;
     RECT  23.364 92.285 79.434 92.399 ;
     RECT  9.648 92.395 22.374 92.669 ;
     RECT  87.444 92.245 91.797 92.785 ;
     RECT  80.172 92.129 86.397 92.875 ;
     RECT  87.444 92.785 92.466 92.875 ;
     RECT  2.415 92.285 2.697 93.055 ;
     RECT  3.492 92.285 8.91 93.055 ;
     RECT  23.4 92.399 79.434 93.055 ;
     RECT  80.172 92.875 92.466 93.055 ;
     RECT  2.415 93.055 8.91 93.355 ;
     RECT  2.304 93.355 8.91 93.479 ;
     RECT  2.415 93.479 8.91 93.515 ;
     RECT  3.888 93.515 8.91 93.631 ;
     RECT  9.648 92.669 11.718 93.631 ;
     RECT  94.215 2.413 94.497 93.829 ;
     RECT  0.216 93.643 0.234 94.019 ;
     RECT  12.492 92.669 22.374 94.075 ;
     RECT  23.4 93.055 92.466 94.075 ;
     RECT  12.492 94.075 92.466 94.171 ;
     RECT  93.492 93.829 94.497 94.171 ;
     RECT  3.888 93.631 11.718 94.289 ;
     RECT  2.415 93.515 3.078 94.441 ;
     RECT  4.536 94.289 11.718 94.441 ;
     RECT  12.492 94.171 94.497 94.441 ;
     RECT  2.415 94.441 3.69 94.595 ;
     RECT  4.536 94.441 94.497 94.631 ;
     RECT  0.54 94.531 0.558 94.637 ;
     RECT  5.115 94.631 94.497 94.829 ;
     RECT  3.672 94.595 3.69 95.009 ;
     RECT  5.115 94.829 93.222 95.369 ;
     RECT  5.115 95.369 92.862 95.521 ;
     RECT  4.86 95.521 92.862 96.061 ;
     RECT  4.788 96.061 92.862 96.179 ;
     RECT  2.415 94.595 2.697 96.947 ;
     RECT  94.215 94.829 94.497 96.947 ;
     RECT  4.788 96.179 92.718 96.989 ;
     RECT  4.788 96.989 92.43 97.105 ;
     RECT  2.415 96.947 2.505 97.217 ;
     RECT  4.464 97.105 92.43 97.217 ;
     RECT  94.215 96.947 94.305 97.217 ;
     RECT  4.464 97.217 42.894 98.581 ;
     RECT  43.632 97.217 92.43 98.581 ;
     RECT  4.464 98.581 92.43 99.228 ;
    LAYER M4 ;
     RECT  0.156 4.464 2.408 94.92 ;
     RECT  2.408 2.148 2.512 97.212 ;
     RECT  2.512 2.418 2.704 96.942 ;
     RECT  2.704 45.216 2.765 45.576 ;
     RECT  2.704 46.848 2.801 54.456 ;
     RECT  2.704 33.936 2.837 44.232 ;
     RECT  2.704 55.728 2.837 56.856 ;
     RECT  2.704 4.464 2.873 19.608 ;
     RECT  2.704 31.968 2.909 32.52 ;
     RECT  2.704 57.888 2.945 65.448 ;
     RECT  2.837 33.936 3.125 35.832 ;
     RECT  2.837 37.008 3.436 44.232 ;
     RECT  2.704 66.528 3.484 94.92 ;
     RECT  2.945 57.888 3.485 59.4 ;
     RECT  2.873 4.8 3.701 11.208 ;
     RECT  3.484 90 3.701 94.92 ;
     RECT  2.837 56.352 3.733 56.856 ;
     RECT  3.485 57.888 3.733 58.728 ;
     RECT  2.909 32.496 3.769 32.52 ;
     RECT  3.436 40.944 3.805 44.232 ;
     RECT  2.765 45.312 3.805 45.576 ;
     RECT  3.436 37.008 3.809 39.96 ;
     RECT  3.125 34.656 3.829 35.832 ;
     RECT  3.809 37.008 3.829 37.608 ;
     RECT  3.809 38.832 3.881 39.96 ;
     RECT  2.704 20.832 3.913 22.248 ;
     RECT  2.704 23.328 3.913 24.696 ;
     RECT  2.873 12.192 3.917 19.608 ;
     RECT  3.701 7.68 3.949 11.208 ;
     RECT  3.917 12.192 3.949 15 ;
     RECT  3.913 20.832 3.949 24.696 ;
     RECT  2.704 25.776 3.949 25.8 ;
     RECT  3.805 40.944 3.949 45.576 ;
     RECT  2.801 46.848 3.949 49.08 ;
     RECT  2.801 50.112 3.949 54.456 ;
     RECT  2.945 60.432 3.949 65.448 ;
     RECT  3.829 34.656 3.953 37.608 ;
     RECT  3.949 20.832 3.98 25.8 ;
     RECT  2.704 26.928 3.98 30.744 ;
     RECT  3.701 4.8 4.025 6.696 ;
     RECT  3.484 66.528 4.025 88.968 ;
     RECT  3.733 56.352 4.057 58.728 ;
     RECT  3.949 59.856 4.057 65.448 ;
     RECT  4.025 66.528 4.057 80.568 ;
     RECT  3.98 20.832 4.067 30.744 ;
     RECT  3.769 32.496 4.129 33.48 ;
     RECT  4.057 59.856 4.133 80.568 ;
     RECT  4.129 31.776 4.237 33.48 ;
     RECT  3.953 34.656 4.237 37.08 ;
     RECT  3.949 40.944 4.237 49.08 ;
     RECT  3.949 50.112 4.237 54.696 ;
     RECT  4.067 27.312 4.309 30.744 ;
     RECT  4.237 31.776 4.309 37.08 ;
     RECT  4.057 56.304 4.417 58.728 ;
     RECT  4.025 81.648 4.489 88.968 ;
     RECT  3.701 90 4.489 94.392 ;
     RECT  3.917 16.08 4.525 19.608 ;
     RECT  4.067 20.832 4.525 25.992 ;
     RECT  4.237 40.944 4.561 54.696 ;
     RECT  4.417 55.776 4.645 58.728 ;
     RECT  4.133 59.856 4.645 75.48 ;
     RECT  4.561 40.944 4.669 54.792 ;
     RECT  4.645 55.776 4.669 75.48 ;
     RECT  3.881 38.928 4.993 39.96 ;
     RECT  4.025 5.04 5.108 6.696 ;
     RECT  3.949 7.68 5.108 15 ;
     RECT  4.525 16.08 5.108 25.992 ;
     RECT  4.309 27.312 5.108 37.08 ;
     RECT  4.993 38.256 5.108 39.96 ;
     RECT  4.669 40.944 5.108 75.48 ;
     RECT  4.133 76.512 5.108 80.568 ;
     RECT  4.489 81.648 5.108 94.392 ;
     RECT  4.741 96.912 5.108 96.936 ;
     RECT  5.108 2.148 5.212 97.212 ;
     RECT  5.212 2.418 5.365 97.212 ;
     RECT  5.365 2.418 5.404 97.32 ;
     RECT  5.404 81.792 5.465 94.392 ;
     RECT  5.404 96.912 5.465 97.32 ;
     RECT  5.404 12.528 5.555 15 ;
     RECT  5.465 85.44 5.555 94.392 ;
     RECT  5.404 42.144 5.644 62.568 ;
     RECT  5.644 42.192 5.645 62.568 ;
     RECT  5.555 85.44 5.717 91.992 ;
     RECT  5.717 89.952 5.753 91.992 ;
     RECT  5.404 4.8 5.933 11.544 ;
     RECT  5.465 81.792 5.987 84.36 ;
     RECT  5.933 4.8 6.005 7.992 ;
     RECT  5.933 9.072 6.005 11.544 ;
     RECT  5.645 42.192 6.005 62.472 ;
     RECT  5.404 17.904 6.041 19.896 ;
     RECT  5.465 96.912 6.149 96.936 ;
     RECT  5.404 34.896 6.323 41.112 ;
     RECT  5.404 64.656 6.397 80.568 ;
     RECT  5.555 93.024 6.397 94.392 ;
     RECT  5.987 82.224 6.433 84.36 ;
     RECT  5.717 85.44 6.433 88.92 ;
     RECT  6.005 11.52 6.437 11.544 ;
     RECT  5.404 21.12 6.545 33.624 ;
     RECT  6.005 9.072 6.563 10.488 ;
     RECT  6.005 42.192 6.563 44.952 ;
     RECT  5.404 16.032 6.577 16.536 ;
     RECT  5.753 90.048 6.577 91.992 ;
     RECT  6.397 93.024 6.577 94.68 ;
     RECT  6.545 27.888 6.613 33.624 ;
     RECT  6.323 34.896 6.613 35.016 ;
     RECT  6.005 4.8 6.653 5.256 ;
     RECT  6.005 6.672 6.653 7.992 ;
     RECT  6.565 97.152 6.653 97.176 ;
     RECT  6.005 46.272 6.659 62.472 ;
     RECT  6.545 21.12 6.689 26.76 ;
     RECT  6.613 27.888 6.689 35.016 ;
     RECT  6.041 17.904 6.716 19.464 ;
     RECT  5.404 63.6 6.721 63.624 ;
     RECT  6.689 22.08 6.725 26.76 ;
     RECT  6.659 47.952 6.757 62.472 ;
     RECT  6.721 63.552 6.757 63.624 ;
     RECT  6.563 9.072 6.797 10.344 ;
     RECT  6.716 17.616 6.803 19.464 ;
     RECT  6.716 20.592 6.803 20.616 ;
     RECT  6.725 22.08 6.803 25.176 ;
     RECT  6.803 22.752 6.833 25.176 ;
     RECT  6.757 47.952 6.937 63.624 ;
     RECT  6.397 64.656 6.937 81.048 ;
     RECT  5.555 12.528 7.073 12.84 ;
     RECT  5.555 13.872 7.073 15 ;
     RECT  6.433 82.224 7.081 88.92 ;
     RECT  6.577 90.048 7.081 94.68 ;
     RECT  7.073 12.528 7.093 15 ;
     RECT  6.577 15.984 7.093 16.536 ;
     RECT  6.653 5.232 7.117 5.256 ;
     RECT  6.323 36.336 7.189 41.112 ;
     RECT  6.563 42.192 7.189 42.6 ;
     RECT  6.659 46.272 7.261 46.824 ;
     RECT  7.189 36.336 7.381 42.6 ;
     RECT  7.053 11.376 7.441 11.4 ;
     RECT  7.093 12.528 7.441 16.536 ;
     RECT  6.689 29.616 7.477 35.016 ;
     RECT  7.381 36.048 7.477 42.6 ;
     RECT  6.563 43.68 7.477 44.952 ;
     RECT  6.797 9.072 7.58 9.096 ;
     RECT  7.261 46.224 7.669 46.824 ;
     RECT  6.937 47.952 7.669 81.048 ;
     RECT  7.141 96.912 7.765 96.936 ;
     RECT  7.117 5.232 7.808 5.64 ;
     RECT  6.653 6.672 7.808 7.224 ;
     RECT  7.58 8.976 7.808 9.096 ;
     RECT  6.797 10.32 7.808 10.344 ;
     RECT  7.441 11.376 7.808 16.536 ;
     RECT  6.803 17.904 7.808 19.464 ;
     RECT  6.833 22.752 7.808 24.552 ;
     RECT  6.725 26.208 7.808 26.76 ;
     RECT  6.689 27.888 7.808 28.488 ;
     RECT  7.477 29.616 7.808 42.6 ;
     RECT  7.477 43.68 7.808 45 ;
     RECT  7.669 46.224 7.808 81.048 ;
     RECT  7.081 82.224 7.808 94.68 ;
     RECT  7.765 96.912 7.808 97.368 ;
     RECT  7.808 2.148 7.912 97.368 ;
     RECT  7.912 2.418 7.985 97.368 ;
     RECT  7.985 2.418 8.104 96.942 ;
     RECT  8.104 74.4 8.129 79.8 ;
     RECT  8.104 82.416 8.129 94.392 ;
     RECT  8.104 15.984 8.165 16.008 ;
     RECT  8.104 43.872 8.201 73.368 ;
     RECT  8.104 28.176 8.237 28.44 ;
     RECT  8.201 50.064 8.237 73.368 ;
     RECT  8.237 50.064 8.243 73.32 ;
     RECT  8.129 79.776 8.243 79.8 ;
     RECT  8.104 23.568 8.273 23.64 ;
     RECT  8.129 82.416 8.273 91.704 ;
     RECT  8.273 82.656 8.281 91.704 ;
     RECT  8.281 82.656 8.309 84.696 ;
     RECT  8.273 23.616 8.345 23.64 ;
     RECT  8.309 82.656 8.381 83.064 ;
     RECT  8.381 82.752 8.387 83.064 ;
     RECT  8.281 85.968 8.387 91.704 ;
     RECT  8.129 74.4 8.489 78.648 ;
     RECT  8.201 43.872 8.531 49.08 ;
     RECT  8.531 46.176 8.813 49.08 ;
     RECT  8.104 29.664 8.819 42.6 ;
     RECT  8.129 92.88 8.819 94.392 ;
     RECT  8.819 33.6 8.849 42.6 ;
     RECT  8.243 50.064 8.921 63.624 ;
     RECT  8.921 52.272 9.029 63.624 ;
     RECT  8.819 93.072 9.029 94.392 ;
     RECT  8.104 96.912 9.052 96.936 ;
     RECT  8.104 9.072 9.107 9.096 ;
     RECT  8.243 64.656 9.107 73.32 ;
     RECT  8.819 29.664 9.137 32.472 ;
     RECT  8.921 50.064 9.137 51.288 ;
     RECT  8.489 74.4 9.148 78.456 ;
     RECT  8.849 33.6 9.173 38.76 ;
     RECT  9.137 50.784 9.173 51.288 ;
     RECT  9.173 33.696 9.209 38.76 ;
     RECT  8.813 46.464 9.241 49.08 ;
     RECT  9.241 46.464 9.281 49.8 ;
     RECT  8.387 82.752 9.349 83.016 ;
     RECT  8.309 84.144 9.349 84.696 ;
     RECT  9.029 57.408 9.385 63.624 ;
     RECT  9.107 64.656 9.385 66.888 ;
     RECT  8.387 86.016 9.395 91.704 ;
     RECT  9.281 46.56 9.425 49.8 ;
     RECT  9.349 80.88 9.533 80.904 ;
     RECT  9.395 86.016 9.533 88.728 ;
     RECT  9.395 89.76 9.533 91.704 ;
     RECT  8.849 39.888 9.709 42.6 ;
     RECT  8.531 43.872 9.889 45 ;
     RECT  9.029 52.272 10.069 56.328 ;
     RECT  9.385 57.408 10.069 66.888 ;
     RECT  9.349 82.608 10.069 83.016 ;
     RECT  9.349 84.144 10.069 84.936 ;
     RECT  9.589 97.152 10.105 97.176 ;
     RECT  10.069 52.272 10.141 66.888 ;
     RECT  9.107 68.16 10.141 73.32 ;
     RECT  9.997 80.352 10.213 80.376 ;
     RECT  9.889 43.872 10.249 45.192 ;
     RECT  9.137 30.048 10.357 32.472 ;
     RECT  9.209 33.792 10.357 38.76 ;
     RECT  10.141 52.272 10.357 73.32 ;
     RECT  9.148 74.4 10.357 77.976 ;
     RECT  8.237 28.416 10.508 28.44 ;
     RECT  10.357 30.048 10.508 38.76 ;
     RECT  9.709 39.888 10.508 42.84 ;
     RECT  10.249 43.872 10.508 45.24 ;
     RECT  9.425 46.608 10.508 49.8 ;
     RECT  9.173 50.832 10.508 51.288 ;
     RECT  10.357 52.272 10.508 77.976 ;
     RECT  10.213 79.776 10.508 80.376 ;
     RECT  10.069 82.608 10.508 84.936 ;
     RECT  9.533 86.832 10.508 88.728 ;
     RECT  9.533 89.76 10.508 90.408 ;
     RECT  9.533 91.68 10.508 91.704 ;
     RECT  9.029 93.072 10.508 93.336 ;
     RECT  9.029 94.368 10.508 94.392 ;
     RECT  10.249 95.712 10.508 95.736 ;
     RECT  10.105 96.912 10.508 97.176 ;
     RECT  10.508 2.148 10.612 97.212 ;
     RECT  10.612 2.418 10.645 97.212 ;
     RECT  10.645 2.418 10.804 97.32 ;
     RECT  10.804 97.296 10.835 97.32 ;
     RECT  10.804 95.712 10.901 95.736 ;
     RECT  10.804 50.832 11.081 70.104 ;
     RECT  10.804 38.736 11.171 47.352 ;
     RECT  10.804 48.672 11.171 49.8 ;
     RECT  11.149 97.44 11.411 97.464 ;
     RECT  10.804 86.16 11.548 87.096 ;
     RECT  10.804 27.024 11.555 29.256 ;
     RECT  11.171 38.736 11.621 42.84 ;
     RECT  11.081 51.168 11.651 70.104 ;
     RECT  11.171 44.112 11.693 47.352 ;
     RECT  11.651 52.464 11.693 70.104 ;
     RECT  11.693 52.704 11.941 70.104 ;
     RECT  10.804 71.136 11.941 77.976 ;
     RECT  11.555 27.024 11.977 27.912 ;
     RECT  11.941 98.064 12.035 98.088 ;
     RECT  11.651 51.168 12.053 51.192 ;
     RECT  11.555 29.088 12.085 29.256 ;
     RECT  10.804 30.336 12.085 33.096 ;
     RECT  12.013 23.808 12.227 24.264 ;
     RECT  11.977 26.304 12.233 27.912 ;
     RECT  10.804 34.656 12.337 37.608 ;
     RECT  11.621 38.736 12.337 39.768 ;
     RECT  12.181 25.296 12.517 25.32 ;
     RECT  12.233 26.304 12.517 26.808 ;
     RECT  11.693 44.448 12.553 47.352 ;
     RECT  10.804 91.68 12.553 93.336 ;
     RECT  10.804 94.368 12.553 94.392 ;
     RECT  12.553 91.68 12.661 94.392 ;
     RECT  12.337 34.656 12.877 39.768 ;
     RECT  11.621 40.992 12.877 42.84 ;
     RECT  12.877 34.656 12.985 42.84 ;
     RECT  11.171 49.248 12.985 49.8 ;
     RECT  10.804 89.76 13.052 90.36 ;
     RECT  12.085 29.088 13.093 33.096 ;
     RECT  11.941 52.704 13.093 77.976 ;
     RECT  13.093 52.032 13.129 77.976 ;
     RECT  12.565 97.152 13.165 97.176 ;
     RECT  13.165 97.152 13.201 97.464 ;
     RECT  12.227 23.808 13.208 23.928 ;
     RECT  12.517 25.296 13.208 26.808 ;
     RECT  12.233 27.888 13.208 27.912 ;
     RECT  13.093 28.944 13.208 33.096 ;
     RECT  12.985 34.08 13.208 42.84 ;
     RECT  12.553 44.448 13.208 48.264 ;
     RECT  12.985 49.248 13.208 50.616 ;
     RECT  13.129 51.648 13.208 77.976 ;
     RECT  10.804 79.776 13.208 79.8 ;
     RECT  10.804 82.992 13.208 83.016 ;
     RECT  10.804 84.144 13.208 84.936 ;
     RECT  11.548 86.832 13.208 87.096 ;
     RECT  10.804 88.176 13.208 88.728 ;
     RECT  13.052 89.76 13.208 90.6 ;
     RECT  12.661 91.68 13.208 95.16 ;
     RECT  13.201 96.192 13.208 97.464 ;
     RECT  13.208 2.148 13.249 97.464 ;
     RECT  13.249 2.148 13.312 97.212 ;
     RECT  13.312 2.418 13.504 97.176 ;
     RECT  13.504 30.96 13.601 42.792 ;
     RECT  13.504 45.456 13.667 67.176 ;
     RECT  13.504 88.176 13.667 91.896 ;
     RECT  13.667 48.48 13.673 59.016 ;
     RECT  13.667 89.76 13.673 91.896 ;
     RECT  13.504 93.072 13.673 95.16 ;
     RECT  13.667 60 13.745 67.176 ;
     RECT  13.504 96.192 13.997 97.176 ;
     RECT  13.504 22.176 14.099 22.2 ;
     RECT  13.745 60.048 14.099 67.176 ;
     RECT  13.667 45.456 14.105 47.496 ;
     RECT  13.673 48.72 14.105 59.016 ;
     RECT  14.099 63.264 14.141 67.176 ;
     RECT  14.105 49.776 14.177 59.016 ;
     RECT  13.601 30.96 14.213 39.336 ;
     RECT  14.213 30.96 14.321 34.104 ;
     RECT  13.997 96.192 14.321 96.216 ;
     RECT  13.504 27.888 14.435 29.784 ;
     RECT  14.173 98.592 14.435 98.616 ;
     RECT  14.435 27.888 14.465 29.16 ;
     RECT  14.213 35.232 14.465 39.336 ;
     RECT  14.321 30.96 14.501 33.912 ;
     RECT  13.504 23.712 14.537 23.928 ;
     RECT  14.465 38.784 14.573 39.336 ;
     RECT  13.601 40.512 14.636 42.792 ;
     RECT  13.504 43.824 14.636 43.848 ;
     RECT  14.177 50.592 14.684 59.016 ;
     RECT  14.105 45.456 14.753 47.448 ;
     RECT  13.673 93.072 14.785 95.112 ;
     RECT  14.105 48.72 14.789 48.744 ;
     RECT  14.573 39.312 14.821 39.336 ;
     RECT  14.636 40.512 14.821 43.848 ;
     RECT  13.504 25.44 14.861 26.76 ;
     RECT  14.465 35.232 14.897 37.656 ;
     RECT  14.861 25.488 14.929 26.76 ;
     RECT  14.465 27.888 14.929 29.112 ;
     RECT  14.785 93.072 14.933 95.832 ;
     RECT  13.673 89.76 15.061 91.704 ;
     RECT  14.684 50.592 15.212 59.064 ;
     RECT  14.099 60.048 15.212 62.28 ;
     RECT  14.501 30.96 15.217 33.72 ;
     RECT  14.753 46.08 15.217 47.448 ;
     RECT  15.253 49.248 15.325 49.272 ;
     RECT  14.141 63.264 15.349 66.84 ;
     RECT  13.504 68.16 15.349 77.976 ;
     RECT  15.061 89.76 15.469 91.848 ;
     RECT  14.933 93.072 15.469 95.688 ;
     RECT  15.325 49.248 15.541 49.56 ;
     RECT  15.212 50.592 15.541 62.28 ;
     RECT  15.349 63.264 15.577 77.976 ;
     RECT  15.013 96.912 15.589 96.936 ;
     RECT  15.217 46.08 15.757 48.264 ;
     RECT  15.541 49.248 15.757 62.28 ;
     RECT  15.577 63.264 15.781 78.648 ;
     RECT  13.504 79.776 15.781 79.8 ;
     RECT  15.001 23.376 15.865 23.4 ;
     RECT  15.001 21.792 15.908 21.816 ;
     RECT  15.865 23.376 15.908 23.88 ;
     RECT  14.929 25.488 15.908 29.112 ;
     RECT  15.217 30.576 15.908 33.72 ;
     RECT  14.897 35.424 15.908 37.656 ;
     RECT  14.821 39.312 15.908 43.848 ;
     RECT  15.577 44.976 15.908 45 ;
     RECT  15.757 46.08 15.908 62.28 ;
     RECT  15.781 63.264 15.908 79.8 ;
     RECT  13.504 82.992 15.908 83.016 ;
     RECT  13.504 84.144 15.908 84.696 ;
     RECT  13.504 86.832 15.908 87.096 ;
     RECT  13.667 88.176 15.908 88.728 ;
     RECT  15.469 89.76 15.908 95.688 ;
     RECT  15.589 96.912 15.908 97.176 ;
     RECT  15.908 2.148 16.012 97.212 ;
     RECT  16.012 2.418 16.204 97.212 ;
     RECT  16.204 96.912 16.213 97.212 ;
     RECT  16.213 96.912 16.3 97.32 ;
     RECT  16.204 27.888 16.417 38.184 ;
     RECT  16.417 36.336 16.517 38.184 ;
     RECT  16.517 36.528 16.733 38.184 ;
     RECT  16.204 21.792 16.805 22.104 ;
     RECT  16.3 96.912 16.913 96.936 ;
     RECT  16.733 36.864 16.985 38.184 ;
     RECT  16.204 91.68 17.021 93.336 ;
     RECT  16.204 44.976 17.057 78.12 ;
     RECT  17.057 47.136 17.129 78.12 ;
     RECT  17.129 47.136 17.165 73.56 ;
     RECT  16.204 23.328 17.219 26.52 ;
     RECT  17.129 74.592 17.221 78.12 ;
     RECT  16.204 79.44 17.221 79.8 ;
     RECT  16.204 84.144 17.233 84.696 ;
     RECT  17.165 49.056 17.273 73.56 ;
     RECT  17.221 74.592 17.273 79.992 ;
     RECT  17.233 84.144 17.317 85.512 ;
     RECT  17.273 74.88 17.345 79.992 ;
     RECT  17.057 44.976 17.349 46.152 ;
     RECT  16.417 27.888 17.381 35.208 ;
     RECT  16.204 39.504 17.411 43.32 ;
     RECT  17.273 49.056 17.411 59.016 ;
     RECT  17.219 24.624 17.413 26.52 ;
     RECT  17.021 93.072 17.413 93.336 ;
     RECT  16.204 94.368 17.413 94.392 ;
     RECT  17.413 97.44 17.497 97.464 ;
     RECT  16.204 86.832 17.605 87.096 ;
     RECT  17.381 34.896 17.629 35.208 ;
     RECT  17.411 39.504 17.633 43.128 ;
     RECT  17.345 79.728 17.737 79.992 ;
     RECT  17.633 39.504 17.773 41.544 ;
     RECT  16.805 22.08 18.133 22.104 ;
     RECT  17.219 23.328 18.133 23.352 ;
     RECT  17.629 34.896 18.133 35.544 ;
     RECT  16.985 36.864 18.133 37.752 ;
     RECT  17.317 84.144 18.277 84.696 ;
     RECT  17.411 52.464 18.349 59.016 ;
     RECT  17.273 60.048 18.349 73.56 ;
     RECT  17.773 39.312 18.421 41.544 ;
     RECT  18.349 52.464 18.457 73.56 ;
     RECT  17.413 24.624 18.493 26.568 ;
     RECT  18.133 22.08 18.608 23.352 ;
     RECT  18.493 24.624 18.608 26.904 ;
     RECT  17.381 27.888 18.608 33.864 ;
     RECT  18.133 34.896 18.608 37.752 ;
     RECT  18.421 38.784 18.608 41.544 ;
     RECT  17.633 42.576 18.608 43.128 ;
     RECT  17.349 44.88 18.608 46.152 ;
     RECT  17.165 47.136 18.608 47.64 ;
     RECT  17.411 49.056 18.608 51.192 ;
     RECT  18.457 52.464 18.608 73.656 ;
     RECT  17.345 74.88 18.608 78.648 ;
     RECT  17.737 79.728 18.608 80.328 ;
     RECT  16.204 82.992 18.608 83.016 ;
     RECT  18.277 84.048 18.608 84.696 ;
     RECT  17.605 85.872 18.608 87.096 ;
     RECT  16.204 88.176 18.608 88.728 ;
     RECT  16.204 89.76 18.608 90.408 ;
     RECT  17.021 91.68 18.608 91.704 ;
     RECT  17.413 93.072 18.608 94.392 ;
     RECT  17.989 96.912 18.608 96.936 ;
     RECT  18.608 2.148 18.613 97.212 ;
     RECT  18.613 2.148 18.712 97.368 ;
     RECT  18.712 2.418 18.785 97.368 ;
     RECT  18.785 2.418 18.904 96.942 ;
     RECT  18.904 37.2 19.139 49.512 ;
     RECT  18.904 34.896 19.181 36.12 ;
     RECT  18.904 71.088 19.187 81.048 ;
     RECT  19.139 37.2 19.217 49.272 ;
     RECT  19.187 79.776 19.217 81.048 ;
     RECT  18.904 24.624 19.253 25.464 ;
     RECT  19.217 79.776 19.289 80.952 ;
     RECT  18.904 50.592 19.361 51.192 ;
     RECT  18.904 52.464 19.649 69.816 ;
     RECT  18.904 26.544 19.865 26.904 ;
     RECT  18.904 92.688 19.865 93.336 ;
     RECT  18.904 96.912 19.9 96.936 ;
     RECT  19.865 26.544 19.901 26.808 ;
     RECT  19.181 34.944 19.937 36.072 ;
     RECT  19.865 93.072 19.957 93.336 ;
     RECT  18.904 94.368 19.957 95.208 ;
     RECT  19.957 93.072 20.003 95.208 ;
     RECT  20.003 95.184 20.081 95.208 ;
     RECT  19.217 37.2 20.153 48.408 ;
     RECT  18.904 27.984 20.185 29.592 ;
     RECT  18.904 30.576 20.185 33.864 ;
     RECT  19.361 50.64 20.185 51.192 ;
     RECT  19.649 52.464 20.185 63.672 ;
     RECT  19.937 35.52 20.197 36.072 ;
     RECT  20.153 37.2 20.197 43.656 ;
     RECT  20.185 50.64 20.261 63.672 ;
     RECT  20.185 27.984 20.329 33.864 ;
     RECT  20.153 45.12 20.329 48.408 ;
     RECT  19.253 25.44 20.389 25.464 ;
     RECT  18.904 89.76 20.389 90.36 ;
     RECT  18.904 91.68 20.389 91.704 ;
     RECT  20.261 50.64 20.509 59.064 ;
     RECT  18.904 84.048 20.509 84.696 ;
     RECT  19.649 64.656 20.533 69.816 ;
     RECT  20.329 45.12 20.629 48.696 ;
     RECT  20.329 27.936 20.689 33.864 ;
     RECT  20.533 64.656 20.689 70.008 ;
     RECT  19.187 71.088 20.689 78.648 ;
     RECT  18.904 22.32 20.725 23.352 ;
     RECT  20.509 50.544 20.869 59.064 ;
     RECT  20.389 89.76 20.941 91.704 ;
     RECT  20.003 93.072 20.941 94.056 ;
     RECT  20.629 45.12 20.977 48.936 ;
     RECT  20.869 50.304 20.977 59.064 ;
     RECT  20.389 25.296 21.013 25.464 ;
     RECT  19.901 26.592 21.013 26.808 ;
     RECT  20.389 97.152 21.013 97.176 ;
     RECT  21.013 25.296 21.049 26.808 ;
     RECT  20.689 64.656 21.061 78.648 ;
     RECT  19.289 79.776 21.061 80.808 ;
     RECT  21.049 25.2 21.121 26.808 ;
     RECT  20.689 27.936 21.121 34.2 ;
     RECT  20.725 22.32 21.308 24.216 ;
     RECT  21.121 25.2 21.308 26.856 ;
     RECT  21.121 27.936 21.308 34.392 ;
     RECT  20.197 35.52 21.308 43.656 ;
     RECT  20.977 45.12 21.308 59.064 ;
     RECT  20.261 60.048 21.308 63.672 ;
     RECT  21.061 64.656 21.308 80.808 ;
     RECT  18.904 82.032 21.308 83.016 ;
     RECT  20.509 84.048 21.308 85.512 ;
     RECT  18.904 86.832 21.308 87.096 ;
     RECT  18.904 88.176 21.308 88.728 ;
     RECT  20.941 89.76 21.308 94.056 ;
     RECT  21.013 96.912 21.308 97.176 ;
     RECT  21.308 2.148 21.412 97.212 ;
     RECT  21.412 2.418 21.604 97.212 ;
     RECT  21.604 96.912 21.637 97.212 ;
     RECT  21.604 49.776 21.665 50.568 ;
     RECT  21.604 60.048 21.701 80.664 ;
     RECT  21.604 34.368 21.737 43.32 ;
     RECT  21.604 89.76 21.781 90.696 ;
     RECT  21.637 96.912 21.809 97.32 ;
     RECT  21.604 44.352 22.115 47.16 ;
     RECT  21.701 60.144 22.141 80.664 ;
     RECT  21.604 21.648 22.163 21.672 ;
     RECT  21.604 22.8 22.205 24.216 ;
     RECT  21.604 25.2 22.205 31.176 ;
     RECT  21.737 40.368 22.205 43.32 ;
     RECT  21.665 49.872 22.277 50.568 ;
     RECT  22.115 44.352 22.313 45.864 ;
     RECT  21.604 48.432 22.421 48.696 ;
     RECT  22.205 29.04 22.451 31.176 ;
     RECT  22.205 23.904 22.493 24.216 ;
     RECT  22.115 46.848 22.604 47.16 ;
     RECT  22.604 46.848 22.633 47.4 ;
     RECT  22.421 48.432 22.633 48.504 ;
     RECT  22.141 67.536 22.633 80.664 ;
     RECT  21.604 81.888 22.633 83.016 ;
     RECT  22.451 29.616 22.669 31.176 ;
     RECT  21.604 32.304 22.669 33.384 ;
     RECT  22.205 25.2 22.693 27.912 ;
     RECT  22.633 46.848 22.717 48.504 ;
     RECT  22.493 23.904 22.745 23.928 ;
     RECT  21.604 51.936 22.777 59.064 ;
     RECT  22.633 67.536 22.787 83.016 ;
     RECT  22.141 60.144 22.813 66.36 ;
     RECT  21.604 88.176 22.837 88.728 ;
     RECT  21.781 89.76 22.837 90.36 ;
     RECT  22.205 41.568 22.849 43.32 ;
     RECT  22.693 25.104 22.853 27.912 ;
     RECT  22.787 71.088 22.853 83.016 ;
     RECT  21.604 91.68 22.885 94.056 ;
     RECT  21.809 96.912 22.924 96.936 ;
     RECT  22.837 88.176 22.925 90.36 ;
     RECT  22.853 81.888 22.933 83.016 ;
     RECT  21.604 84.048 22.933 87.096 ;
     RECT  21.604 95.616 22.961 95.736 ;
     RECT  22.885 91.68 22.969 94.104 ;
     RECT  22.205 22.8 23.029 22.824 ;
     RECT  22.777 51.312 23.029 59.064 ;
     RECT  22.813 60.048 23.029 66.36 ;
     RECT  21.737 34.368 23.173 39.336 ;
     RECT  22.205 40.368 23.173 40.488 ;
     RECT  23.029 51.312 23.245 66.36 ;
     RECT  22.787 67.536 23.245 69.816 ;
     RECT  22.313 45.12 23.605 45.864 ;
     RECT  22.717 46.848 23.708 47.352 ;
     RECT  22.717 48.432 23.708 48.504 ;
     RECT  22.669 29.616 23.821 33.384 ;
     RECT  23.173 34.368 23.821 40.488 ;
     RECT  23.413 97.152 23.821 97.176 ;
     RECT  23.821 29.616 23.893 40.488 ;
     RECT  22.849 41.568 23.893 43.8 ;
     RECT  22.925 88.176 23.929 90.264 ;
     RECT  23.029 22.656 24.008 22.824 ;
     RECT  22.853 25.104 24.008 27 ;
     RECT  23.317 28.224 24.008 28.248 ;
     RECT  23.893 29.616 24.008 43.8 ;
     RECT  23.605 44.976 24.008 45.864 ;
     RECT  23.708 46.848 24.008 48.504 ;
     RECT  22.277 49.872 24.008 49.896 ;
     RECT  23.245 51.312 24.008 69.816 ;
     RECT  22.853 71.088 24.008 80.904 ;
     RECT  22.933 81.888 24.008 87.096 ;
     RECT  23.929 88.176 24.008 90.552 ;
     RECT  22.969 91.68 24.008 94.056 ;
     RECT  22.961 95.712 24.008 95.736 ;
     RECT  23.821 97.152 24.008 98.088 ;
     RECT  24.008 2.148 24.112 98.088 ;
     RECT  24.112 2.418 24.304 98.088 ;
     RECT  24.304 27.936 24.329 37.992 ;
     RECT  24.304 39.312 24.437 45.768 ;
     RECT  24.304 46.752 24.445 49.08 ;
     RECT  24.304 50.832 24.515 87.096 ;
     RECT  24.329 30.048 24.617 37.992 ;
     RECT  24.304 97.152 24.659 98.088 ;
     RECT  24.304 92.784 24.689 93.528 ;
     RECT  24.437 39.312 24.803 40.968 ;
     RECT  24.304 22.8 24.833 22.824 ;
     RECT  24.437 42.048 24.833 45.768 ;
     RECT  24.515 51.408 24.905 87.096 ;
     RECT  24.617 31.824 24.941 37.992 ;
     RECT  24.304 24.816 24.995 26.808 ;
     RECT  24.995 25.872 25.091 26.808 ;
     RECT  24.941 31.824 25.091 31.848 ;
     RECT  24.905 51.408 25.121 81.672 ;
     RECT  24.941 32.88 25.129 37.992 ;
     RECT  25.129 32.88 25.139 37.08 ;
     RECT  24.689 92.784 25.157 93.336 ;
     RECT  24.304 19.632 25.187 20.232 ;
     RECT  25.187 20.208 25.228 20.232 ;
     RECT  25.091 25.872 25.229 25.896 ;
     RECT  24.445 46.8 25.265 49.08 ;
     RECT  24.659 98.064 25.283 98.088 ;
     RECT  24.304 88.176 25.549 90.648 ;
     RECT  24.304 91.68 25.549 91.704 ;
     RECT  25.139 35.52 25.625 37.08 ;
     RECT  25.121 51.408 25.661 81.624 ;
     RECT  24.833 42.144 25.693 45.768 ;
     RECT  25.265 46.8 25.693 48.504 ;
     RECT  24.617 30.048 25.729 30.84 ;
     RECT  25.625 35.52 25.733 36.552 ;
     RECT  24.905 82.656 25.981 87.096 ;
     RECT  25.549 88.176 25.981 91.704 ;
     RECT  24.329 27.936 26.053 28.776 ;
     RECT  25.661 51.408 26.125 59.784 ;
     RECT  25.139 32.88 26.149 34.104 ;
     RECT  25.733 35.52 26.149 36.072 ;
     RECT  26.053 27.168 26.197 28.776 ;
     RECT  25.729 29.904 26.197 30.84 ;
     RECT  13.861 0.192 26.377 0.216 ;
     RECT  26.377 0.192 26.489 0.312 ;
     RECT  25.981 82.656 26.549 91.704 ;
     RECT  26.197 27.168 26.701 30.936 ;
     RECT  25.621 38.16 26.701 38.184 ;
     RECT  26.701 27.168 26.708 31.8 ;
     RECT  26.149 32.88 26.708 36.072 ;
     RECT  26.701 37.584 26.708 38.184 ;
     RECT  24.803 39.6 26.708 40.968 ;
     RECT  25.693 42.144 26.708 48.504 ;
     RECT  26.089 49.536 26.708 49.56 ;
     RECT  26.125 50.976 26.708 59.784 ;
     RECT  25.661 60.768 26.708 81.624 ;
     RECT  26.549 82.608 26.708 91.704 ;
     RECT  25.157 92.832 26.708 93.336 ;
     RECT  25.945 94.608 26.708 94.632 ;
     RECT  24.304 95.904 26.708 95.928 ;
     RECT  25.765 96.912 26.708 96.936 ;
     RECT  26.708 2.148 26.812 97.212 ;
     RECT  26.812 2.418 27.004 97.212 ;
     RECT  27.004 96.912 27.061 97.212 ;
     RECT  27.004 52.56 27.065 83.016 ;
     RECT  27.004 94.608 27.065 94.632 ;
     RECT  27.004 27.168 27.209 27.72 ;
     RECT  27.061 96.912 27.281 97.32 ;
     RECT  27.004 32.928 27.388 33.192 ;
     RECT  27.004 34.752 27.425 40.968 ;
     RECT  27.004 42.192 27.425 45.816 ;
     RECT  27.425 42.192 27.491 45.72 ;
     RECT  27.388 33.072 27.533 33.192 ;
     RECT  27.491 42.192 27.713 45.288 ;
     RECT  27.065 52.56 27.713 62.472 ;
     RECT  27.004 28.8 27.821 29.064 ;
     RECT  27.004 50.112 27.827 51.192 ;
     RECT  27.425 34.752 27.865 38.952 ;
     RECT  27.004 91.68 27.98 91.848 ;
     RECT  27.004 92.832 27.98 93.336 ;
     RECT  27.533 33.168 27.997 33.192 ;
     RECT  27.713 52.56 27.997 57.912 ;
     RECT  27.209 27.696 28.001 27.72 ;
     RECT  27.004 84 28.028 90.552 ;
     RECT  27.98 91.68 28.061 93.336 ;
     RECT  28.033 94.944 28.061 94.968 ;
     RECT  27.004 30.384 28.109 31.8 ;
     RECT  27.997 52.464 28.249 57.912 ;
     RECT  28.028 84 28.285 90.6 ;
     RECT  28.061 91.68 28.285 94.968 ;
     RECT  28.109 30.384 28.361 31.512 ;
     RECT  27.865 35.424 28.465 38.952 ;
     RECT  27.425 40.032 28.465 40.968 ;
     RECT  27.065 63.504 28.573 83.016 ;
     RECT  28.285 84 28.573 94.968 ;
     RECT  27.713 42.192 28.681 44.472 ;
     RECT  27.713 58.944 28.741 62.472 ;
     RECT  28.573 63.504 28.741 95.16 ;
     RECT  27.281 96.912 28.837 96.936 ;
     RECT  28.681 42.192 28.861 44.76 ;
     RECT  28.249 52.416 28.861 57.912 ;
     RECT  28.741 58.944 28.861 95.16 ;
     RECT  27.997 33.168 29.005 34.104 ;
     RECT  27.004 46.896 29.005 49.08 ;
     RECT  29.005 46.128 29.077 49.08 ;
     RECT  27.827 50.112 29.077 50.136 ;
     RECT  27.827 51.168 29.113 51.192 ;
     RECT  28.861 52.416 29.113 95.16 ;
     RECT  28.465 35.424 29.221 40.968 ;
     RECT  28.861 41.952 29.221 44.76 ;
     RECT  29.077 46.128 29.221 50.136 ;
     RECT  29.113 51.168 29.221 95.16 ;
     RECT  29.005 32.496 29.228 34.104 ;
     RECT  29.221 35.424 29.228 44.952 ;
     RECT  29.228 32.496 29.269 44.952 ;
     RECT  27.821 28.992 29.365 29.064 ;
     RECT  28.837 96.912 29.365 97.176 ;
     RECT  28.46 27.792 29.408 27.816 ;
     RECT  29.365 28.992 29.408 29.256 ;
     RECT  28.361 30.864 29.408 31.512 ;
     RECT  29.269 32.496 29.408 45.048 ;
     RECT  29.221 46.128 29.408 95.16 ;
     RECT  29.365 96.912 29.408 97.464 ;
     RECT  29.408 2.148 29.507 97.464 ;
     RECT  29.507 2.148 29.512 97.212 ;
     RECT  29.512 2.418 29.704 97.176 ;
     RECT  29.704 52.752 29.729 66.312 ;
     RECT  29.704 30.864 29.765 31.512 ;
     RECT  29.704 48.144 29.765 50.568 ;
     RECT  29.704 67.92 29.837 94.056 ;
     RECT  29.704 29.04 29.843 29.256 ;
     RECT  29.704 32.496 29.843 35.88 ;
     RECT  29.837 67.92 30.125 93.624 ;
     RECT  29.704 96.912 30.125 97.176 ;
     RECT  29.704 36.864 30.161 38.76 ;
     RECT  29.843 32.496 30.227 33.048 ;
     RECT  30.161 37.008 30.241 38.76 ;
     RECT  29.843 34.368 30.269 35.88 ;
     RECT  29.704 95.52 30.269 95.544 ;
     RECT  29.704 39.888 30.323 45.768 ;
     RECT  30.241 37.584 30.341 38.76 ;
     RECT  30.323 39.888 30.364 39.912 ;
     RECT  29.765 30.864 30.485 31.128 ;
     RECT  30.269 35.664 30.701 35.88 ;
     RECT  29.765 48.432 30.733 50.568 ;
     RECT  30.125 96.912 30.748 96.936 ;
     RECT  29.729 52.752 30.769 66.264 ;
     RECT  30.701 35.808 30.809 35.88 ;
     RECT  30.769 52.752 30.809 66.36 ;
     RECT  30.323 40.944 30.917 45.768 ;
     RECT  30.917 44.64 31.061 45.768 ;
     RECT  29.704 46.944 31.093 47.16 ;
     RECT  30.733 48.432 31.093 50.616 ;
     RECT  30.125 67.92 31.129 91.704 ;
     RECT  31.129 67.92 31.237 91.944 ;
     RECT  30.269 34.368 31.309 34.392 ;
     RECT  31.093 46.944 31.309 50.616 ;
     RECT  29.704 51.648 31.309 51.672 ;
     RECT  31.237 67.824 31.309 91.944 ;
     RECT  31.237 97.44 31.321 97.464 ;
     RECT  31.309 46.944 31.333 51.672 ;
     RECT  30.809 52.752 31.333 54.456 ;
     RECT  31.309 34.32 31.417 34.392 ;
     RECT  30.227 32.88 31.489 33.048 ;
     RECT  30.341 37.584 31.561 38.232 ;
     RECT  31.237 39.264 31.561 39.864 ;
     RECT  31.561 37.584 31.621 39.864 ;
     RECT  31.489 32.88 31.633 33.096 ;
     RECT  30.809 55.968 31.633 66.36 ;
     RECT  31.309 67.344 31.633 91.944 ;
     RECT  31.417 34.32 31.813 34.488 ;
     RECT  31.333 46.944 31.849 54.456 ;
     RECT  31.633 32.784 31.885 33.096 ;
     RECT  31.621 37.44 31.957 39.864 ;
     RECT  30.125 93.072 32.029 93.624 ;
     RECT  31.309 95.184 32.029 95.208 ;
     RECT  29.843 29.232 32.108 29.256 ;
     RECT  31.201 31.296 32.108 31.32 ;
     RECT  31.885 32.592 32.108 33.096 ;
     RECT  31.813 34.128 32.108 34.488 ;
     RECT  30.809 35.808 32.108 35.832 ;
     RECT  31.957 37.152 32.108 39.864 ;
     RECT  30.917 40.944 32.108 43.368 ;
     RECT  31.061 45.744 32.108 45.768 ;
     RECT  31.849 46.944 32.108 54.936 ;
     RECT  31.633 55.968 32.108 91.944 ;
     RECT  32.029 93.072 32.108 95.208 ;
     RECT  31.861 97.152 32.108 97.212 ;
     RECT  32.108 2.148 32.212 97.212 ;
     RECT  32.212 2.418 32.404 96.942 ;
     RECT  32.404 34.416 32.429 34.44 ;
     RECT  32.404 37.104 32.465 38.424 ;
     RECT  32.425 98.064 32.531 98.088 ;
     RECT  32.404 39.84 32.573 43.704 ;
     RECT  32.404 32.592 33.113 33.096 ;
     RECT  32.404 96.912 33.149 96.936 ;
     RECT  32.404 45.456 33.397 47.16 ;
     RECT  32.465 37.344 33.433 38.424 ;
     RECT  32.404 48.768 33.589 51.768 ;
     RECT  32.404 52.752 33.589 92.04 ;
     RECT  33.589 48.768 33.635 92.04 ;
     RECT  33.635 48.768 33.653 50.904 ;
     RECT  33.635 51.888 33.676 92.04 ;
     RECT  32.573 40.56 33.761 43.704 ;
     RECT  33.685 97.152 33.772 97.176 ;
     RECT  33.397 45.024 33.793 47.16 ;
     RECT  32.404 35.808 33.925 35.832 ;
     RECT  33.793 44.784 33.973 47.16 ;
     RECT  33.925 35.04 34.009 35.832 ;
     RECT  34.009 34.656 34.045 35.832 ;
     RECT  33.433 37.296 34.045 38.424 ;
     RECT  33.761 41.904 34.152 43.704 ;
     RECT  33.973 44.784 34.152 47.304 ;
     RECT  32.404 93.072 34.153 95.928 ;
     RECT  34.045 34.656 34.333 38.424 ;
     RECT  34.153 93.024 34.513 95.928 ;
     RECT  33.653 49.536 34.729 50.904 ;
     RECT  33.676 52.032 34.729 92.04 ;
     RECT  33.113 33.072 34.808 33.096 ;
     RECT  34.333 34.08 34.808 38.424 ;
     RECT  33.761 40.56 34.808 40.92 ;
     RECT  34.152 41.904 34.808 47.304 ;
     RECT  34.729 49.536 34.808 92.04 ;
     RECT  34.513 93.024 34.808 96.264 ;
     RECT  34.808 2.148 34.885 97.212 ;
     RECT  34.885 2.148 34.912 97.368 ;
     RECT  34.912 2.418 35.057 97.368 ;
     RECT  35.057 2.418 35.104 96.942 ;
     RECT  35.104 34.656 35.129 38.76 ;
     RECT  35.129 34.656 35.219 36.072 ;
     RECT  35.129 37.056 35.273 38.76 ;
     RECT  35.104 73.488 35.273 91.704 ;
     RECT  35.104 47.712 35.315 57.912 ;
     RECT  35.104 39.984 35.345 40.008 ;
     RECT  35.104 45.168 35.381 45.72 ;
     RECT  35.273 82.08 35.453 91.704 ;
     RECT  34.153 98.592 35.507 98.616 ;
     RECT  35.219 36.048 35.633 36.072 ;
     RECT  35.453 82.08 35.692 87.144 ;
     RECT  35.104 60.576 35.741 72.504 ;
     RECT  35.315 48.96 35.913 57.912 ;
     RECT  35.692 86.64 36.029 87.144 ;
     RECT  35.104 92.88 36.085 96.264 ;
     RECT  35.219 34.656 36.101 35.016 ;
     RECT  35.381 45.504 36.205 45.72 ;
     RECT  35.104 58.992 36.205 59.592 ;
     RECT  35.741 60.576 36.205 66.6 ;
     RECT  36.101 34.656 36.245 34.824 ;
     RECT  35.104 41.76 36.277 43.56 ;
     RECT  35.273 73.488 36.277 81.096 ;
     RECT  35.692 82.08 36.277 85.512 ;
     RECT  35.315 47.712 36.313 47.928 ;
     RECT  35.913 48.96 36.313 50.952 ;
     RECT  36.085 92.88 36.317 96.936 ;
     RECT  35.913 52.176 36.421 57.912 ;
     RECT  36.205 58.992 36.421 66.6 ;
     RECT  36.313 47.712 36.425 50.952 ;
     RECT  36.421 52.176 36.425 66.6 ;
     RECT  35.741 68.16 36.457 72.504 ;
     RECT  36.277 73.488 36.457 85.512 ;
     RECT  35.453 88.176 36.457 91.704 ;
     RECT  36.317 92.88 36.457 95.208 ;
     RECT  36.277 40.992 36.461 43.56 ;
     RECT  35.273 37.104 36.469 38.76 ;
     RECT  36.317 96.24 36.661 96.936 ;
     RECT  36.425 52.176 37.105 52.776 ;
     RECT  36.469 36.528 37.249 38.808 ;
     RECT  36.457 68.16 37.285 85.512 ;
     RECT  36.457 88.176 37.357 95.208 ;
     RECT  36.245 34.8 37.508 34.824 ;
     RECT  37.249 36.432 37.508 38.808 ;
     RECT  37.249 40.56 37.508 40.584 ;
     RECT  36.461 41.808 37.508 43.56 ;
     RECT  36.205 45.504 37.508 45.816 ;
     RECT  36.425 47.904 37.508 50.952 ;
     RECT  37.105 51.936 37.508 52.776 ;
     RECT  36.425 53.904 37.508 66.6 ;
     RECT  37.285 68.16 37.508 85.704 ;
     RECT  36.029 86.832 37.508 87.144 ;
     RECT  37.357 88.176 37.508 95.256 ;
     RECT  36.661 96.24 37.508 97.176 ;
     RECT  37.508 2.148 37.612 97.212 ;
     RECT  37.612 2.418 37.804 97.212 ;
     RECT  37.804 51.84 37.861 97.212 ;
     RECT  37.804 36.864 37.937 38.76 ;
     RECT  37.861 51.84 37.955 97.32 ;
     RECT  37.955 88.176 37.973 97.32 ;
     RECT  37.973 88.176 38.189 96.936 ;
     RECT  37.955 51.84 38.261 52.776 ;
     RECT  37.804 43.056 38.333 48.792 ;
     RECT  38.333 43.056 38.405 45.096 ;
     RECT  38.333 46.176 38.557 48.792 ;
     RECT  37.955 53.904 38.585 87.096 ;
     RECT  37.804 42 38.797 42.024 ;
     RECT  37.804 50.016 38.797 50.712 ;
     RECT  37.937 37.056 38.828 38.76 ;
     RECT  38.797 50.016 38.905 50.856 ;
     RECT  38.261 51.84 38.905 52.44 ;
     RECT  38.585 70.992 38.945 87.096 ;
     RECT  38.189 92.784 38.945 96.936 ;
     RECT  38.905 50.016 39.017 52.44 ;
     RECT  38.945 83.856 39.049 87.096 ;
     RECT  38.189 88.176 39.049 91.704 ;
     RECT  38.797 42 39.053 42.312 ;
     RECT  39.053 42 39.121 42.024 ;
     RECT  39.049 83.856 39.125 91.704 ;
     RECT  39.017 50.016 39.193 51.432 ;
     RECT  39.193 49.968 39.229 51.432 ;
     RECT  39.017 52.416 39.265 52.44 ;
     RECT  38.585 53.904 39.265 69.864 ;
     RECT  39.125 91.68 39.301 91.704 ;
     RECT  38.945 92.784 39.301 95.208 ;
     RECT  38.557 47.424 39.409 48.792 ;
     RECT  39.229 49.824 39.409 51.432 ;
     RECT  38.828 37.056 39.517 39.048 ;
     RECT  37.804 40.176 39.517 40.584 ;
     RECT  39.121 41.616 39.517 42.024 ;
     RECT  38.945 96.192 39.685 96.936 ;
     RECT  38.945 70.992 39.913 82.824 ;
     RECT  39.125 83.856 39.913 90.696 ;
     RECT  39.517 37.056 39.925 42.024 ;
     RECT  39.265 52.416 39.985 69.864 ;
     RECT  39.913 70.992 39.985 90.696 ;
     RECT  39.925 36.96 40.021 42.024 ;
     RECT  38.405 43.296 40.021 45.096 ;
     RECT  40.021 36.96 40.208 45.096 ;
     RECT  38.557 46.176 40.208 46.2 ;
     RECT  39.409 47.424 40.208 51.432 ;
     RECT  39.985 52.416 40.208 90.696 ;
     RECT  39.301 91.68 40.208 95.208 ;
     RECT  39.685 96.192 40.208 97.176 ;
     RECT  40.208 2.148 40.309 97.212 ;
     RECT  40.309 2.148 40.312 97.368 ;
     RECT  40.312 2.418 40.396 97.368 ;
     RECT  40.396 2.418 40.504 97.176 ;
     RECT  40.504 37.056 40.601 38.76 ;
     RECT  40.504 40.032 40.637 41.688 ;
     RECT  40.504 47.424 40.637 51.864 ;
     RECT  40.601 37.056 40.643 38.664 ;
     RECT  40.504 64.656 40.673 97.176 ;
     RECT  40.504 55.68 40.781 57.912 ;
     RECT  40.504 42.72 40.925 45.672 ;
     RECT  40.504 53.04 40.925 54.456 ;
     RECT  40.637 40.416 40.997 41.688 ;
     RECT  40.673 84.048 41.027 97.176 ;
     RECT  40.643 37.872 41.033 38.664 ;
     RECT  41.027 88.176 41.033 97.176 ;
     RECT  40.925 43.584 41.105 45.672 ;
     RECT  40.673 64.656 41.105 83.064 ;
     RECT  40.637 47.52 41.141 51.864 ;
     RECT  41.141 48.672 41.213 51.864 ;
     RECT  40.997 40.416 41.219 40.44 ;
     RECT  41.105 43.872 41.315 45.672 ;
     RECT  40.781 56.256 41.533 57.912 ;
     RECT  40.997 41.424 41.641 41.688 ;
     RECT  41.105 67.776 41.645 83.064 ;
     RECT  41.641 41.424 41.681 42.168 ;
     RECT  41.533 56.256 41.749 57.96 ;
     RECT  40.504 58.992 41.749 63.576 ;
     RECT  41.645 73.488 41.749 83.064 ;
     RECT  41.027 84.048 41.749 87.096 ;
     RECT  40.925 53.328 41.893 54.456 ;
     RECT  41.749 73.488 41.939 87.096 ;
     RECT  41.033 38.352 41.965 38.664 ;
     RECT  41.213 49.056 42.073 51.864 ;
     RECT  41.893 52.992 42.073 54.456 ;
     RECT  41.785 46.416 42.133 46.44 ;
     RECT  41.141 47.52 42.133 47.544 ;
     RECT  42.073 49.056 42.289 54.456 ;
     RECT  41.315 44.88 42.325 45.288 ;
     RECT  42.133 46.416 42.325 47.544 ;
     RECT  41.645 67.776 42.361 72.504 ;
     RECT  42.289 49.056 42.428 54.984 ;
     RECT  41.749 56.256 42.428 63.576 ;
     RECT  42.361 39.792 42.433 39.816 ;
     RECT  41.315 43.872 42.517 43.896 ;
     RECT  42.325 44.88 42.517 47.544 ;
     RECT  41.033 88.176 42.677 96.936 ;
     RECT  41.965 38.352 42.709 38.76 ;
     RECT  42.517 43.872 42.721 47.544 ;
     RECT  42.428 49.056 42.721 63.576 ;
     RECT  41.105 64.656 42.757 66.36 ;
     RECT  42.361 67.68 42.757 72.504 ;
     RECT  42.709 38.16 42.908 38.76 ;
     RECT  42.433 39.792 42.908 40.056 ;
     RECT  41.681 41.664 42.908 42.168 ;
     RECT  42.721 43.872 42.908 63.576 ;
     RECT  42.757 64.656 42.908 72.504 ;
     RECT  41.939 73.776 42.908 87.096 ;
     RECT  42.677 88.176 42.908 97.176 ;
     RECT  42.908 2.148 43.012 97.212 ;
     RECT  43.012 2.418 43.204 96.942 ;
     RECT  43.204 47.328 43.265 50.952 ;
     RECT  43.204 74.544 43.409 94.44 ;
     RECT  43.204 45.216 43.445 46.344 ;
     RECT  43.204 38.736 43.516 41.928 ;
     RECT  43.516 39.072 43.733 41.928 ;
     RECT  43.204 56.304 43.733 73.272 ;
     RECT  43.733 60.912 43.805 73.272 ;
     RECT  43.265 47.328 43.877 50.856 ;
     RECT  43.805 63.552 43.877 73.272 ;
     RECT  43.445 45.264 43.913 46.344 ;
     RECT  43.204 52.32 43.949 54.456 ;
     RECT  43.733 39.072 43.955 40.728 ;
     RECT  43.733 56.304 44.021 59.928 ;
     RECT  43.913 45.456 44.093 46.344 ;
     RECT  43.877 47.328 44.261 50.568 ;
     RECT  44.261 46.704 44.339 50.568 ;
     RECT  44.339 46.704 44.345 46.728 ;
     RECT  44.339 47.856 44.381 50.568 ;
     RECT  43.204 43.872 44.413 43.896 ;
     RECT  44.413 43.632 44.453 43.896 ;
     RECT  43.409 83.04 44.485 94.44 ;
     RECT  43.877 70.368 44.489 73.272 ;
     RECT  43.409 74.544 44.521 82.008 ;
     RECT  43.955 39.888 44.525 40.728 ;
     RECT  44.021 56.304 44.531 59.832 ;
     RECT  43.204 96 44.533 96.936 ;
     RECT  44.485 82.992 44.561 94.44 ;
     RECT  44.533 96 44.62 97.176 ;
     RECT  44.381 47.856 44.633 48.216 ;
     RECT  44.531 56.304 44.737 57.912 ;
     RECT  43.949 52.752 44.809 54.456 ;
     RECT  44.521 74.304 44.845 82.008 ;
     RECT  44.561 82.992 44.845 88.728 ;
     RECT  44.561 89.76 44.845 94.44 ;
     RECT  44.62 96 44.845 96.264 ;
     RECT  43.805 60.912 44.869 62.28 ;
     RECT  43.877 63.552 44.869 69.384 ;
     RECT  44.381 49.488 44.881 50.568 ;
     RECT  44.869 60.912 44.881 69.384 ;
     RECT  44.489 70.368 44.881 72.264 ;
     RECT  44.881 49.488 44.917 51.528 ;
     RECT  44.845 98.64 45.155 98.664 ;
     RECT  44.093 45.6 45.253 45.624 ;
     RECT  44.917 49.488 45.253 51.672 ;
     RECT  44.809 52.752 45.253 54.744 ;
     RECT  45.253 49.488 45.301 54.744 ;
     RECT  44.737 55.776 45.301 57.912 ;
     RECT  44.531 58.992 45.385 59.832 ;
     RECT  44.881 60.912 45.385 72.264 ;
     RECT  43.733 41.904 45.452 41.928 ;
     RECT  44.633 48.192 45.452 48.216 ;
     RECT  45.301 49.488 45.452 57.912 ;
     RECT  44.453 43.632 45.493 43.656 ;
     RECT  45.253 44.88 45.493 45.624 ;
     RECT  45.385 58.992 45.529 72.264 ;
     RECT  44.489 73.248 45.529 73.272 ;
     RECT  44.525 39.888 45.608 39.912 ;
     RECT  45.452 40.992 45.608 41.928 ;
     RECT  45.493 43.536 45.608 45.624 ;
     RECT  45.452 48.192 45.608 57.912 ;
     RECT  45.529 58.992 45.608 73.272 ;
     RECT  44.845 74.304 45.608 88.728 ;
     RECT  44.845 89.76 45.608 96.264 ;
     RECT  45.608 2.148 45.712 97.212 ;
     RECT  45.712 2.418 45.733 97.212 ;
     RECT  45.733 2.418 45.904 97.368 ;
     RECT  45.904 68.064 45.965 82.584 ;
     RECT  45.904 83.808 46.073 96.264 ;
     RECT  45.904 66.816 46.214 67.08 ;
     RECT  46.214 66.816 46.217 67.032 ;
     RECT  45.904 49.776 46.253 65.448 ;
     RECT  46.249 97.44 46.355 97.464 ;
     RECT  45.904 41.136 46.433 41.496 ;
     RECT  46.073 92.784 46.541 96.264 ;
     RECT  46.253 49.776 46.649 56.328 ;
     RECT  45.904 43.536 46.685 45.816 ;
     RECT  46.433 41.424 46.721 41.496 ;
     RECT  46.721 41.424 46.793 41.448 ;
     RECT  46.649 50.016 46.793 56.328 ;
     RECT  45.965 68.064 46.793 81.528 ;
     RECT  46.073 83.808 46.897 91.752 ;
     RECT  46.685 43.536 46.901 45.576 ;
     RECT  46.541 96.24 46.933 96.264 ;
     RECT  46.793 80.976 47.045 81.528 ;
     RECT  46.897 83.616 47.077 91.752 ;
     RECT  46.541 92.784 47.077 95.112 ;
     RECT  46.793 68.064 47.189 79.896 ;
     RECT  46.253 57.36 47.276 65.448 ;
     RECT  46.217 67.008 47.276 67.032 ;
     RECT  47.276 57.36 47.317 67.032 ;
     RECT  47.189 68.064 47.317 78.696 ;
     RECT  46.933 96.24 47.509 96.936 ;
     RECT  47.045 81.12 47.545 81.528 ;
     RECT  45.965 82.56 47.545 82.584 ;
     RECT  47.077 83.616 47.581 95.112 ;
     RECT  46.901 45.408 47.893 45.576 ;
     RECT  46.793 50.544 47.905 56.328 ;
     RECT  47.317 57.36 47.905 78.696 ;
     RECT  47.893 45.408 47.941 46.2 ;
     RECT  47.228 47.28 47.941 47.304 ;
     RECT  47.905 50.544 48.193 78.696 ;
     RECT  47.189 79.776 48.193 79.896 ;
     RECT  48.149 42.144 48.308 42.168 ;
     RECT  46.901 43.536 48.308 44.232 ;
     RECT  47.941 45.408 48.308 47.304 ;
     RECT  45.904 48.432 48.308 48.456 ;
     RECT  48.193 50.544 48.308 79.896 ;
     RECT  47.545 81.12 48.308 82.584 ;
     RECT  47.581 83.616 48.308 95.208 ;
     RECT  47.509 96.24 48.308 97.176 ;
     RECT  48.308 2.148 48.412 97.212 ;
     RECT  48.412 2.418 48.604 97.176 ;
     RECT  48.604 47.616 48.701 49.608 ;
     RECT  48.604 60.912 48.917 97.176 ;
     RECT  48.604 52.752 48.995 55.272 ;
     RECT  48.995 52.752 49.009 54.888 ;
     RECT  48.917 60.912 49.241 96.936 ;
     RECT  48.604 43.584 49.427 44.376 ;
     RECT  48.701 47.808 49.427 49.608 ;
     RECT  48.604 56.304 49.885 59.784 ;
     RECT  49.241 60.912 49.885 90.648 ;
     RECT  48.604 51.072 50.137 51.48 ;
     RECT  49.427 49.584 50.149 49.608 ;
     RECT  50.137 51.072 50.149 51.528 ;
     RECT  49.009 52.752 50.209 54.84 ;
     RECT  49.241 91.632 50.533 96.936 ;
     RECT  50.149 49.584 50.677 51.528 ;
     RECT  50.209 52.752 50.677 55.272 ;
     RECT  49.885 56.304 50.713 90.648 ;
     RECT  50.533 91.632 50.713 97.176 ;
     RECT  49.427 48.384 51.008 48.456 ;
     RECT  50.677 49.584 51.008 55.272 ;
     RECT  50.713 56.304 51.008 97.176 ;
     RECT  51.008 2.148 51.112 97.212 ;
     RECT  51.112 2.418 51.116 97.212 ;
     RECT  51.116 2.418 51.203 97.32 ;
     RECT  51.203 2.418 51.304 96.942 ;
     RECT  51.304 86.496 51.437 96.936 ;
     RECT  51.304 60.912 51.581 66.264 ;
     RECT  51.304 82.8 51.581 85.416 ;
     RECT  51.581 60.912 51.689 65.544 ;
     RECT  51.304 67.296 51.689 81.672 ;
     RECT  51.304 55.536 51.941 59.784 ;
     RECT  51.304 50.16 52.211 54.408 ;
     RECT  51.689 67.296 52.229 73.032 ;
     RECT  51.304 49.008 52.259 49.032 ;
     RECT  52.229 67.296 52.297 72.936 ;
     RECT  51.437 86.496 52.297 94.632 ;
     RECT  51.437 95.616 52.301 96.936 ;
     RECT  51.689 74.064 52.333 81.672 ;
     RECT  52.211 50.16 52.337 51.48 ;
     RECT  51.581 82.8 52.369 84.888 ;
     RECT  52.297 67.248 52.477 72.936 ;
     RECT  52.477 66.912 52.481 72.936 ;
     RECT  52.333 74.064 52.513 81.72 ;
     RECT  52.369 82.752 52.513 84.888 ;
     RECT  52.297 86.208 52.517 94.632 ;
     RECT  51.689 60.912 52.693 65.496 ;
     RECT  52.481 66.912 52.693 69.528 ;
     RECT  52.517 86.208 52.765 94.44 ;
     RECT  52.301 95.712 52.933 96.936 ;
     RECT  52.211 52.464 52.981 54.408 ;
     RECT  52.513 74.064 53.089 84.888 ;
     RECT  51.941 55.536 53.269 56.76 ;
     RECT  51.941 57.888 53.269 59.784 ;
     RECT  53.089 74.064 53.269 84.984 ;
     RECT  52.765 85.968 53.269 94.44 ;
     RECT  52.981 52.464 53.305 54.456 ;
     RECT  53.305 51.936 53.341 54.456 ;
     RECT  52.933 95.712 53.341 97.176 ;
     RECT  52.693 60.912 53.449 69.528 ;
     RECT  52.481 70.56 53.449 72.936 ;
     RECT  53.341 51.936 53.485 54.504 ;
     RECT  53.269 55.536 53.485 59.784 ;
     RECT  53.449 60.912 53.485 72.936 ;
     RECT  53.269 74.064 53.485 94.44 ;
     RECT  53.485 51.936 53.593 59.784 ;
     RECT  53.593 51.744 53.665 59.784 ;
     RECT  53.485 60.912 53.665 94.44 ;
     RECT  52.337 50.16 53.708 50.76 ;
     RECT  53.665 51.744 53.708 94.44 ;
     RECT  53.341 95.472 53.708 97.176 ;
     RECT  53.708 2.148 53.812 97.212 ;
     RECT  53.812 2.418 54.004 97.212 ;
     RECT  54.004 56.784 54.137 84.696 ;
     RECT  54.004 85.728 54.245 91.704 ;
     RECT  54.004 51.744 54.281 54.168 ;
     RECT  54.137 56.784 54.281 66.648 ;
     RECT  54.004 92.688 54.281 95.976 ;
     RECT  54.004 97.152 54.317 97.212 ;
     RECT  54.281 56.784 54.323 64.104 ;
     RECT  54.137 67.92 54.371 84.696 ;
     RECT  54.245 85.728 54.389 90.552 ;
     RECT  54.281 65.184 54.419 66.648 ;
     RECT  54.371 67.92 54.497 72.552 ;
     RECT  54.281 92.688 54.569 94.92 ;
     RECT  54.004 55.44 54.641 55.464 ;
     RECT  54.323 56.976 54.641 64.104 ;
     RECT  54.493 98.064 54.803 98.088 ;
     RECT  54.281 51.744 54.857 53.352 ;
     RECT  54.389 85.728 54.893 90.408 ;
     RECT  54.371 73.536 54.929 84.696 ;
     RECT  54.497 71.136 55.037 72.552 ;
     RECT  54.419 65.184 55.285 65.496 ;
     RECT  54.497 67.92 55.285 70.104 ;
     RECT  54.893 89.76 55.289 90.408 ;
     RECT  54.641 56.976 55.325 63.576 ;
     RECT  54.997 98.592 55.379 98.616 ;
     RECT  55.289 90.048 55.429 90.408 ;
     RECT  54.245 91.68 55.753 91.704 ;
     RECT  54.929 83.808 55.813 84.696 ;
     RECT  54.893 85.728 55.813 88.728 ;
     RECT  54.419 66.528 55.825 66.648 ;
     RECT  55.285 67.872 55.825 70.104 ;
     RECT  55.037 71.136 55.861 72.36 ;
     RECT  55.325 57.024 55.933 63.576 ;
     RECT  55.285 64.992 55.933 65.496 ;
     RECT  55.429 90.048 55.969 90.6 ;
     RECT  55.753 91.68 55.969 91.752 ;
     RECT  54.569 92.736 56.365 94.92 ;
     RECT  54.281 95.904 56.365 95.976 ;
     RECT  54.857 51.744 56.408 51.768 ;
     RECT  54.857 53.088 56.408 53.352 ;
     RECT  55.609 54.432 56.408 54.456 ;
     RECT  55.933 57.024 56.408 65.496 ;
     RECT  55.825 66.528 56.408 70.104 ;
     RECT  55.861 71.088 56.408 72.36 ;
     RECT  54.929 73.536 56.408 82.536 ;
     RECT  55.813 83.808 56.408 88.728 ;
     RECT  55.969 90.048 56.408 91.752 ;
     RECT  56.365 92.736 56.408 95.976 ;
     RECT  55.957 97.152 56.408 97.176 ;
     RECT  56.408 2.148 56.512 97.212 ;
     RECT  56.512 2.418 56.54 97.212 ;
     RECT  56.54 2.418 56.627 97.32 ;
     RECT  56.627 2.418 56.704 96.942 ;
     RECT  56.704 52.992 56.819 53.016 ;
     RECT  56.704 57.072 56.837 59.784 ;
     RECT  56.704 68.16 56.86 72.264 ;
     RECT  56.704 73.488 57.377 88.92 ;
     RECT  56.704 54.096 57.521 55.56 ;
     RECT  56.837 57.312 57.593 59.784 ;
     RECT  56.704 60.912 57.629 66.792 ;
     RECT  57.521 54.624 57.701 55.56 ;
     RECT  57.377 73.776 57.737 88.92 ;
     RECT  56.704 89.952 57.841 91.704 ;
     RECT  56.704 92.688 57.841 95.736 ;
     RECT  57.841 89.952 57.881 95.736 ;
     RECT  57.701 54.672 57.913 55.56 ;
     RECT  57.913 54.672 57.953 55.752 ;
     RECT  57.629 60.912 57.953 64.152 ;
     RECT  57.629 65.232 58.057 66.792 ;
     RECT  57.737 79.728 58.061 88.92 ;
     RECT  58.057 65.232 58.357 67.08 ;
     RECT  56.86 68.16 58.357 70.104 ;
     RECT  56.86 71.088 58.357 72.264 ;
     RECT  57.737 73.776 58.357 78.696 ;
     RECT  58.061 84.048 58.453 88.92 ;
     RECT  57.881 89.952 58.453 95.112 ;
     RECT  58.357 65.232 58.655 70.104 ;
     RECT  58.357 71.088 58.655 78.696 ;
     RECT  58.453 84.048 58.849 95.112 ;
     RECT  56.704 96.912 58.981 96.936 ;
     RECT  57.953 55.728 59.101 55.752 ;
     RECT  58.655 65.232 59.101 78.696 ;
     RECT  57.953 54.672 59.108 54.696 ;
     RECT  59.101 55.68 59.108 55.752 ;
     RECT  57.593 57.408 59.108 59.784 ;
     RECT  57.953 60.912 59.108 63.912 ;
     RECT  59.101 64.896 59.108 78.696 ;
     RECT  58.061 79.728 59.108 83.064 ;
     RECT  58.849 84.048 59.108 95.784 ;
     RECT  58.981 96.912 59.108 97.32 ;
     RECT  59.108 2.148 59.212 97.32 ;
     RECT  59.212 2.418 59.404 97.32 ;
     RECT  59.404 84.048 59.465 89.016 ;
     RECT  59.404 96.912 59.533 97.32 ;
     RECT  59.404 90.096 59.609 95.784 ;
     RECT  59.533 96.912 59.617 97.464 ;
     RECT  59.404 63.072 59.645 74.664 ;
     RECT  59.609 90.096 59.933 94.68 ;
     RECT  59.645 63.072 60.113 69.768 ;
     RECT  59.645 70.752 60.275 74.664 ;
     RECT  59.404 57.024 60.329 59.784 ;
     RECT  59.404 75.744 60.397 82.968 ;
     RECT  59.404 54.048 60.419 55.704 ;
     RECT  59.933 90.096 60.467 94.584 ;
     RECT  60.419 54.048 60.473 55.56 ;
     RECT  59.465 85.968 60.613 89.016 ;
     RECT  60.467 90.096 60.613 94.44 ;
     RECT  60.329 57.024 60.653 58.248 ;
     RECT  59.617 96.912 60.757 96.936 ;
     RECT  60.329 59.232 60.793 59.784 ;
     RECT  59.404 60.912 60.793 61.992 ;
     RECT  60.397 75.744 60.793 83.064 ;
     RECT  59.465 84.048 60.793 84.888 ;
     RECT  60.113 63.072 60.796 69.672 ;
     RECT  60.796 63.072 60.901 65.496 ;
     RECT  60.793 59.232 61.225 61.992 ;
     RECT  60.901 63.024 61.225 65.496 ;
     RECT  59.404 52.944 61.513 52.968 ;
     RECT  60.796 66.768 61.513 69.672 ;
     RECT  60.275 70.752 61.513 72.84 ;
     RECT  60.613 85.968 61.621 94.44 ;
     RECT  61.117 95.664 61.621 95.688 ;
     RECT  61.513 52.944 61.693 53.016 ;
     RECT  60.473 54.048 61.693 55.224 ;
     RECT  61.693 52.944 61.808 55.224 ;
     RECT  60.653 57.024 61.808 58.152 ;
     RECT  61.225 59.232 61.808 65.496 ;
     RECT  61.513 66.768 61.808 72.84 ;
     RECT  60.275 74.4 61.808 74.664 ;
     RECT  60.793 75.744 61.808 84.888 ;
     RECT  61.621 85.968 61.808 95.688 ;
     RECT  60.757 96.912 61.808 97.176 ;
     RECT  61.808 2.148 61.912 97.212 ;
     RECT  61.912 2.418 62.005 97.212 ;
     RECT  62.005 2.418 62.104 97.32 ;
     RECT  62.104 91.68 62.129 97.32 ;
     RECT  62.104 69.264 62.201 69.576 ;
     RECT  62.104 72.24 62.243 90.648 ;
     RECT  62.104 52.992 62.345 55.272 ;
     RECT  62.243 72.24 62.381 72.456 ;
     RECT  62.345 52.992 62.525 54.744 ;
     RECT  62.243 73.488 62.525 90.648 ;
     RECT  62.525 77.088 62.561 90.648 ;
     RECT  62.104 57.6 62.669 60.648 ;
     RECT  62.669 58.128 62.849 60.648 ;
     RECT  62.525 53.52 62.957 54.744 ;
     RECT  62.129 91.68 63.029 96.936 ;
     RECT  62.561 77.088 63.065 84.696 ;
     RECT  62.104 61.92 63.137 64.392 ;
     RECT  62.201 69.312 63.277 69.576 ;
     RECT  62.957 53.952 63.299 54.744 ;
     RECT  62.381 72.336 63.301 72.456 ;
     RECT  62.525 73.488 63.301 76.056 ;
     RECT  63.301 72.336 63.353 76.056 ;
     RECT  62.104 65.472 63.493 65.496 ;
     RECT  62.104 66.576 63.493 68.28 ;
     RECT  63.353 72.48 63.493 76.056 ;
     RECT  63.065 77.088 63.493 78.696 ;
     RECT  63.029 95.712 63.497 96.936 ;
     RECT  63.299 53.952 63.533 54.696 ;
     RECT  63.497 95.904 63.565 96.936 ;
     RECT  63.493 65.472 63.709 68.28 ;
     RECT  63.277 69.312 63.709 70.056 ;
     RECT  63.065 79.728 63.709 84.696 ;
     RECT  62.561 85.68 63.709 90.648 ;
     RECT  62.849 58.128 63.733 60.6 ;
     RECT  63.733 57.312 63.74 60.6 ;
     RECT  63.74 57.216 63.829 60.6 ;
     RECT  63.137 61.92 63.829 63.912 ;
     RECT  63.709 65.472 63.925 70.056 ;
     RECT  63.565 95.904 63.997 97.176 ;
     RECT  63.709 79.728 64.172 90.648 ;
     RECT  63.029 91.68 64.172 94.632 ;
     RECT  63.925 64.896 64.177 70.056 ;
     RECT  63.277 71.184 64.177 71.208 ;
     RECT  63.997 95.904 64.451 98.088 ;
     RECT  63.493 72.48 64.465 78.696 ;
     RECT  63.829 57.216 64.501 63.912 ;
     RECT  63.533 54.336 64.508 54.696 ;
     RECT  64.501 56.256 64.508 63.912 ;
     RECT  64.177 64.896 64.508 71.208 ;
     RECT  64.465 72.432 64.508 78.696 ;
     RECT  64.172 79.728 64.508 94.632 ;
     RECT  64.451 95.904 64.508 97.212 ;
     RECT  64.508 2.148 64.612 97.212 ;
     RECT  64.612 2.418 64.804 97.176 ;
     RECT  64.804 56.256 64.931 58.152 ;
     RECT  64.931 57.024 64.972 58.152 ;
     RECT  64.804 77.472 64.973 78.744 ;
     RECT  64.804 67.584 65.045 76.056 ;
     RECT  64.804 59.232 65.081 64.392 ;
     RECT  64.973 77.568 65.117 78.744 ;
     RECT  65.045 67.584 65.189 70.728 ;
     RECT  64.804 95.904 65.189 97.176 ;
     RECT  64.804 79.776 65.261 81.96 ;
     RECT  65.117 77.952 65.333 78.744 ;
     RECT  64.804 54.672 65.405 54.696 ;
     RECT  64.804 83.616 65.507 94.584 ;
     RECT  64.972 57.312 65.555 58.152 ;
     RECT  65.189 68.112 65.555 70.728 ;
     RECT  65.555 57.456 65.621 57.48 ;
     RECT  65.045 71.808 65.621 76.056 ;
     RECT  65.581 97.44 65.665 97.464 ;
     RECT  65.081 59.232 65.747 61.656 ;
     RECT  65.507 90.048 65.837 94.584 ;
     RECT  65.261 79.776 65.945 81.768 ;
     RECT  65.747 60.816 66.089 61.656 ;
     RECT  65.189 95.904 66.181 96.264 ;
     RECT  65.081 62.736 66.221 64.392 ;
     RECT  64.804 65.76 66.221 66.456 ;
     RECT  65.621 73.344 66.229 76.056 ;
     RECT  65.333 77.952 66.229 78.696 ;
     RECT  66.221 62.736 66.233 66.456 ;
     RECT  66.233 63.216 66.265 66.456 ;
     RECT  65.555 68.112 66.265 70.152 ;
     RECT  65.621 71.808 66.301 71.832 ;
     RECT  65.507 83.616 66.301 88.92 ;
     RECT  66.229 73.344 66.337 76.728 ;
     RECT  66.229 77.904 66.337 78.696 ;
     RECT  66.337 73.344 66.469 78.696 ;
     RECT  65.945 79.776 66.469 81.672 ;
     RECT  65.837 90.336 66.517 94.584 ;
     RECT  66.181 95.904 66.517 96.936 ;
     RECT  66.469 73.344 66.589 81.672 ;
     RECT  66.301 71.232 66.733 71.832 ;
     RECT  66.589 72.912 66.733 81.672 ;
     RECT  66.517 90.336 66.805 96.936 ;
     RECT  66.265 63.216 66.841 70.152 ;
     RECT  66.733 71.232 66.841 81.672 ;
     RECT  65.747 59.232 67.208 59.832 ;
     RECT  66.089 60.816 67.208 60.936 ;
     RECT  66.841 63.216 67.208 81.672 ;
     RECT  66.301 83.232 67.208 88.92 ;
     RECT  66.805 90.336 67.208 97.176 ;
     RECT  67.208 2.148 67.312 97.212 ;
     RECT  67.312 2.418 67.381 97.212 ;
     RECT  67.381 2.418 67.504 97.32 ;
     RECT  67.504 96 67.601 97.32 ;
     RECT  67.504 66.816 67.619 69.528 ;
     RECT  67.504 77.952 67.804 79.8 ;
     RECT  67.619 66.816 67.817 69.336 ;
     RECT  67.504 88.176 67.853 94.872 ;
     RECT  67.504 61.008 67.889 61.032 ;
     RECT  67.804 77.952 67.961 78.744 ;
     RECT  67.504 59.568 68.003 59.784 ;
     RECT  67.504 62.256 68.105 64.728 ;
     RECT  67.504 72.288 68.236 76.968 ;
     RECT  67.504 70.56 68.249 70.584 ;
     RECT  67.601 96 68.285 96.936 ;
     RECT  67.817 68.928 68.321 69.336 ;
     RECT  67.853 88.176 68.357 89.352 ;
     RECT  68.236 74.832 68.501 76.968 ;
     RECT  67.817 66.816 68.533 67.704 ;
     RECT  68.285 96.24 68.716 96.936 ;
     RECT  68.105 62.304 68.785 64.728 ;
     RECT  68.533 66.72 68.825 67.704 ;
     RECT  68.825 66.768 68.861 67.704 ;
     RECT  68.785 62.304 68.915 65.592 ;
     RECT  68.501 75.168 68.917 76.968 ;
     RECT  67.961 77.952 68.917 78.696 ;
     RECT  67.853 90.336 68.917 94.872 ;
     RECT  67.804 79.776 68.965 79.8 ;
     RECT  67.504 80.976 68.965 87.096 ;
     RECT  68.236 72.288 69.013 73.272 ;
     RECT  68.965 79.776 69.081 87.096 ;
     RECT  68.357 88.176 69.081 88.728 ;
     RECT  69.013 71.808 69.217 73.272 ;
     RECT  69.145 97.44 69.251 97.464 ;
     RECT  68.321 69.312 69.325 69.336 ;
     RECT  68.917 75.168 69.397 78.696 ;
     RECT  69.081 79.776 69.397 88.728 ;
     RECT  68.497 70.656 69.469 70.68 ;
     RECT  69.397 75.168 69.5 88.728 ;
     RECT  69.325 69.312 69.505 69.672 ;
     RECT  69.469 70.656 69.505 70.824 ;
     RECT  69.217 71.808 69.541 73.512 ;
     RECT  69.505 69.312 69.649 70.824 ;
     RECT  69.649 68.352 69.685 70.824 ;
     RECT  69.541 71.808 69.685 74.088 ;
     RECT  69.5 75.12 69.721 88.728 ;
     RECT  68.917 89.712 69.721 94.872 ;
     RECT  68.861 66.768 69.901 67.272 ;
     RECT  69.685 68.352 69.901 74.088 ;
     RECT  68.003 59.76 69.908 59.784 ;
     RECT  68.915 62.304 69.908 64.248 ;
     RECT  69.901 66.768 69.908 74.088 ;
     RECT  69.721 75.12 69.908 94.872 ;
     RECT  68.716 96.24 69.908 96.264 ;
     RECT  69.829 97.344 69.908 97.368 ;
     RECT  69.908 2.148 69.916 97.368 ;
     RECT  69.916 2.148 70.012 97.212 ;
     RECT  70.012 2.418 70.204 96.942 ;
     RECT  70.204 65.328 70.595 65.352 ;
     RECT  70.204 88.464 70.595 90.648 ;
     RECT  70.204 68.112 70.625 74.088 ;
     RECT  70.625 68.112 70.697 73.512 ;
     RECT  70.595 88.464 70.697 89.16 ;
     RECT  70.697 68.112 70.769 68.952 ;
     RECT  70.204 75.936 70.769 78.792 ;
     RECT  26.489 0.288 70.787 0.312 ;
     RECT  70.204 96.144 70.841 96.936 ;
     RECT  70.595 90.624 70.913 90.648 ;
     RECT  70.769 68.4 70.949 68.952 ;
     RECT  70.204 82.656 71.233 87.288 ;
     RECT  71.233 82.608 71.269 87.288 ;
     RECT  70.697 88.464 71.269 88.728 ;
     RECT  70.769 75.936 71.273 78.696 ;
     RECT  71.273 75.936 71.317 77.4 ;
     RECT  70.949 68.88 71.381 68.952 ;
     RECT  70.204 79.776 71.381 80.568 ;
     RECT  70.204 81.6 71.485 81.624 ;
     RECT  70.697 70.608 71.597 73.512 ;
     RECT  70.204 66.912 71.603 66.936 ;
     RECT  71.381 68.928 71.603 68.952 ;
     RECT  71.597 70.8 71.603 73.512 ;
     RECT  71.603 71.232 71.633 73.512 ;
     RECT  70.204 91.68 71.701 94.968 ;
     RECT  71.273 78.672 71.881 78.696 ;
     RECT  70.841 96.912 72.188 96.936 ;
     RECT  71.381 79.776 72.205 80.376 ;
     RECT  71.881 78.672 72.277 78.744 ;
     RECT  72.205 79.728 72.277 80.376 ;
     RECT  71.269 82.608 72.421 88.728 ;
     RECT  72.277 78.672 72.469 80.376 ;
     RECT  71.485 81.552 72.469 81.624 ;
     RECT  72.421 82.608 72.469 88.92 ;
     RECT  71.701 91.68 72.469 95.064 ;
     RECT  70.204 59.76 72.608 59.784 ;
     RECT  71.633 71.232 72.608 73.32 ;
     RECT  71.317 75.216 72.608 77.4 ;
     RECT  72.469 78.672 72.608 81.624 ;
     RECT  72.469 82.608 72.608 89.496 ;
     RECT  72.469 91.056 72.608 95.064 ;
     RECT  72.188 96.912 72.608 97.176 ;
     RECT  72.608 2.148 72.712 97.212 ;
     RECT  72.712 2.418 72.805 97.212 ;
     RECT  72.805 2.418 72.904 97.32 ;
     RECT  72.904 92.688 72.965 97.32 ;
     RECT  72.904 71.952 73.073 73.32 ;
     RECT  72.965 92.688 73.289 96.936 ;
     RECT  72.904 78.048 73.505 85.176 ;
     RECT  73.289 96.912 73.516 96.936 ;
     RECT  72.904 86.592 73.577 91.08 ;
     RECT  73.289 92.688 73.613 95.784 ;
     RECT  73.073 71.952 73.649 72.936 ;
     RECT  73.505 78.048 73.685 85.032 ;
     RECT  73.685 78.048 74.045 80.088 ;
     RECT  72.904 76.032 74.077 76.824 ;
     RECT  74.053 97.152 74.14 97.176 ;
     RECT  73.577 87.072 74.153 91.08 ;
     RECT  73.649 71.952 74.297 72.168 ;
     RECT  74.153 90.48 74.297 91.08 ;
     RECT  73.613 92.688 74.401 94.968 ;
     RECT  74.077 75.264 74.761 76.824 ;
     RECT  74.045 78.048 74.761 78.696 ;
     RECT  74.045 79.728 74.869 80.088 ;
     RECT  73.685 81.312 74.869 85.032 ;
     RECT  74.401 92.208 74.876 94.968 ;
     RECT  74.876 92.208 74.941 95.064 ;
     RECT  74.221 73.536 75.157 73.608 ;
     RECT  74.869 79.728 75.229 85.032 ;
     RECT  75.085 86.016 75.229 86.04 ;
     RECT  74.581 96.912 75.253 96.936 ;
     RECT  72.904 59.76 75.308 59.784 ;
     RECT  74.297 72 75.308 72.168 ;
     RECT  75.157 73.248 75.308 73.608 ;
     RECT  74.761 75.12 75.308 78.696 ;
     RECT  75.229 79.728 75.308 86.04 ;
     RECT  74.153 87.072 75.308 89.496 ;
     RECT  74.297 90.48 75.308 90.648 ;
     RECT  74.941 92.208 75.308 95.784 ;
     RECT  75.253 96.912 75.308 97.368 ;
     RECT  75.308 2.148 75.412 97.368 ;
     RECT  75.412 2.418 75.557 97.368 ;
     RECT  75.557 2.418 75.604 97.176 ;
     RECT  75.604 80.832 75.629 80.952 ;
     RECT  75.604 75.936 75.665 76.008 ;
     RECT  75.604 82.416 75.701 90.552 ;
     RECT  75.604 92.832 75.737 95.784 ;
     RECT  75.604 73.248 75.845 73.608 ;
     RECT  75.604 77.568 75.845 79.8 ;
     RECT  75.701 82.416 75.875 90.36 ;
     RECT  75.604 96.912 75.989 97.176 ;
     RECT  75.875 82.416 76.019 88.968 ;
     RECT  75.665 75.936 76.025 75.96 ;
     RECT  76.019 82.416 76.025 88.632 ;
     RECT  76.025 82.512 76.097 88.632 ;
     RECT  76.097 82.512 76.241 88.488 ;
     RECT  75.737 92.832 76.241 94.824 ;
     RECT  75.845 77.568 76.307 79.272 ;
     RECT  76.241 86.784 76.313 88.488 ;
     RECT  76.241 82.512 76.403 85.512 ;
     RECT  75.989 96.912 76.54 96.936 ;
     RECT  76.403 82.512 76.601 84.984 ;
     RECT  76.241 93.024 76.601 94.824 ;
     RECT  75.629 80.928 76.957 80.952 ;
     RECT  76.313 86.784 76.961 87.816 ;
     RECT  76.813 98.592 77.075 98.616 ;
     RECT  76.307 77.568 77.209 79.224 ;
     RECT  75.875 90.048 77.317 90.36 ;
     RECT  76.961 86.784 77.389 87.72 ;
     RECT  77.317 90.048 77.425 90.888 ;
     RECT  76.601 93.024 77.569 94.44 ;
     RECT  76.601 82.512 77.857 82.536 ;
     RECT  76.601 83.76 77.893 84.984 ;
     RECT  75.604 59.76 78.008 59.784 ;
     RECT  77.509 72.336 78.008 72.36 ;
     RECT  76.597 73.776 78.008 73.8 ;
     RECT  77.469 74.976 78.008 75 ;
     RECT  77.209 76.848 78.008 79.224 ;
     RECT  76.957 80.688 78.008 80.952 ;
     RECT  77.857 82.224 78.008 82.536 ;
     RECT  77.893 83.76 78.008 85.512 ;
     RECT  77.389 86.64 78.008 87.72 ;
     RECT  77.425 89.28 78.008 90.888 ;
     RECT  77.569 92.16 78.008 94.44 ;
     RECT  77.533 95.664 78.008 95.688 ;
     RECT  77.605 96.912 78.008 96.936 ;
     RECT  78.008 2.148 78.112 97.212 ;
     RECT  78.112 2.418 78.229 97.212 ;
     RECT  78.229 2.418 78.304 97.32 ;
     RECT  78.304 95.664 78.365 95.88 ;
     RECT  78.304 96.912 78.365 97.32 ;
     RECT  78.304 73.152 78.509 73.512 ;
     RECT  78.304 88.08 78.515 91.128 ;
     RECT  78.304 78.432 78.689 79.224 ;
     RECT  78.689 78.432 78.707 78.696 ;
     RECT  78.509 73.488 78.833 73.512 ;
     RECT  78.304 74.64 78.833 76.872 ;
     RECT  78.304 84.048 78.833 85.512 ;
     RECT  78.515 91.104 78.833 91.128 ;
     RECT  78.833 75.408 78.905 76.872 ;
     RECT  78.515 88.08 78.941 89.448 ;
     RECT  78.365 95.856 79.013 95.88 ;
     RECT  78.905 75.408 79.187 76.392 ;
     RECT  78.707 78.624 79.187 78.696 ;
     RECT  78.304 81.072 79.187 81.096 ;
     RECT  79.187 75.408 79.229 75.432 ;
     RECT  78.304 82.08 79.484 82.968 ;
     RECT  78.833 84.048 79.484 85.416 ;
     RECT  78.365 96.912 79.516 96.936 ;
     RECT  78.304 92.16 79.729 94.44 ;
     RECT  78.941 88.08 79.981 89.016 ;
     RECT  79.484 82.08 80.053 85.416 ;
     RECT  79.729 91.728 80.233 94.44 ;
     RECT  80.233 91.152 80.305 94.44 ;
     RECT  79.187 78.672 80.333 78.696 ;
     RECT  79.981 87.744 80.341 89.016 ;
     RECT  79.801 86.592 80.593 86.616 ;
     RECT  80.341 87.744 80.593 89.208 ;
     RECT  80.053 97.152 80.636 97.176 ;
     RECT  78.304 59.76 80.708 59.784 ;
     RECT  80.333 78.672 80.708 80.04 ;
     RECT  80.053 81.312 80.708 85.416 ;
     RECT  80.593 86.592 80.708 89.208 ;
     RECT  80.305 91.152 80.708 94.584 ;
     RECT  79.873 95.616 80.708 95.64 ;
     RECT  80.636 97.152 80.708 97.368 ;
     RECT  80.708 2.148 80.812 97.368 ;
     RECT  80.812 2.418 81.004 97.368 ;
     RECT  81.004 96.912 81.425 97.368 ;
     RECT  81.004 83.76 81.461 85.416 ;
     RECT  81.004 86.592 81.533 95.208 ;
     RECT  81.533 90.048 81.569 95.208 ;
     RECT  81.004 82.176 81.605 82.536 ;
     RECT  81.533 87.12 81.605 88.968 ;
     RECT  81.605 82.512 81.641 82.536 ;
     RECT  81.569 92.928 81.965 95.208 ;
     RECT  81.965 92.928 82.145 94.632 ;
     RECT  81.605 88.08 82.253 88.872 ;
     RECT  81.569 90.048 82.253 91.752 ;
     RECT  82.253 90.048 82.289 91.608 ;
     RECT  81.461 84.336 82.357 85.416 ;
     RECT  82.357 84.336 82.397 85.512 ;
     RECT  81.673 97.44 82.499 97.464 ;
     RECT  82.145 93.024 83.173 94.632 ;
     RECT  82.253 88.08 83.221 88.728 ;
     RECT  81.004 59.76 83.408 59.784 ;
     RECT  83.269 81.792 83.408 81.816 ;
     RECT  83.269 83.376 83.408 83.544 ;
     RECT  82.397 84.912 83.408 85.512 ;
     RECT  83.221 86.592 83.408 86.616 ;
     RECT  83.221 88.08 83.408 88.92 ;
     RECT  82.289 90.048 83.408 90.072 ;
     RECT  83.173 93.024 83.408 94.872 ;
     RECT  82.537 96.144 83.408 96.168 ;
     RECT  83.077 97.152 83.408 97.212 ;
     RECT  83.408 2.148 83.512 97.212 ;
     RECT  83.512 2.418 83.653 97.212 ;
     RECT  83.653 2.418 83.704 97.464 ;
     RECT  83.704 83.52 83.765 83.544 ;
     RECT  83.704 97.152 83.765 97.464 ;
     RECT  83.704 90.048 83.837 90.552 ;
     RECT  83.837 90.528 83.843 90.552 ;
     RECT  83.704 82.128 83.873 82.152 ;
     RECT  83.704 84.912 83.873 87.144 ;
     RECT  83.873 84.912 84.053 84.936 ;
     RECT  83.873 85.92 84.131 87.144 ;
     RECT  83.704 93.024 84.179 94.872 ;
     RECT  83.765 97.152 84.323 97.176 ;
     RECT  84.764 88.8 84.805 88.824 ;
     RECT  84.179 93.216 84.845 94.872 ;
     RECT  84.805 88.8 84.851 89.544 ;
     RECT  84.845 93.312 85.057 94.872 ;
     RECT  84.853 96.912 86.101 96.936 ;
     RECT  83.704 59.76 86.108 59.784 ;
     RECT  84.131 87.12 86.108 87.144 ;
     RECT  84.851 89.52 86.108 89.544 ;
     RECT  85.057 93.312 86.108 95.736 ;
     RECT  86.101 96.912 86.108 97.368 ;
     RECT  86.108 2.148 86.212 97.368 ;
     RECT  86.212 2.418 86.404 97.368 ;
     RECT  86.404 89.52 86.609 89.544 ;
     RECT  86.404 92.88 86.641 97.368 ;
     RECT  86.641 92.88 86.725 97.464 ;
     RECT  86.725 92.88 86.861 96.936 ;
     RECT  86.861 96.912 87.347 96.936 ;
     RECT  86.861 92.88 87.653 95.208 ;
     RECT  87.653 93.456 87.833 95.208 ;
     RECT  87.829 97.44 87.923 97.464 ;
     RECT  86.404 59.76 88.808 59.784 ;
     RECT  87.833 93.456 88.808 94.872 ;
     RECT  88.501 96.912 88.808 97.212 ;
     RECT  88.808 2.148 88.912 97.212 ;
     RECT  88.912 2.418 89.077 97.212 ;
     RECT  89.077 2.418 89.104 97.32 ;
     RECT  89.104 97.296 89.201 97.32 ;
     RECT  89.665 97.44 89.749 97.464 ;
     RECT  89.104 93.504 90.277 95.784 ;
     RECT  90.277 92.64 90.317 95.784 ;
     RECT  89.104 91.152 90.323 91.176 ;
     RECT  90.317 92.64 90.364 95.736 ;
     RECT  90.277 96.912 90.364 96.936 ;
     RECT  90.86 97.152 91.465 97.176 ;
     RECT  89.104 59.76 91.508 59.784 ;
     RECT  90.364 93.504 91.508 95.736 ;
     RECT  91.465 97.152 91.508 97.368 ;
     RECT  91.508 2.148 91.571 97.368 ;
     RECT  91.571 2.148 91.612 97.212 ;
     RECT  91.612 2.418 91.804 97.176 ;
     RECT  91.804 93.792 91.937 94.296 ;
     RECT  91.804 97.152 92.297 97.176 ;
     RECT  91.804 59.76 92.771 59.784 ;
     RECT  91.937 94.272 92.981 94.296 ;
     RECT  94.208 2.148 94.312 97.212 ;
     RECT  94.312 2.418 94.504 96.942 ;
    LAYER M5 ;
     RECT  13.872 0.181 13.896 2.137 ;
     RECT  2.4 2.137 2.52 2.151 ;
     RECT  5.1 2.137 5.22 2.151 ;
     RECT  7.8 2.137 7.92 2.151 ;
     RECT  10.5 2.137 10.62 2.151 ;
     RECT  15.9 2.137 16.02 2.151 ;
     RECT  18.6 2.137 18.72 2.151 ;
     RECT  21.3 2.137 21.42 2.151 ;
     RECT  24 2.137 24.12 2.151 ;
     RECT  26.7 2.137 26.82 2.151 ;
     RECT  29.4 2.137 29.52 2.151 ;
     RECT  32.1 2.137 32.22 2.151 ;
     RECT  34.8 2.137 34.92 2.151 ;
     RECT  37.5 2.137 37.62 2.151 ;
     RECT  40.2 2.137 40.32 2.151 ;
     RECT  42.9 2.137 43.02 2.151 ;
     RECT  45.6 2.137 45.72 2.151 ;
     RECT  48.3 2.137 48.42 2.151 ;
     RECT  51 2.137 51.12 2.151 ;
     RECT  53.7 2.137 53.82 2.151 ;
     RECT  56.4 2.137 56.52 2.151 ;
     RECT  59.1 2.137 59.22 2.151 ;
     RECT  61.8 2.137 61.92 2.151 ;
     RECT  64.5 2.137 64.62 2.151 ;
     RECT  67.2 2.137 67.32 2.151 ;
     RECT  69.9 2.137 70.02 2.151 ;
     RECT  72.6 2.137 72.72 2.151 ;
     RECT  75.3 2.137 75.42 2.151 ;
     RECT  78 2.137 78.12 2.151 ;
     RECT  80.7 2.137 80.82 2.151 ;
     RECT  83.4 2.137 83.52 2.151 ;
     RECT  86.1 2.137 86.22 2.151 ;
     RECT  88.8 2.137 88.92 2.151 ;
     RECT  91.5 2.137 91.62 2.151 ;
     RECT  94.2 2.137 94.32 2.151 ;
     RECT  7.8 2.151 8.112 5.605 ;
     RECT  3.888 4.837 3.912 5.699 ;
     RECT  2.4 2.151 2.712 6.661 ;
     RECT  2.4 6.661 3.432 7.427 ;
     RECT  5.1 2.151 5.412 8.341 ;
     RECT  7.632 5.605 8.112 9.061 ;
     RECT  2.4 7.427 3.192 10.405 ;
     RECT  6.528 10.309 6.552 10.499 ;
     RECT  7.632 9.061 9.096 11.365 ;
     RECT  2.4 10.405 3.528 12.227 ;
     RECT  7.104 11.365 9.096 13.331 ;
     RECT  7.152 13.331 9.096 15.061 ;
     RECT  7.104 15.061 9.096 16.019 ;
     RECT  6.576 16.069 6.6 16.403 ;
     RECT  3.696 17.989 3.72 18.709 ;
     RECT  3.696 18.709 3.96 18.755 ;
     RECT  3.936 18.755 3.96 19.331 ;
     RECT  5.1 8.341 5.544 19.333 ;
     RECT  24 2.151 24.312 19.621 ;
     RECT  5.1 19.333 5.592 19.907 ;
     RECT  21.3 2.151 21.612 21.637 ;
     RECT  5.1 19.907 5.544 21.685 ;
     RECT  13.2 2.137 13.896 22.165 ;
     RECT  4.56 21.685 5.544 22.645 ;
     RECT  6.768 17.605 6.792 22.837 ;
     RECT  7.8 16.019 9.096 22.837 ;
     RECT  6.768 22.837 9.096 22.979 ;
     RECT  4.56 22.645 5.592 23.221 ;
     RECT  21.3 21.637 22.152 23.315 ;
     RECT  21.3 23.315 21.612 23.317 ;
     RECT  13.2 22.165 14.088 23.747 ;
     RECT  6.864 22.979 9.096 24.563 ;
     RECT  17.184 23.845 17.208 24.659 ;
     RECT  4.176 23.221 5.592 24.899 ;
     RECT  4.176 24.899 5.544 25.187 ;
     RECT  13.2 23.747 13.896 25.621 ;
     RECT  7.8 24.563 9.096 26.197 ;
     RECT  13.2 25.621 14.616 26.291 ;
     RECT  20.4 23.317 21.612 26.725 ;
     RECT  22.704 23.893 22.728 26.725 ;
     RECT  6.864 26.197 9.096 26.771 ;
     RECT  20.4 26.725 22.728 26.771 ;
     RECT  5.1 25.187 5.544 26.773 ;
     RECT  10.5 2.151 10.812 27.013 ;
     RECT  12.192 24.229 12.216 27.013 ;
     RECT  10.5 27.013 12.216 27.059 ;
     RECT  26.7 2.151 27.012 27.205 ;
     RECT  4.032 25.669 4.056 27.301 ;
     RECT  3.984 27.301 4.056 27.637 ;
     RECT  5.1 26.773 5.688 27.637 ;
     RECT  29.4 2.151 29.712 27.781 ;
     RECT  20.4 26.771 22.296 27.877 ;
     RECT  6.768 27.877 6.792 28.405 ;
     RECT  7.8 26.771 9.096 28.405 ;
     RECT  2.4 12.227 2.712 28.453 ;
     RECT  3.984 27.637 5.688 28.453 ;
     RECT  20.4 27.877 22.44 28.501 ;
     RECT  13.2 26.291 13.896 28.933 ;
     RECT  28.512 27.781 29.712 29.027 ;
     RECT  29.4 29.027 29.712 29.029 ;
     RECT  20.352 28.501 22.44 29.075 ;
     RECT  13.104 28.933 13.896 29.077 ;
     RECT  15.9 2.151 16.212 29.605 ;
     RECT  6.768 28.405 9.096 29.651 ;
     RECT  20.352 29.075 21.612 29.699 ;
     RECT  13.008 29.077 14.424 29.795 ;
     RECT  13.008 29.795 13.896 30.323 ;
     RECT  7.68 29.651 9.096 30.803 ;
     RECT  2.4 28.453 5.688 30.851 ;
     RECT  24 19.621 25.176 30.851 ;
     RECT  26.208 27.205 27.012 30.947 ;
     RECT  24 30.851 25.08 31.189 ;
     RECT  32.1 2.151 32.412 31.285 ;
     RECT  15.9 29.605 16.44 31.381 ;
     RECT  26.7 30.947 27.012 31.765 ;
     RECT  2.4 30.851 3.624 31.861 ;
     RECT  4.608 30.851 5.688 31.861 ;
     RECT  18.6 2.151 18.912 31.909 ;
     RECT  20.4 29.699 21.612 31.909 ;
     RECT  7.8 30.803 9.096 32.149 ;
     RECT  2.4 31.861 5.688 32.339 ;
     RECT  10.5 27.059 11.784 32.341 ;
     RECT  7.392 32.149 9.096 32.437 ;
     RECT  10.368 32.341 11.784 32.437 ;
     RECT  29.4 29.029 29.832 32.485 ;
     RECT  18.6 31.909 21.612 32.531 ;
     RECT  15.9 31.381 16.536 32.963 ;
     RECT  26.7 31.765 27.336 32.963 ;
     RECT  29.4 32.485 30.216 33.059 ;
     RECT  31.344 31.285 32.412 33.059 ;
     RECT  7.2 32.437 11.784 33.155 ;
     RECT  21.3 32.531 21.612 33.349 ;
     RECT  2.4 32.339 5.412 33.589 ;
     RECT  23.616 31.189 25.08 33.589 ;
     RECT  26.7 32.963 27.012 33.589 ;
     RECT  7.296 33.155 11.784 34.355 ;
     RECT  23.616 33.589 25.128 34.357 ;
     RECT  29.4 33.059 29.832 34.357 ;
     RECT  26.16 33.589 27.012 34.741 ;
     RECT  26.16 34.741 27.816 34.931 ;
     RECT  18.6 32.531 20.232 34.979 ;
     RECT  34.8 2.151 35.112 35.029 ;
     RECT  21.3 33.349 22.104 35.221 ;
     RECT  23.184 34.357 25.128 35.221 ;
     RECT  21.3 35.221 25.128 35.363 ;
     RECT  26.7 34.931 27.816 35.459 ;
     RECT  29.28 34.357 29.832 35.459 ;
     RECT  7.392 34.355 11.784 35.653 ;
     RECT  33.936 35.029 35.112 35.701 ;
     RECT  21.3 35.363 22.44 35.795 ;
     RECT  21.3 35.795 22.104 35.843 ;
     RECT  33.936 35.701 35.208 35.843 ;
     RECT  18.6 34.979 18.912 35.845 ;
     RECT  7.392 35.653 11.976 36.133 ;
     RECT  13.2 30.323 13.896 36.133 ;
     RECT  2.4 33.589 6.312 36.421 ;
     RECT  7.392 36.133 13.896 36.421 ;
     RECT  37.5 2.151 37.812 36.421 ;
     RECT  23.616 35.363 25.128 36.469 ;
     RECT  23.328 36.469 25.656 36.515 ;
     RECT  37.344 36.421 37.812 36.517 ;
     RECT  29.4 35.459 29.832 36.565 ;
     RECT  29.232 36.565 29.832 36.707 ;
     RECT  2.4 36.421 13.896 36.755 ;
     RECT  7.2 36.755 13.896 36.851 ;
     RECT  26.7 35.459 27.012 36.901 ;
     RECT  40.2 2.151 40.512 36.949 ;
     RECT  29.4 36.707 29.832 36.997 ;
     RECT  39.936 36.949 40.512 37.045 ;
     RECT  18.144 35.845 18.912 37.091 ;
     RECT  34.8 35.843 35.208 37.091 ;
     RECT  39.936 37.045 40.632 37.091 ;
     RECT  23.328 36.515 24.312 37.139 ;
     RECT  32.1 33.059 32.412 37.141 ;
     RECT  31.968 37.141 32.412 37.429 ;
     RECT  20.208 34.979 20.232 37.573 ;
     RECT  21.3 35.843 21.612 37.573 ;
     RECT  23.616 37.139 24.312 37.573 ;
     RECT  25.632 36.515 25.656 37.573 ;
     RECT  26.7 36.901 27.144 37.573 ;
     RECT  11.952 36.851 13.896 37.619 ;
     RECT  36.48 36.517 37.812 37.621 ;
     RECT  36.48 37.621 38.472 37.859 ;
     RECT  22.608 37.669 22.632 37.955 ;
     RECT  23.616 37.573 25.656 38.003 ;
     RECT  7.2 36.851 10.812 38.005 ;
     RECT  15.9 32.963 16.488 38.149 ;
     RECT  42.9 2.151 43.212 38.149 ;
     RECT  34.8 37.091 35.112 38.245 ;
     RECT  37.5 37.859 38.472 38.387 ;
     RECT  40.2 37.091 40.632 38.387 ;
     RECT  40.2 38.387 40.512 38.389 ;
     RECT  23.616 38.003 24.312 38.677 ;
     RECT  42.72 38.149 43.212 38.725 ;
     RECT  36.48 37.859 36.504 38.819 ;
     RECT  26.7 37.573 27.96 38.963 ;
     RECT  42.72 38.725 43.464 39.061 ;
     RECT  15.9 38.149 16.968 39.301 ;
     RECT  18.6 37.091 18.912 39.301 ;
     RECT  23.184 38.677 24.312 39.301 ;
     RECT  25.632 38.003 25.656 39.301 ;
     RECT  20.208 37.573 21.612 39.395 ;
     RECT  31.632 37.429 32.412 39.395 ;
     RECT  12.528 37.619 13.896 39.443 ;
     RECT  15.216 39.301 16.968 39.493 ;
     RECT  23.184 39.301 25.656 39.635 ;
     RECT  42.72 39.061 43.944 39.827 ;
     RECT  29.4 36.997 30.216 39.877 ;
     RECT  23.184 39.635 24.792 39.923 ;
     RECT  42.9 39.827 43.944 39.923 ;
     RECT  34.8 38.245 35.208 40.019 ;
     RECT  42.9 39.923 43.464 40.067 ;
     RECT  38.88 39.013 38.904 40.213 ;
     RECT  40.08 38.389 40.512 40.213 ;
     RECT  18.336 39.301 18.912 40.259 ;
     RECT  38.88 40.213 40.512 40.259 ;
     RECT  15.216 39.493 17.112 40.307 ;
     RECT  39.312 40.259 40.512 40.405 ;
     RECT  7.056 38.005 10.812 40.499 ;
     RECT  2.4 36.755 5.412 40.933 ;
     RECT  13.2 39.443 13.896 40.981 ;
     RECT  45.6 2.151 45.912 40.981 ;
     RECT  15.216 40.307 16.488 41.075 ;
     RECT  29.28 39.877 30.312 41.075 ;
     RECT  31.968 39.395 32.412 41.221 ;
     RECT  39.312 40.405 41.208 41.459 ;
     RECT  12.384 40.981 13.896 41.509 ;
     RECT  12 41.509 13.896 41.555 ;
     RECT  7.2 40.499 10.812 41.651 ;
     RECT  21.12 39.395 21.612 41.651 ;
     RECT  42.9 40.067 43.368 41.651 ;
     RECT  29.28 41.075 30.216 41.749 ;
     RECT  29.232 41.749 30.216 41.941 ;
     RECT  18.6 40.259 18.912 42.085 ;
     RECT  19.92 41.221 19.944 42.085 ;
     RECT  23.616 39.923 24.792 42.133 ;
     RECT  26.7 38.963 27.012 42.133 ;
     RECT  42.9 41.651 43.212 42.133 ;
     RECT  48.3 2.151 48.612 42.133 ;
     RECT  2.4 40.933 5.592 42.179 ;
     RECT  31.92 41.221 32.412 42.227 ;
     RECT  33.552 41.893 33.576 42.659 ;
     RECT  13.2 41.555 13.896 42.661 ;
     RECT  36.288 40.981 36.312 42.803 ;
     RECT  12 41.555 12.024 42.851 ;
     RECT  29.088 41.941 30.216 43.139 ;
     RECT  7.68 41.651 10.812 43.237 ;
     RECT  15.9 41.075 16.488 43.285 ;
     RECT  18.6 42.085 19.944 43.285 ;
     RECT  37.5 38.387 37.812 43.285 ;
     RECT  23.616 42.133 27.012 43.379 ;
     RECT  48.192 42.133 48.612 43.525 ;
     RECT  47.904 43.525 48.612 43.573 ;
     RECT  45.504 40.981 45.912 43.667 ;
     RECT  13.2 42.661 14.712 43.715 ;
     RECT  42.144 42.133 43.212 43.907 ;
     RECT  37.5 43.285 38.184 44.099 ;
     RECT  34.8 40.019 35.112 44.245 ;
     RECT  24 43.379 27.012 44.341 ;
     RECT  39.312 41.459 40.512 44.341 ;
     RECT  29.088 43.139 29.712 44.435 ;
     RECT  21.3 41.651 21.612 44.437 ;
     RECT  18.6 43.285 19.992 44.627 ;
     RECT  24 44.341 27.384 44.867 ;
     RECT  45.6 43.667 45.912 44.869 ;
     RECT  6.528 42.421 6.552 44.915 ;
     RECT  15.9 43.285 17.4 44.915 ;
     RECT  24 44.867 24.504 44.965 ;
     RECT  26.7 44.867 27.384 44.965 ;
     RECT  23.616 44.965 24.504 45.203 ;
     RECT  39.312 44.341 41.304 45.683 ;
     RECT  21.3 44.437 22.104 45.829 ;
     RECT  20.496 45.829 22.104 45.923 ;
     RECT  15.9 44.915 16.488 46.117 ;
     RECT  37.5 44.099 37.812 46.165 ;
     RECT  47.904 43.573 49.416 46.211 ;
     RECT  42.528 43.907 43.212 46.405 ;
     RECT  37.5 46.165 38.232 46.693 ;
     RECT  39.312 45.683 40.512 46.693 ;
     RECT  45.264 44.869 45.912 46.693 ;
     RECT  23.616 45.203 24.312 46.741 ;
     RECT  20.496 45.923 21.612 46.787 ;
     RECT  34.224 44.245 35.112 46.787 ;
     RECT  48 46.211 49.416 47.171 ;
     RECT  15.552 46.117 16.488 47.173 ;
     RECT  23.616 46.741 24.408 47.269 ;
     RECT  44.304 46.693 45.912 47.363 ;
     RECT  23.616 47.269 24.6 47.365 ;
     RECT  37.5 46.693 40.512 47.509 ;
     RECT  42.144 46.405 43.212 47.555 ;
     RECT  15.552 47.173 17.112 47.651 ;
     RECT  18.6 44.627 19.176 47.651 ;
     RECT  25.632 46.885 25.656 47.699 ;
     RECT  22.656 47.365 24.6 47.747 ;
     RECT  26.7 44.965 27.48 47.747 ;
     RECT  21.3 46.787 21.612 47.941 ;
     RECT  23.616 47.747 24.6 48.229 ;
     RECT  15.9 47.651 17.112 48.275 ;
     RECT  51 2.151 51.312 48.373 ;
     RECT  31.968 42.227 32.412 48.421 ;
     RECT  42.528 47.555 43.212 48.421 ;
     RECT  47.28 47.269 47.304 48.467 ;
     RECT  37.5 47.509 41.016 48.659 ;
     RECT  6.624 47.269 6.648 48.661 ;
     RECT  7.68 43.237 11.16 48.661 ;
     RECT  6.624 48.661 11.16 48.707 ;
     RECT  34.8 46.787 35.112 48.805 ;
     RECT  20.64 47.941 21.612 48.947 ;
     RECT  50.832 48.373 51.312 48.997 ;
     RECT  23.616 48.229 25.128 49.091 ;
     RECT  42.528 48.421 43.992 49.091 ;
     RECT  2.4 42.179 5.412 49.381 ;
     RECT  6.624 48.707 10.812 49.381 ;
     RECT  18.6 47.651 19.128 49.523 ;
     RECT  26.7 47.747 27.336 49.525 ;
     RECT  45.264 47.363 45.912 49.573 ;
     RECT  48.3 47.171 49.416 49.619 ;
     RECT  13.2 43.715 13.896 49.715 ;
     RECT  34.8 48.805 35.304 49.811 ;
     RECT  37.5 48.659 40.512 50.051 ;
     RECT  13.2 49.715 13.512 50.053 ;
     RECT  50.832 48.997 52.248 50.149 ;
     RECT  26.112 49.525 27.336 50.389 ;
     RECT  29.232 44.435 29.712 50.389 ;
     RECT  29.232 50.389 30.456 50.435 ;
     RECT  21.12 48.947 21.612 50.531 ;
     RECT  45.168 49.573 45.912 50.533 ;
     RECT  15.9 48.275 16.44 50.677 ;
     RECT  50.16 50.149 52.248 51.107 ;
     RECT  18.6 49.523 19.08 51.203 ;
     RECT  26.112 50.389 27.816 51.203 ;
     RECT  2.4 49.381 10.812 51.347 ;
     RECT  34.8 49.811 35.112 51.349 ;
     RECT  2.4 51.347 6.264 51.491 ;
     RECT  45.024 50.533 45.912 51.539 ;
     RECT  15.408 50.677 16.44 51.637 ;
     RECT  29.4 50.435 30.456 51.637 ;
     RECT  31.872 48.421 32.412 51.637 ;
     RECT  7.296 51.347 10.812 51.923 ;
     RECT  33.6 51.109 33.624 51.923 ;
     RECT  7.68 51.923 10.812 52.021 ;
     RECT  23.616 49.091 24.6 52.165 ;
     RECT  34.8 51.349 35.88 52.211 ;
     RECT  29.4 51.637 32.412 52.405 ;
     RECT  21.3 50.531 21.612 52.453 ;
     RECT  28.464 52.405 32.412 52.499 ;
     RECT  7.68 52.021 11.64 52.739 ;
     RECT  2.4 51.491 5.544 52.883 ;
     RECT  20.64 52.453 21.612 52.981 ;
     RECT  48.3 49.619 48.612 52.981 ;
     RECT  56.4 2.151 56.712 52.981 ;
     RECT  13.104 50.053 13.512 53.027 ;
     RECT  37.5 50.051 37.944 53.075 ;
     RECT  45.168 51.539 45.912 53.075 ;
     RECT  45.264 53.075 45.912 53.411 ;
     RECT  15.408 51.637 17.4 53.461 ;
     RECT  7.68 52.739 10.812 53.509 ;
     RECT  34.8 52.211 35.112 53.557 ;
     RECT  28.464 52.499 30.456 54.083 ;
     RECT  7.392 53.509 10.812 54.085 ;
     RECT  15.312 53.461 17.4 54.085 ;
     RECT  18.6 51.203 18.912 54.085 ;
     RECT  23.616 52.165 25.128 54.085 ;
     RECT  56.4 52.981 56.808 54.131 ;
     RECT  48.3 52.981 49.272 54.371 ;
     RECT  20.496 52.981 21.612 54.421 ;
     RECT  23.04 54.085 25.128 54.421 ;
     RECT  34.128 53.557 35.112 54.469 ;
     RECT  33.84 54.469 35.112 54.613 ;
     RECT  63.264 53.941 63.288 54.661 ;
     RECT  64.5 2.151 64.812 54.661 ;
     RECT  45.312 53.411 45.912 54.709 ;
     RECT  6.528 54.085 10.812 54.755 ;
     RECT  63.264 54.661 64.92 54.755 ;
     RECT  2.4 52.883 5.412 55.237 ;
     RECT  26.112 51.203 27.012 55.237 ;
     RECT  28.464 54.083 30.36 55.237 ;
     RECT  50.832 51.107 52.248 55.237 ;
     RECT  7.392 54.755 10.812 55.283 ;
     RECT  48.3 54.371 48.984 55.283 ;
     RECT  15.312 54.085 18.912 55.427 ;
     RECT  20.496 54.421 25.128 55.475 ;
     RECT  33.84 54.613 35.976 55.475 ;
     RECT  13.2 53.027 13.512 55.525 ;
     RECT  50.592 55.237 52.248 55.525 ;
     RECT  23.184 55.475 25.128 55.667 ;
     RECT  42.528 49.091 43.212 55.861 ;
     RECT  23.184 55.667 24.696 55.907 ;
     RECT  50.592 55.525 52.728 55.955 ;
     RECT  31.872 52.499 32.412 56.003 ;
     RECT  15.312 55.427 17.4 56.051 ;
     RECT  26.112 55.237 30.36 56.099 ;
     RECT  37.5 53.075 37.812 56.101 ;
     RECT  45.312 54.709 46.296 56.243 ;
     RECT  33.84 55.475 35.496 56.387 ;
     RECT  42.48 55.861 43.212 56.387 ;
     RECT  48.3 55.283 48.612 56.389 ;
     RECT  50.592 55.955 52.248 56.483 ;
     RECT  27.984 56.099 30.36 56.531 ;
     RECT  50.592 56.483 51.312 56.531 ;
     RECT  53.7 2.151 54.012 56.773 ;
     RECT  29.28 56.531 30.36 56.965 ;
     RECT  45.312 56.243 45.912 56.965 ;
     RECT  53.7 56.773 54.312 56.965 ;
     RECT  48.3 56.389 48.936 57.011 ;
     RECT  15.9 56.051 17.4 57.059 ;
     RECT  44.496 56.965 45.912 57.059 ;
     RECT  60.384 54.565 60.408 57.059 ;
     RECT  12.528 55.525 13.512 57.107 ;
     RECT  15.9 57.059 17.112 57.107 ;
     RECT  63.792 54.755 64.92 57.301 ;
     RECT  33.84 56.387 35.112 57.347 ;
     RECT  20.496 55.475 21.612 57.349 ;
     RECT  27.984 56.531 28.008 57.587 ;
     RECT  37.5 56.101 38.232 57.827 ;
     RECT  29.28 56.965 30.504 58.115 ;
     RECT  32.1 56.003 32.412 58.117 ;
     RECT  45.6 57.059 45.912 58.117 ;
     RECT  63.744 57.301 65.544 58.163 ;
     RECT  20.496 57.349 21.768 58.403 ;
     RECT  37.5 57.827 37.812 58.405 ;
     RECT  15.9 57.107 17.064 58.501 ;
     RECT  15.9 58.501 17.592 58.547 ;
     RECT  44.496 57.059 44.52 58.643 ;
     RECT  29.28 58.115 30.36 58.691 ;
     RECT  63.744 58.163 64.812 58.883 ;
     RECT  12.048 57.445 12.072 58.979 ;
     RECT  50.832 56.531 51.312 59.029 ;
     RECT  59.1 2.151 59.412 59.029 ;
     RECT  13.2 57.107 13.512 59.221 ;
     RECT  24 55.907 24.696 59.221 ;
     RECT  67.2 2.151 67.512 59.221 ;
     RECT  23.136 59.221 24.696 59.269 ;
     RECT  14.736 59.029 14.76 59.461 ;
     RECT  15.9 58.547 16.44 59.461 ;
     RECT  58.128 59.029 59.412 59.461 ;
     RECT  63.792 58.883 64.812 59.509 ;
     RECT  42.528 56.387 43.212 59.557 ;
     RECT  66.288 59.221 67.512 59.557 ;
     RECT  14.736 59.461 16.44 59.699 ;
     RECT  15.9 59.699 16.44 59.749 ;
     RECT  17.568 58.547 17.592 59.749 ;
     RECT  29.28 58.691 29.928 59.749 ;
     RECT  63.792 59.509 65.016 59.749 ;
     RECT  66.288 59.557 67.992 59.749 ;
     RECT  91.5 2.151 91.812 59.749 ;
     RECT  58.128 59.461 59.88 59.795 ;
     RECT  63.792 59.749 67.992 59.795 ;
     RECT  23.136 59.269 24.792 59.891 ;
     RECT  63.792 59.795 67.512 59.891 ;
     RECT  29.136 59.749 29.928 59.987 ;
     RECT  39.312 50.051 40.512 59.989 ;
     RECT  45.6 58.117 46.488 60.275 ;
     RECT  14.736 59.699 14.76 60.371 ;
     RECT  34.8 57.347 35.112 60.373 ;
     RECT  39.264 59.989 40.512 60.373 ;
     RECT  50.736 59.029 51.312 60.419 ;
     RECT  37.008 58.405 37.812 60.421 ;
     RECT  53.28 56.965 54.312 60.517 ;
     RECT  31.968 58.117 32.412 60.563 ;
     RECT  36.48 60.421 37.812 60.659 ;
     RECT  13.2 59.221 13.656 60.707 ;
     RECT  2.4 55.237 6.12 60.805 ;
     RECT  38.88 60.373 40.512 60.995 ;
     RECT  42.096 59.557 43.212 61.043 ;
     RECT  58.128 59.795 59.784 61.043 ;
     RECT  63.84 59.891 67.512 61.091 ;
     RECT  20.496 58.403 21.612 61.189 ;
     RECT  20.496 61.189 22.104 61.333 ;
     RECT  34.272 60.373 35.112 61.379 ;
     RECT  24 59.891 24.792 61.477 ;
     RECT  61.8 2.151 62.112 61.477 ;
     RECT  56.4 54.131 56.712 61.525 ;
     RECT  2.4 60.805 6.264 61.571 ;
     RECT  20.352 61.333 22.104 61.763 ;
     RECT  29.28 59.987 29.928 62.101 ;
     RECT  56.4 61.525 57.576 62.101 ;
     RECT  45.6 60.275 45.912 62.293 ;
     RECT  56.304 62.101 57.576 62.435 ;
     RECT  2.4 61.571 5.976 62.483 ;
     RECT  20.496 61.763 22.104 62.531 ;
     RECT  42.528 61.043 43.212 62.533 ;
     RECT  61.584 61.477 62.112 62.579 ;
     RECT  7.8 55.283 10.812 62.581 ;
     RECT  28.752 62.101 29.928 62.581 ;
     RECT  15.9 59.749 17.592 62.723 ;
     RECT  53.28 60.517 54.696 62.723 ;
     RECT  37.5 60.659 37.812 62.821 ;
     RECT  45.6 62.293 46.008 62.867 ;
     RECT  23.232 61.477 24.792 63.011 ;
     RECT  42.528 62.533 43.464 63.011 ;
     RECT  45.6 62.867 45.912 63.061 ;
     RECT  47.04 62.293 47.064 63.107 ;
     RECT  13.2 60.707 13.512 63.109 ;
     RECT  44.976 63.061 45.912 63.109 ;
     RECT  21.3 62.531 22.104 63.253 ;
     RECT  28.752 62.581 30.744 63.299 ;
     RECT  56.304 62.435 56.712 63.491 ;
     RECT  28.752 63.299 29.832 63.539 ;
     RECT  17.568 62.723 17.592 63.781 ;
     RECT  18.6 55.427 18.912 63.781 ;
     RECT  24 63.011 24.792 63.781 ;
     RECT  26.112 56.099 27.012 63.781 ;
     RECT  32.1 60.563 32.412 63.781 ;
     RECT  44.88 63.109 45.912 63.781 ;
     RECT  61.8 62.579 62.112 63.781 ;
     RECT  64.272 61.091 67.512 63.781 ;
     RECT  39.216 60.995 40.512 63.827 ;
     RECT  37.5 62.821 37.944 63.829 ;
     RECT  2.4 62.483 5.412 63.875 ;
     RECT  29.28 63.539 29.832 63.875 ;
     RECT  15.9 62.723 16.584 64.163 ;
     RECT  61.584 63.781 62.112 64.403 ;
     RECT  21.3 63.253 22.2 64.499 ;
     RECT  36.48 60.659 36.504 64.595 ;
     RECT  59.1 61.043 59.784 64.693 ;
     RECT  48.3 57.011 48.612 64.885 ;
     RECT  44.448 63.781 45.912 64.979 ;
     RECT  17.568 63.781 18.912 65.027 ;
     RECT  24 63.781 27.012 65.075 ;
     RECT  34.8 61.379 35.112 65.125 ;
     RECT  47.328 64.885 48.612 65.173 ;
     RECT  44.88 64.979 45.912 65.219 ;
     RECT  2.4 63.875 2.712 65.269 ;
     RECT  47.328 65.173 49.56 65.269 ;
     RECT  69.9 2.151 70.212 65.317 ;
     RECT  21.3 64.499 22.104 65.509 ;
     RECT  34.8 65.125 35.208 65.509 ;
     RECT  68.88 62.293 68.904 65.603 ;
     RECT  59.1 64.693 60.744 65.845 ;
     RECT  13.2 63.109 14.088 65.939 ;
     RECT  44.976 65.219 45.912 65.939 ;
     RECT  26.16 65.075 27.012 65.941 ;
     RECT  29.28 63.875 29.712 66.085 ;
     RECT  58.368 65.845 60.744 66.227 ;
     RECT  7.536 62.581 10.812 66.229 ;
     RECT  53.28 62.723 54.408 66.275 ;
     RECT  45.024 65.939 45.912 66.323 ;
     RECT  7.296 66.229 10.812 66.325 ;
     RECT  34.8 65.509 35.832 66.515 ;
     RECT  37.5 63.829 38.184 66.515 ;
     RECT  24 65.075 24.792 66.661 ;
     RECT  26.16 65.941 27.96 66.661 ;
     RECT  4.272 63.875 5.412 66.755 ;
     RECT  6.864 66.325 11.688 66.755 ;
     RECT  13.2 65.939 13.704 66.805 ;
     RECT  12.768 66.805 13.704 66.947 ;
     RECT  69.9 65.317 70.584 66.947 ;
     RECT  45.36 66.323 45.912 66.997 ;
     RECT  47.136 65.269 49.56 66.997 ;
     RECT  13.2 66.947 13.704 67.187 ;
     RECT  24 66.661 27.96 67.235 ;
     RECT  6.864 66.755 9.096 67.283 ;
     RECT  37.5 66.515 37.944 67.283 ;
     RECT  64.224 63.781 67.512 67.283 ;
     RECT  21.3 65.509 22.92 67.285 ;
     RECT  45.36 66.997 49.56 67.331 ;
     RECT  58.368 66.227 59.784 67.475 ;
     RECT  15.9 64.163 16.44 67.669 ;
     RECT  2.4 65.269 3.048 67.765 ;
     RECT  39.312 63.827 40.512 67.765 ;
     RECT  42.528 63.011 43.212 67.765 ;
     RECT  32.1 63.781 32.76 67.813 ;
     RECT  39.312 67.765 43.212 67.813 ;
     RECT  24 67.235 27.012 67.859 ;
     RECT  45.36 67.331 47.16 68.099 ;
     RECT  58.704 67.475 59.784 68.099 ;
     RECT  32.1 67.813 33.384 68.101 ;
     RECT  38.784 67.813 43.212 68.147 ;
     RECT  20.16 63.205 20.184 68.341 ;
     RECT  21.168 67.285 22.92 68.341 ;
     RECT  51 60.419 51.312 68.341 ;
     RECT  69.9 66.947 70.212 68.341 ;
     RECT  29.232 66.085 29.712 68.389 ;
     RECT  15.36 67.669 16.44 68.435 ;
     RECT  24 67.859 24.792 68.435 ;
     RECT  38.784 68.147 40.512 68.627 ;
     RECT  41.616 68.147 43.212 68.627 ;
     RECT  2.4 67.765 3.432 68.675 ;
     RECT  26.16 67.859 27.012 68.917 ;
     RECT  20.16 68.341 22.92 68.965 ;
     RECT  24 68.435 24.504 68.965 ;
     RECT  29.136 68.389 29.712 68.965 ;
     RECT  37.5 67.283 37.812 68.965 ;
     RECT  2.4 68.675 3.048 69.011 ;
     RECT  53.28 66.275 54.012 69.109 ;
     RECT  13.2 67.187 13.512 69.205 ;
     RECT  53.04 69.109 54.012 69.251 ;
     RECT  37.5 68.965 37.944 69.253 ;
     RECT  45.36 68.099 45.912 69.299 ;
     RECT  18.6 65.027 18.912 69.349 ;
     RECT  20.16 68.965 24.504 69.349 ;
     RECT  26.16 68.917 27.144 69.349 ;
     RECT  46.992 68.099 47.16 69.349 ;
     RECT  61.8 64.403 62.112 69.349 ;
     RECT  45.456 69.299 45.912 69.395 ;
     RECT  53.568 69.251 54.012 69.445 ;
     RECT  55.008 68.917 55.032 69.445 ;
     RECT  53.568 69.445 55.032 69.491 ;
     RECT  6.864 67.283 8.112 69.493 ;
     RECT  15.9 68.435 16.44 69.493 ;
     RECT  17.568 65.027 17.592 69.493 ;
     RECT  18.6 69.349 24.504 69.493 ;
     RECT  67.2 67.283 67.512 69.493 ;
     RECT  17.568 69.493 24.504 69.539 ;
     RECT  56.4 63.491 56.712 69.541 ;
     RECT  32.1 68.101 33.432 69.587 ;
     RECT  30.864 63.781 30.888 69.731 ;
     RECT  69.792 68.341 70.212 69.779 ;
     RECT  51 68.341 51.864 69.875 ;
     RECT  10.5 66.755 11.688 69.973 ;
     RECT  26.112 69.349 27.144 70.021 ;
     RECT  25.824 70.021 27.144 70.067 ;
     RECT  2.4 69.011 2.712 70.117 ;
     RECT  15.792 69.493 16.44 70.163 ;
     RECT  37.392 69.253 37.944 70.213 ;
     RECT  51 69.875 51.312 70.213 ;
     RECT  17.568 69.539 22.92 70.259 ;
     RECT  6.864 69.493 8.856 70.307 ;
     RECT  56.4 69.541 56.808 70.547 ;
     RECT  59.1 68.099 59.784 70.549 ;
     RECT  67.2 69.493 67.608 70.595 ;
     RECT  6.864 70.307 8.568 70.739 ;
     RECT  64.224 67.283 65.544 70.739 ;
     RECT  24 69.539 24.504 70.789 ;
     RECT  25.824 70.067 27.012 70.789 ;
     RECT  13.2 69.205 13.704 70.835 ;
     RECT  2.4 70.117 2.952 71.075 ;
     RECT  30.96 70.021 30.984 71.077 ;
     RECT  69.9 69.779 70.212 71.173 ;
     RECT  71.568 66.901 71.592 71.173 ;
     RECT  69.9 71.173 71.592 71.267 ;
     RECT  18.6 70.259 22.92 71.315 ;
     RECT  37.392 70.213 38.04 71.315 ;
     RECT  29.088 68.965 29.712 71.363 ;
     RECT  17.568 70.259 17.592 71.459 ;
     RECT  10.5 69.973 12.024 71.461 ;
     RECT  50.112 70.213 51.312 71.461 ;
     RECT  10.368 71.461 12.024 71.605 ;
     RECT  13.2 70.835 13.512 71.605 ;
     RECT  18.6 71.315 20.184 71.651 ;
     RECT  24 70.789 27.012 71.699 ;
     RECT  39.312 68.627 40.512 71.797 ;
     RECT  69.9 71.267 70.68 71.797 ;
     RECT  72.6 2.151 72.912 71.797 ;
     RECT  61.008 69.349 62.112 71.891 ;
     RECT  39.312 71.797 40.824 72.037 ;
     RECT  7.584 70.739 8.568 72.277 ;
     RECT  14.736 71.413 14.76 72.325 ;
     RECT  15.9 70.163 16.44 72.325 ;
     RECT  46.992 69.349 47.208 72.325 ;
     RECT  48.3 67.331 48.612 72.325 ;
     RECT  56.4 70.547 56.712 72.325 ;
     RECT  64.224 70.739 64.812 72.325 ;
     RECT  78 2.151 78.312 72.325 ;
     RECT  4.944 66.755 5.412 72.419 ;
     RECT  30.816 71.077 30.984 72.419 ;
     RECT  26.7 71.699 27.012 72.421 ;
     RECT  71.808 71.797 72.912 72.659 ;
     RECT  5.1 72.419 5.412 72.709 ;
     RECT  14.736 72.325 16.44 72.757 ;
     RECT  26.7 72.421 27.336 72.803 ;
     RECT  50.112 71.461 51.912 72.805 ;
     RECT  61.8 71.891 62.112 72.805 ;
     RECT  69.024 71.797 70.68 72.851 ;
     RECT  24 71.699 25.08 72.901 ;
     RECT  58.704 70.549 59.784 72.901 ;
     RECT  50.112 72.805 52.248 72.947 ;
     RECT  29.232 71.363 29.712 72.949 ;
     RECT  67.2 70.595 67.512 72.949 ;
     RECT  69.024 72.851 70.212 72.949 ;
     RECT  7.584 72.277 8.664 72.995 ;
     RECT  63.312 72.325 64.812 73.043 ;
     RECT  67.2 72.949 70.212 73.283 ;
     RECT  7.584 72.995 8.112 73.285 ;
     RECT  14.736 72.757 17.304 73.379 ;
     RECT  28.896 72.949 29.712 73.475 ;
     RECT  24 72.901 25.176 73.477 ;
     RECT  34.8 66.515 35.112 73.477 ;
     RECT  39.312 72.037 41.16 73.477 ;
     RECT  42.528 68.627 43.212 73.477 ;
     RECT  58.368 72.901 59.784 73.477 ;
     RECT  61.8 72.805 62.232 73.477 ;
     RECT  63.312 73.043 63.336 73.477 ;
     RECT  67.2 73.283 68.184 73.477 ;
     RECT  61.8 73.477 63.336 73.523 ;
     RECT  37.5 71.315 38.04 73.571 ;
     RECT  30.96 72.419 30.984 73.765 ;
     RECT  32.1 69.587 33.384 73.765 ;
     RECT  45.6 69.395 45.912 73.765 ;
     RECT  46.992 72.325 48.612 73.765 ;
     RECT  21.3 71.315 22.92 73.813 ;
     RECT  24 73.477 25.224 73.813 ;
     RECT  5.1 72.709 5.544 74.005 ;
     RECT  7.44 73.285 8.112 74.051 ;
     RECT  66.24 73.477 68.184 74.051 ;
     RECT  56.304 72.325 56.712 74.053 ;
     RECT  34.8 73.477 35.928 74.099 ;
     RECT  20.064 71.651 20.184 74.101 ;
     RECT  21.3 73.813 25.224 74.101 ;
     RECT  10.368 71.605 13.512 74.147 ;
     RECT  45.6 73.765 48.612 74.147 ;
     RECT  61.8 73.523 62.952 74.147 ;
     RECT  20.064 74.101 25.224 74.339 ;
     RECT  39.312 73.477 43.212 74.533 ;
     RECT  39.312 74.533 43.8 74.579 ;
     RECT  58.368 73.477 60.264 74.579 ;
     RECT  7.632 74.051 8.112 74.677 ;
     RECT  48 74.147 48.612 74.677 ;
     RECT  30.96 73.765 33.384 74.723 ;
     RECT  3.744 72.229 3.768 74.915 ;
     RECT  20.496 74.339 25.224 74.965 ;
     RECT  26.7 72.803 27.012 74.965 ;
     RECT  56.016 74.053 56.712 74.965 ;
     RECT  77.52 72.325 78.312 75.011 ;
     RECT  29.232 73.475 29.712 75.013 ;
     RECT  58.368 74.579 59.784 75.013 ;
     RECT  30.96 74.723 33.288 75.059 ;
     RECT  66.24 74.051 67.608 75.157 ;
     RECT  61.8 74.147 62.616 75.205 ;
     RECT  48 74.677 49.08 75.251 ;
     RECT  71.328 73.381 71.352 75.251 ;
     RECT  61.8 75.205 63.24 75.347 ;
     RECT  78 75.011 78.312 75.397 ;
     RECT  28.608 75.013 29.712 75.539 ;
     RECT  45.6 74.147 46.824 75.539 ;
     RECT  64.5 73.043 64.812 75.541 ;
     RECT  30.96 75.059 32.412 75.683 ;
     RECT  13.2 74.147 13.512 75.685 ;
     RECT  34.8 74.099 35.112 75.781 ;
     RECT  37.5 73.571 37.812 75.781 ;
     RECT  55.872 74.965 56.712 75.781 ;
     RECT  55.872 75.781 56.904 75.827 ;
     RECT  15.264 73.379 17.304 75.875 ;
     RECT  7.632 74.677 8.808 75.923 ;
     RECT  10.368 74.147 11.688 75.973 ;
     RECT  10.368 75.973 12.12 76.019 ;
     RECT  13.2 75.685 13.608 76.069 ;
     RECT  2.4 71.075 2.712 76.309 ;
     RECT  29.232 75.539 29.712 76.357 ;
     RECT  30.96 75.683 30.984 76.357 ;
     RECT  39.312 74.579 41.16 76.357 ;
     RECT  42.528 74.579 43.8 76.357 ;
     RECT  53.568 69.491 54.744 76.357 ;
     RECT  20.496 74.965 27.012 76.403 ;
     RECT  58.224 75.013 59.784 76.403 ;
     RECT  78 75.397 79.176 76.403 ;
     RECT  20.496 76.403 25.272 76.451 ;
     RECT  69.552 73.283 70.212 76.499 ;
     RECT  29.232 76.357 30.984 76.501 ;
     RECT  66.24 75.157 68.424 76.643 ;
     RECT  66.24 76.643 67.608 76.739 ;
     RECT  37.5 75.781 38.232 76.787 ;
     RECT  18.6 71.651 19.08 76.789 ;
     RECT  34.8 75.781 35.208 76.789 ;
     RECT  28.848 76.501 30.984 76.835 ;
     RECT  7.8 75.923 8.808 76.885 ;
     RECT  20.592 76.451 24.408 76.931 ;
     RECT  10.5 76.019 12.12 76.979 ;
     RECT  18.48 76.789 19.08 76.979 ;
     RECT  63.84 75.541 64.812 76.979 ;
     RECT  67.2 76.739 67.608 76.979 ;
     RECT  32.1 75.683 32.412 77.029 ;
     RECT  12.096 76.979 12.12 77.267 ;
     RECT  32.1 77.029 33.048 77.267 ;
     RECT  48 75.251 48.612 77.267 ;
     RECT  39.312 76.357 43.8 77.315 ;
     RECT  56.4 75.827 56.904 77.365 ;
     RECT  5.1 74.005 6.12 77.461 ;
     RECT  10.5 76.979 10.812 77.509 ;
     RECT  13.2 76.069 13.704 77.555 ;
     RECT  20.592 76.931 24.312 77.555 ;
     RECT  29.4 76.835 30.984 77.555 ;
     RECT  53.04 76.357 54.744 77.555 ;
     RECT  56.4 77.365 57 77.555 ;
     RECT  69.9 76.499 70.212 77.557 ;
     RECT  48.3 77.267 48.612 77.605 ;
     RECT  29.4 77.555 29.832 77.699 ;
     RECT  26.7 76.403 27.012 77.845 ;
     RECT  53.568 77.555 54.744 77.939 ;
     RECT  26.7 77.845 27.192 77.987 ;
     RECT  34.8 76.789 35.832 77.989 ;
     RECT  48.3 77.605 49.368 77.989 ;
     RECT  5.1 77.461 6.264 78.037 ;
     RECT  29.4 77.699 29.712 78.037 ;
     RECT  41.952 77.315 43.8 78.083 ;
     RECT  4.512 78.037 6.264 78.085 ;
     RECT  7.8 76.885 9.096 78.085 ;
     RECT  32.1 77.267 32.412 78.229 ;
     RECT  78 76.403 78.696 78.229 ;
     RECT  32.1 78.229 33.096 78.419 ;
     RECT  67.2 76.979 67.512 78.421 ;
     RECT  4.512 78.085 9.096 78.467 ;
     RECT  15.9 75.875 17.304 78.613 ;
     RECT  18.48 76.979 18.912 78.613 ;
     RECT  30.96 77.555 30.984 78.613 ;
     RECT  32.1 78.419 32.412 78.613 ;
     RECT  45.6 75.539 45.912 78.613 ;
     RECT  59.1 76.403 59.784 78.613 ;
     RECT  75.3 2.151 75.612 78.613 ;
     RECT  77.04 78.229 78.696 78.613 ;
     RECT  4.512 78.467 8.112 78.659 ;
     RECT  18.48 78.613 19.176 78.659 ;
     RECT  68.928 77.557 70.212 78.659 ;
     RECT  21.3 77.555 24.312 79.189 ;
     RECT  29.088 78.037 29.712 79.189 ;
     RECT  30.96 78.613 32.412 79.189 ;
     RECT  67.2 78.421 67.752 79.189 ;
     RECT  80.7 2.151 81.012 79.189 ;
     RECT  2.4 76.309 2.904 79.235 ;
     RECT  21.072 79.189 24.792 79.235 ;
     RECT  75.3 78.613 79.176 79.283 ;
     RECT  41.952 78.083 43.512 79.331 ;
     RECT  15.792 78.613 17.304 79.475 ;
     RECT  66.48 79.189 67.752 79.475 ;
     RECT  72.6 72.659 72.912 79.621 ;
     RECT  22.8 79.235 24.792 79.715 ;
     RECT  18.6 78.659 19.176 79.717 ;
     RECT  53.7 77.939 54.744 79.717 ;
     RECT  58.992 78.613 59.784 79.717 ;
     RECT  58.992 79.717 60.504 79.763 ;
     RECT  7.68 78.659 8.112 79.765 ;
     RECT  21.072 79.235 21.612 79.859 ;
     RECT  66.48 79.475 67.512 79.859 ;
     RECT  29.088 79.189 32.412 79.907 ;
     RECT  59.1 79.763 60.504 79.955 ;
     RECT  80.352 79.189 81.012 80.051 ;
     RECT  4.512 78.659 6.264 80.101 ;
     RECT  7.68 79.765 8.232 80.101 ;
     RECT  39.312 77.315 40.512 80.101 ;
     RECT  29.184 79.907 32.412 80.195 ;
     RECT  4.512 80.101 8.232 80.243 ;
     RECT  41.952 79.331 43.212 80.245 ;
     RECT  48.3 77.989 49.608 80.245 ;
     RECT  51 72.947 51.312 80.245 ;
     RECT  45.6 78.613 46.296 80.291 ;
     RECT  34.8 77.989 35.88 80.341 ;
     RECT  26.7 77.987 27.012 80.389 ;
     RECT  29.4 80.195 32.412 80.437 ;
     RECT  52.464 78.997 52.488 80.483 ;
     RECT  29.4 80.437 32.856 80.579 ;
     RECT  53.7 79.717 54.936 80.579 ;
     RECT  37.5 76.787 37.812 80.773 ;
     RECT  22.896 79.715 24.792 80.915 ;
     RECT  37.056 80.773 37.812 80.915 ;
     RECT  2.4 79.235 2.712 80.917 ;
     RECT  69.9 78.659 70.212 80.917 ;
     RECT  48.3 80.245 51.312 80.963 ;
     RECT  77.04 79.283 79.176 80.963 ;
     RECT  39.312 80.101 40.872 81.011 ;
     RECT  18.288 79.717 19.176 81.059 ;
     RECT  72.48 79.621 72.912 81.107 ;
     RECT  45.6 80.291 46.008 81.155 ;
     RECT  75.3 79.283 75.612 81.445 ;
     RECT  50.352 80.963 51.312 81.493 ;
     RECT  26.7 80.389 27.912 81.587 ;
     RECT  59.1 79.955 60.456 81.635 ;
     RECT  83.4 2.151 83.712 81.781 ;
     RECT  22.896 80.915 24.312 81.877 ;
     RECT  56.4 77.555 56.712 81.877 ;
     RECT  21.3 79.859 21.612 82.021 ;
     RECT  78 80.963 79.176 82.069 ;
     RECT  80.7 80.051 81.012 82.069 ;
     RECT  50.352 81.493 52.248 82.115 ;
     RECT  55.824 81.877 56.712 82.115 ;
     RECT  59.1 81.635 59.784 82.115 ;
     RECT  5.1 80.243 8.232 82.259 ;
     RECT  32.1 80.579 32.856 82.261 ;
     RECT  29.4 80.579 30.984 82.307 ;
     RECT  68.976 80.917 70.212 82.307 ;
     RECT  34.128 80.341 35.88 82.451 ;
     RECT  61.8 75.347 62.664 82.451 ;
     RECT  74.64 81.445 75.612 82.451 ;
     RECT  72.6 81.107 72.912 82.453 ;
     RECT  61.8 82.451 62.232 82.501 ;
     RECT  48.3 80.963 49.128 82.549 ;
     RECT  10.08 77.509 10.812 82.597 ;
     RECT  26.7 81.587 27.768 82.597 ;
     RECT  53.7 80.579 54.012 82.645 ;
     RECT  20.448 82.021 21.612 82.691 ;
     RECT  30.96 82.307 30.984 82.691 ;
     RECT  50.4 82.115 52.248 82.835 ;
     RECT  5.1 82.259 6.264 82.933 ;
     RECT  2.4 80.917 2.856 82.979 ;
     RECT  26.592 82.597 27.768 82.979 ;
     RECT  78 82.069 81.012 82.979 ;
     RECT  75.3 82.451 75.612 82.981 ;
     RECT  7.8 82.259 8.232 83.029 ;
     RECT  22.896 81.877 24.408 83.123 ;
     RECT  53.7 82.645 54.12 83.171 ;
     RECT  37.5 80.915 37.812 83.317 ;
     RECT  39.312 81.011 40.512 83.317 ;
     RECT  31.968 82.261 32.856 83.411 ;
     RECT  61.68 82.501 62.232 83.555 ;
     RECT  37.5 83.317 40.512 83.653 ;
     RECT  72.6 82.453 74.136 83.795 ;
     RECT  78 82.979 79.56 83.795 ;
     RECT  74.112 83.795 74.136 83.891 ;
     RECT  4.224 82.933 6.264 84.035 ;
     RECT  22.896 83.123 22.968 84.037 ;
     RECT  75.3 82.981 76.392 84.037 ;
     RECT  61.8 83.555 62.232 84.083 ;
     RECT  78 83.795 79.176 84.083 ;
     RECT  21.3 82.691 21.612 84.085 ;
     RECT  15.9 79.475 17.304 84.325 ;
     RECT  18.288 81.059 18.912 84.325 ;
     RECT  26.7 82.979 27.012 84.325 ;
     RECT  45.6 81.155 45.912 84.325 ;
     RECT  56.4 82.115 56.712 84.325 ;
     RECT  64.5 76.979 64.812 84.325 ;
     RECT  72.6 83.795 72.912 84.325 ;
     RECT  53.7 83.171 54.012 84.613 ;
     RECT  50.4 82.835 51.312 84.659 ;
     RECT  37.392 83.653 40.512 84.899 ;
     RECT  9.36 82.597 10.812 84.901 ;
     RECT  24 83.123 24.408 84.901 ;
     RECT  25.728 84.325 27.012 84.901 ;
     RECT  28.272 84.805 28.296 84.947 ;
     RECT  78 84.083 79.08 84.947 ;
     RECT  24 84.901 27.012 84.995 ;
     RECT  55.824 84.325 56.712 84.995 ;
     RECT  74.304 84.037 76.392 85.043 ;
     RECT  83.28 81.781 83.712 85.139 ;
     RECT  22.848 84.037 22.968 85.475 ;
     RECT  2.4 82.979 2.712 85.477 ;
     RECT  15.9 84.325 18.912 85.523 ;
     RECT  21.3 84.085 21.816 85.523 ;
     RECT  37.5 84.899 40.512 85.523 ;
     RECT  47.328 82.549 49.128 85.523 ;
     RECT  64.5 84.325 65.592 85.523 ;
     RECT  71.808 84.325 72.912 85.523 ;
     RECT  74.592 85.043 76.392 85.523 ;
     RECT  24 84.995 24.888 85.619 ;
     RECT  45.6 84.325 46.2 85.669 ;
     RECT  69.216 82.307 70.212 85.765 ;
     RECT  17.616 85.523 18.912 85.907 ;
     RECT  83.4 85.139 83.712 85.909 ;
     RECT  44.832 85.669 46.2 85.955 ;
     RECT  31.968 83.411 32.412 86.149 ;
     RECT  9.36 84.901 11.496 86.195 ;
     RECT  2.4 85.477 2.856 86.243 ;
     RECT  39.312 85.523 40.512 86.293 ;
     RECT  41.856 80.245 43.212 86.293 ;
     RECT  44.832 85.955 45.912 86.389 ;
     RECT  44.448 86.389 45.912 86.435 ;
     RECT  47.376 85.523 49.128 86.435 ;
     RECT  61.8 84.083 62.112 86.437 ;
     RECT  5.1 84.035 6.264 86.533 ;
     RECT  7.8 83.029 8.376 86.533 ;
     RECT  68.736 85.765 70.212 86.579 ;
     RECT  80.7 82.979 81.012 86.581 ;
     RECT  68.736 86.579 68.76 86.675 ;
     RECT  44.448 86.435 44.472 86.771 ;
     RECT  72.24 85.523 72.912 86.867 ;
     RECT  37.5 85.523 37.812 87.013 ;
     RECT  51 84.659 51.312 87.109 ;
     RECT  83.4 85.909 84.12 87.155 ;
     RECT  64.5 85.523 64.812 87.157 ;
     RECT  56.4 84.995 56.712 87.205 ;
     RECT  74.592 85.523 76.152 87.253 ;
     RECT  39.312 86.293 43.212 87.299 ;
     RECT  29.4 82.307 29.712 87.301 ;
     RECT  41.856 87.299 43.212 87.397 ;
     RECT  9.36 86.195 10.812 87.587 ;
     RECT  53.7 84.613 54.12 87.733 ;
     RECT  80.064 86.581 81.012 87.779 ;
     RECT  31.968 86.149 32.52 87.827 ;
     RECT  73.968 87.253 76.152 87.827 ;
     RECT  69.9 86.579 70.212 87.829 ;
     RECT  37.5 87.013 37.944 87.875 ;
     RECT  61.2 86.437 62.112 87.875 ;
     RECT  41.856 87.397 43.752 87.923 ;
     RECT  45.6 86.435 45.912 88.021 ;
     RECT  51 87.109 51.72 88.115 ;
     RECT  73.968 87.827 76.008 88.115 ;
     RECT  45.072 88.021 45.912 88.117 ;
     RECT  45.072 88.117 46.008 88.259 ;
     RECT  69.12 87.829 70.212 88.259 ;
     RECT  51 88.115 51.312 88.309 ;
     RECT  56.4 87.205 57.672 88.309 ;
     RECT  53.7 87.733 54.696 88.355 ;
     RECT  5.1 86.533 8.376 88.403 ;
     RECT  41.856 87.923 43.32 88.547 ;
     RECT  29.4 87.301 30.072 88.595 ;
     RECT  33.648 87.781 33.672 88.643 ;
     RECT  71.28 87.733 71.304 88.643 ;
     RECT  39.312 87.299 40.872 88.787 ;
     RECT  9.36 87.587 9.384 88.885 ;
     RECT  13.2 77.555 13.512 88.885 ;
     RECT  28.128 87.541 28.152 88.885 ;
     RECT  29.4 88.595 29.832 88.885 ;
     RECT  72.6 86.867 72.912 88.885 ;
     RECT  83.4 87.155 83.712 88.885 ;
     RECT  9.12 88.885 9.384 88.931 ;
     RECT  28.128 88.885 29.832 88.931 ;
     RECT  56.304 88.309 57.672 88.931 ;
     RECT  59.1 82.115 59.412 88.933 ;
     RECT  34.8 82.451 35.88 88.979 ;
     RECT  60.48 88.309 60.504 88.979 ;
     RECT  74.592 88.115 76.008 88.979 ;
     RECT  67.2 79.859 67.512 89.317 ;
     RECT  78 84.947 78.312 89.413 ;
     RECT  45.6 88.259 46.008 89.459 ;
     RECT  58.992 88.933 59.412 89.459 ;
     RECT  64.5 87.157 65.496 89.459 ;
     RECT  37.5 87.875 37.812 89.461 ;
     RECT  31.968 87.827 32.412 89.509 ;
     RECT  84.816 88.789 84.84 89.555 ;
     RECT  22.848 85.475 22.92 89.653 ;
     RECT  24 85.619 24.312 89.653 ;
     RECT  22.848 89.653 24.312 89.699 ;
     RECT  67.2 89.317 68.28 89.701 ;
     RECT  69.9 88.259 70.212 89.701 ;
     RECT  2.4 86.243 2.712 89.845 ;
     RECT  67.2 89.701 70.212 89.845 ;
     RECT  37.5 89.461 38.184 89.891 ;
     RECT  34.8 88.979 35.64 89.941 ;
     RECT  37.5 89.891 37.812 89.941 ;
     RECT  21.3 85.523 21.612 90.037 ;
     RECT  61.8 87.875 62.112 90.037 ;
     RECT  5.1 88.403 8.112 90.083 ;
     RECT  15.9 85.523 16.44 90.083 ;
     RECT  42.528 88.547 43.32 90.083 ;
     RECT  56.304 88.931 56.712 90.083 ;
     RECT  74.592 88.979 75.864 90.083 ;
     RECT  83.28 88.885 83.712 90.083 ;
     RECT  15.9 90.083 16.212 90.181 ;
     RECT  50.16 88.309 51.312 90.275 ;
     RECT  78 89.413 78.408 90.373 ;
     RECT  45.6 89.459 45.912 90.469 ;
     RECT  47.376 86.435 48.612 90.469 ;
     RECT  31.872 89.509 32.412 90.515 ;
     RECT  22.896 89.699 24.312 90.517 ;
     RECT  74.592 90.083 75.612 90.517 ;
     RECT  83.4 90.083 83.712 90.517 ;
     RECT  13.2 88.885 13.656 90.565 ;
     RECT  28.464 88.931 29.832 90.565 ;
     RECT  28.08 90.565 29.832 90.611 ;
     RECT  34.8 89.941 37.812 90.611 ;
     RECT  60.432 90.085 60.456 90.611 ;
     RECT  31.968 90.515 32.412 90.613 ;
     RECT  22.896 90.517 24.552 90.659 ;
     RECT  67.2 89.845 70.584 90.659 ;
     RECT  20.4 90.037 21.768 90.707 ;
     RECT  28.08 90.611 29.712 90.755 ;
     RECT  74.16 90.517 75.612 90.803 ;
     RECT  2.4 89.845 3.432 90.899 ;
     RECT  64.5 89.459 64.92 90.947 ;
     RECT  67.2 90.659 70.212 90.947 ;
     RECT  36.528 90.611 37.812 91.045 ;
     RECT  6.864 90.083 8.112 91.093 ;
     RECT  64.5 90.947 64.812 91.141 ;
     RECT  9.12 88.931 9.144 91.187 ;
     RECT  13.104 90.565 13.656 91.331 ;
     RECT  64.224 91.141 64.812 91.475 ;
     RECT  26.7 84.995 27.012 91.477 ;
     RECT  20.4 90.707 21.612 91.571 ;
     RECT  45.6 90.469 48.612 91.621 ;
     RECT  51 90.275 51.312 91.717 ;
     RECT  69.9 90.947 70.212 91.717 ;
     RECT  28.08 90.755 28.104 91.765 ;
     RECT  15.072 90.181 16.212 91.859 ;
     RECT  72.48 88.885 72.912 91.859 ;
     RECT  31.968 90.613 33.048 91.955 ;
     RECT  42.528 90.083 43.212 91.957 ;
     RECT  49.968 90.613 49.992 92.099 ;
     RECT  78 90.373 78.504 92.149 ;
     RECT  51 91.717 52.248 92.197 ;
     RECT  2.4 90.899 2.712 92.245 ;
     RECT  15.9 91.859 16.212 92.245 ;
     RECT  64.5 91.475 64.812 92.245 ;
     RECT  51 92.197 52.44 92.293 ;
     RECT  28.032 91.765 28.104 92.387 ;
     RECT  13.104 91.331 13.512 92.435 ;
     RECT  5.1 90.083 5.412 92.821 ;
     RECT  74.592 90.803 75.612 92.821 ;
     RECT  6.816 91.093 8.112 92.869 ;
     RECT  36.528 91.045 37.944 92.869 ;
     RECT  53.7 88.355 54.012 92.869 ;
     RECT  36.48 92.869 37.944 92.915 ;
     RECT  45.408 91.621 48.612 92.917 ;
     RECT  80.7 87.779 81.012 92.917 ;
     RECT  15.9 92.245 16.344 92.963 ;
     RECT  44.976 92.917 48.612 92.963 ;
     RECT  50.352 92.293 52.44 92.963 ;
     RECT  74.592 92.821 75.864 92.963 ;
     RECT  2.4 92.245 2.856 93.011 ;
     RECT  67.2 90.947 68.568 93.013 ;
     RECT  69.9 91.717 70.488 93.013 ;
     RECT  83.4 90.517 83.832 93.013 ;
     RECT  36.48 92.915 37.812 93.059 ;
     RECT  86.1 2.151 86.412 93.109 ;
     RECT  64.5 92.245 65.736 93.205 ;
     RECT  67.2 93.013 70.488 93.205 ;
     RECT  78 92.149 78.696 93.205 ;
     RECT  83.4 93.013 84.168 93.205 ;
     RECT  26.064 91.477 27.012 93.251 ;
     RECT  64.5 93.205 70.488 93.251 ;
     RECT  59.1 89.459 59.412 93.253 ;
     RECT  50.352 92.963 51.72 93.299 ;
     RECT  66.48 93.251 70.488 93.299 ;
     RECT  74.928 92.963 75.864 93.445 ;
     RECT  83.4 93.205 84.216 93.445 ;
     RECT  44.976 92.963 46.728 93.491 ;
     RECT  13.2 92.435 13.512 93.493 ;
     RECT  31.968 91.955 32.412 93.539 ;
     RECT  36.96 93.059 37.812 93.539 ;
     RECT  5.1 92.821 5.544 93.635 ;
     RECT  48.3 92.963 48.612 93.637 ;
     RECT  6.816 92.869 8.808 93.779 ;
     RECT  53.7 92.869 54.168 93.779 ;
     RECT  66.48 93.299 68.376 93.779 ;
     RECT  80.7 92.917 81.528 93.779 ;
     RECT  42.528 91.957 43.32 94.019 ;
     RECT  83.184 93.445 84.216 94.019 ;
     RECT  83.184 94.019 84.168 94.021 ;
     RECT  22.896 90.659 24.312 94.067 ;
     RECT  86.1 93.109 86.952 94.067 ;
     RECT  22.896 94.067 22.92 94.115 ;
     RECT  28.08 92.387 28.104 94.115 ;
     RECT  37.248 93.539 37.812 94.115 ;
     RECT  42.528 94.019 43.212 94.115 ;
     RECT  58.368 93.253 59.412 94.211 ;
     RECT  82.656 94.021 84.168 94.259 ;
     RECT  90.288 91.141 90.312 94.259 ;
     RECT  19.968 94.021 19.992 94.403 ;
     RECT  51 93.299 51.72 94.499 ;
     RECT  64.5 93.251 64.812 94.501 ;
     RECT  12.72 93.493 13.512 94.547 ;
     RECT  45.6 93.491 46.728 94.547 ;
     RECT  71.52 93.349 71.544 94.549 ;
     RECT  72.6 91.859 72.912 94.549 ;
     RECT  60.432 93.397 60.456 94.595 ;
     RECT  67.2 93.779 68.376 94.595 ;
     RECT  71.52 94.549 72.912 94.595 ;
     RECT  61.8 90.037 62.424 94.597 ;
     RECT  63.696 94.501 64.812 94.597 ;
     RECT  69.9 93.299 70.488 94.597 ;
     RECT  61.8 94.597 64.812 94.643 ;
     RECT  82.656 94.259 83.712 94.643 ;
     RECT  45.6 94.547 45.912 94.645 ;
     RECT  6.816 93.779 8.112 94.691 ;
     RECT  39.312 88.787 40.512 94.691 ;
     RECT  61.8 94.643 63.384 94.691 ;
     RECT  74.928 93.445 76.392 94.835 ;
     RECT  69.9 94.597 70.68 94.883 ;
     RECT  83.184 94.643 83.712 94.883 ;
     RECT  71.76 94.595 72.912 95.075 ;
     RECT  74.928 94.835 75.612 95.075 ;
     RECT  34.8 90.611 35.112 95.125 ;
     RECT  67.2 94.595 67.512 95.125 ;
     RECT  45.024 94.645 45.912 95.219 ;
     RECT  48.3 93.637 49.32 95.219 ;
     RECT  63.36 94.691 63.384 95.747 ;
     RECT  66.96 95.125 67.512 95.795 ;
     RECT  78 93.205 78.84 95.891 ;
     RECT  34.32 95.125 35.112 95.939 ;
     RECT  5.1 93.635 5.412 96.901 ;
     RECT  7.8 94.691 8.112 96.901 ;
     RECT  10.5 87.587 10.812 96.901 ;
     RECT  15.9 92.963 16.212 96.901 ;
     RECT  18.6 85.907 18.912 96.901 ;
     RECT  21.3 91.571 21.612 96.901 ;
     RECT  26.7 93.251 27.012 96.901 ;
     RECT  29.4 90.755 29.712 96.901 ;
     RECT  32.1 93.539 32.412 96.901 ;
     RECT  37.5 94.115 37.812 96.901 ;
     RECT  42.9 94.115 43.212 96.901 ;
     RECT  48.3 95.219 48.612 96.901 ;
     RECT  51 94.499 51.312 96.901 ;
     RECT  53.7 93.779 54.012 96.901 ;
     RECT  56.4 90.083 56.712 96.901 ;
     RECT  59.1 94.211 59.412 96.901 ;
     RECT  61.8 94.691 62.112 96.901 ;
     RECT  67.2 95.795 67.512 96.901 ;
     RECT  69.9 94.883 70.212 96.901 ;
     RECT  72.6 95.075 72.912 96.901 ;
     RECT  75.3 95.075 75.612 96.901 ;
     RECT  78 95.891 78.312 96.901 ;
     RECT  80.7 93.779 81.012 96.901 ;
     RECT  86.1 94.067 86.412 96.901 ;
     RECT  88.8 2.151 89.112 96.901 ;
     RECT  4.752 96.901 5.976 97.141 ;
     RECT  7.152 96.901 9 97.141 ;
     RECT  10.176 96.901 10.812 97.141 ;
     RECT  13.2 94.547 13.512 97.141 ;
     RECT  18 96.901 19.848 97.141 ;
     RECT  21.024 96.901 22.872 97.141 ;
     RECT  24 94.067 24.312 97.141 ;
     RECT  25.824 96.901 28.296 97.141 ;
     RECT  29.4 96.901 30.696 97.141 ;
     RECT  32.1 96.901 33.096 97.141 ;
     RECT  36.096 96.901 36.12 97.141 ;
     RECT  37.296 96.901 39.144 97.141 ;
     RECT  40.2 94.691 40.512 97.141 ;
     RECT  41.52 96.901 43.944 97.141 ;
     RECT  46.944 96.901 46.968 97.141 ;
     RECT  48.144 96.901 49.944 97.141 ;
     RECT  51 96.901 52.392 97.141 ;
     RECT  53.568 96.901 54.012 97.141 ;
     RECT  56.4 96.901 60.216 97.141 ;
     RECT  61.392 96.901 63.24 97.141 ;
     RECT  64.5 94.643 64.812 97.141 ;
     RECT  66.192 96.901 66.216 97.141 ;
     RECT  67.2 96.901 68.664 97.141 ;
     RECT  69.9 96.901 73.464 97.141 ;
     RECT  74.64 96.901 76.488 97.141 ;
     RECT  77.664 96.901 79.464 97.141 ;
     RECT  80.7 96.901 81.288 97.141 ;
     RECT  83.4 94.883 83.712 97.141 ;
     RECT  84.864 96.901 87.336 97.141 ;
     RECT  90.288 96.901 90.312 97.141 ;
     RECT  91.5 59.749 92.76 97.141 ;
     RECT  2.4 93.011 2.712 97.209 ;
     RECT  34.8 95.939 35.112 97.209 ;
     RECT  94.2 2.151 94.512 97.209 ;
     RECT  2.4 97.209 2.52 97.223 ;
     RECT  34.8 97.209 34.92 97.223 ;
     RECT  45.6 95.219 45.912 97.223 ;
     RECT  94.2 97.209 94.32 97.223 ;
     RECT  4.752 97.141 10.812 97.285 ;
     RECT  69.9 97.141 76.488 97.333 ;
     RECT  4.752 97.285 10.824 97.429 ;
     RECT  15.024 96.901 16.824 97.429 ;
     RECT  18 97.141 24.648 97.429 ;
     RECT  25.824 97.141 30.696 97.429 ;
     RECT  31.872 97.141 33.72 97.429 ;
     RECT  45.744 97.223 45.912 97.429 ;
     RECT  46.944 97.141 54.168 97.429 ;
     RECT  55.968 97.141 65.016 97.429 ;
     RECT  66.192 97.141 68.664 97.429 ;
     RECT  69.84 97.333 76.488 97.429 ;
     RECT  77.664 97.141 81.288 97.429 ;
     RECT  83.088 97.141 87.336 97.429 ;
     RECT  88.512 96.901 89.112 97.429 ;
     RECT  90.288 97.141 92.76 97.429 ;
     RECT  4.752 97.429 11.4 98.053 ;
     RECT  12.576 97.141 13.8 98.053 ;
     RECT  15.024 97.429 24.648 98.053 ;
     RECT  25.824 97.429 33.72 98.053 ;
     RECT  45.744 97.429 54.168 98.053 ;
     RECT  4.752 98.053 13.8 98.581 ;
     RECT  15.024 98.053 33.72 98.581 ;
     RECT  34.896 97.223 34.92 98.581 ;
     RECT  36.096 97.141 44.568 98.581 ;
     RECT  45.744 98.053 54.792 98.581 ;
     RECT  55.968 97.429 76.488 98.581 ;
     RECT  77.664 97.429 92.76 98.581 ;
     RECT  4.752 98.581 44.568 98.629 ;
     RECT  45.744 98.581 92.76 98.629 ;
     RECT  4.752 98.629 92.76 99.216 ;
     RECT  2.712 4.837 3.888 5.699 ;
     RECT  3.912 4.837 5.1 5.699 ;
     RECT  2.712 5.699 3.432 6.661 ;
     RECT  9.096 9.061 10.5 32.341 ;
     RECT  5.544 10.309 6.528 10.499 ;
     RECT  6.552 10.309 7.632 10.499 ;
     RECT  7.104 10.499 7.632 11.365 ;
     RECT  7.104 16.019 7.8 16.069 ;
     RECT  5.544 16.069 6.576 16.403 ;
     RECT  6.6 16.069 7.8 16.403 ;
     RECT  5.544 16.403 7.8 17.605 ;
     RECT  5.544 17.605 6.768 19.333 ;
     RECT  6.792 17.605 7.8 22.837 ;
     RECT  2.712 17.989 3.696 18.755 ;
     RECT  3.72 17.989 5.1 18.709 ;
     RECT  3.96 18.709 5.1 19.331 ;
     RECT  2.712 18.755 3.936 19.331 ;
     RECT  5.592 19.333 6.768 19.907 ;
     RECT  25.176 19.621 26.7 27.205 ;
     RECT  5.544 19.907 6.768 22.645 ;
     RECT  5.592 22.645 6.768 22.979 ;
     RECT  5.592 22.979 6.864 24.563 ;
     RECT  2.712 23.221 4.176 25.187 ;
     RECT  21.612 23.315 22.152 23.893 ;
     RECT  18.912 23.317 20.4 28.501 ;
     RECT  16.212 23.845 17.184 24.659 ;
     RECT  17.208 23.845 18.6 24.659 ;
     RECT  21.612 23.893 22.704 26.725 ;
     RECT  22.728 23.893 24 26.771 ;
     RECT  10.812 24.229 12.192 27.013 ;
     RECT  12.216 24.229 13.2 27.059 ;
     RECT  5.544 24.899 5.592 26.197 ;
     RECT  2.712 25.187 5.1 25.669 ;
     RECT  14.616 25.621 15.9 26.291 ;
     RECT  2.712 25.669 4.032 27.301 ;
     RECT  4.056 25.669 5.1 27.637 ;
     RECT  5.544 26.197 6.864 26.771 ;
     RECT  5.544 26.771 7.8 26.773 ;
     RECT  22.296 26.771 22.44 27.877 ;
     RECT  5.688 26.773 7.8 27.877 ;
     RECT  11.784 27.059 13.2 28.933 ;
     RECT  25.176 27.205 26.208 30.851 ;
     RECT  2.712 27.301 3.984 28.453 ;
     RECT  27.012 27.781 28.512 29.027 ;
     RECT  5.688 27.877 6.768 29.651 ;
     RECT  6.792 27.877 7.8 28.405 ;
     RECT  18.912 28.501 20.352 29.699 ;
     RECT  11.784 28.933 13.104 29.077 ;
     RECT  11.784 29.077 13.008 30.323 ;
     RECT  14.424 29.077 15.9 29.795 ;
     RECT  18.912 29.699 20.4 31.909 ;
     RECT  11.784 30.323 13.2 35.653 ;
     RECT  7.68 30.803 7.8 32.149 ;
     RECT  3.624 30.851 4.608 31.861 ;
     RECT  25.08 30.851 26.208 30.947 ;
     RECT  29.832 31.285 31.344 32.485 ;
     RECT  5.412 32.339 5.688 32.437 ;
     RECT  9.096 32.341 10.368 32.437 ;
     RECT  5.412 32.437 7.2 33.155 ;
     RECT  30.216 32.485 31.344 33.059 ;
     RECT  20.232 32.531 21.3 37.573 ;
     RECT  5.412 33.155 7.296 33.589 ;
     RECT  22.104 33.349 23.616 34.357 ;
     RECT  6.312 33.589 7.296 34.355 ;
     RECT  25.128 33.589 26.16 34.931 ;
     RECT  6.312 34.355 7.392 36.421 ;
     RECT  22.104 34.357 23.184 35.221 ;
     RECT  27.816 34.741 29.28 35.459 ;
     RECT  18.912 34.979 20.208 39.395 ;
     RECT  32.412 35.029 33.936 35.843 ;
     RECT  22.44 35.363 23.616 35.795 ;
     RECT  27.012 35.459 27.144 36.901 ;
     RECT  29.232 35.459 29.4 36.565 ;
     RECT  11.976 35.653 13.2 36.133 ;
     RECT  22.104 35.795 23.616 35.843 ;
     RECT  23.328 35.843 23.616 36.469 ;
     RECT  25.656 36.469 26.7 39.635 ;
     RECT  24.312 36.515 25.632 37.573 ;
     RECT  35.208 36.517 36.48 37.091 ;
     RECT  29.232 36.707 29.4 37.573 ;
     RECT  7.056 36.755 7.2 38.005 ;
     RECT  10.812 36.851 11.952 37.619 ;
     RECT  35.112 37.091 36.48 38.245 ;
     RECT  40.08 37.091 40.2 38.389 ;
     RECT  23.328 37.139 23.616 37.669 ;
     RECT  30.216 37.429 31.632 39.395 ;
     RECT  27.96 37.573 29.4 38.963 ;
     RECT  21.612 37.669 22.608 37.955 ;
     RECT  22.632 37.669 23.616 37.955 ;
     RECT  36.504 37.859 37.5 38.819 ;
     RECT  23.184 37.955 23.616 38.677 ;
     RECT  24.312 38.003 25.632 39.301 ;
     RECT  35.208 38.245 36.48 38.819 ;
     RECT  37.812 38.387 38.472 39.013 ;
     RECT  29.28 38.963 29.4 39.877 ;
     RECT  37.812 39.013 38.88 40.259 ;
     RECT  38.904 39.013 40.08 40.213 ;
     RECT  13.896 39.301 15.216 41.075 ;
     RECT  16.968 39.301 18.336 39.493 ;
     RECT  30.216 39.395 30.312 39.877 ;
     RECT  17.112 39.493 18.336 40.259 ;
     RECT  35.112 40.019 35.208 40.981 ;
     RECT  17.112 40.259 18.6 40.307 ;
     RECT  37.812 40.259 39.312 43.285 ;
     RECT  35.112 40.981 36.288 42.803 ;
     RECT  36.312 40.981 37.5 42.803 ;
     RECT  18.912 41.221 19.92 42.085 ;
     RECT  19.944 41.221 21.12 41.651 ;
     RECT  10.812 41.509 12 42.851 ;
     RECT  12.024 41.555 13.2 42.851 ;
     RECT  7.2 41.651 7.68 42.421 ;
     RECT  19.944 41.651 21.3 43.285 ;
     RECT  32.412 41.893 33.552 42.659 ;
     RECT  33.576 41.893 34.8 42.659 ;
     RECT  5.412 42.179 5.592 42.421 ;
     RECT  5.412 42.421 6.528 44.915 ;
     RECT  6.552 42.421 7.68 44.915 ;
     RECT  14.712 42.661 15.9 43.715 ;
     RECT  10.812 42.851 11.16 43.237 ;
     RECT  17.4 43.285 18.6 44.915 ;
     RECT  19.992 43.285 21.3 44.627 ;
     RECT  38.184 43.285 39.312 44.099 ;
     RECT  45.504 43.667 45.6 44.869 ;
     RECT  42.144 43.907 42.528 44.341 ;
     RECT  37.812 44.099 39.312 46.165 ;
     RECT  41.304 44.341 42.528 45.683 ;
     RECT  19.176 44.627 21.3 45.829 ;
     RECT  22.104 44.965 23.616 45.923 ;
     RECT  42.144 45.683 42.528 46.405 ;
     RECT  19.176 45.829 20.496 46.787 ;
     RECT  21.612 45.923 23.616 47.365 ;
     RECT  38.232 46.165 39.312 46.693 ;
     RECT  47.904 46.211 48 47.171 ;
     RECT  43.212 46.693 44.304 47.363 ;
     RECT  19.176 46.787 21.3 47.651 ;
     RECT  24.408 46.885 25.632 47.269 ;
     RECT  25.656 46.885 26.7 47.699 ;
     RECT  47.904 47.171 48.3 47.269 ;
     RECT  17.112 47.173 18.6 48.275 ;
     RECT  5.412 47.269 6.624 49.381 ;
     RECT  6.648 47.269 7.68 48.661 ;
     RECT  24.6 47.269 25.632 47.699 ;
     RECT  45.912 47.269 47.28 48.467 ;
     RECT  47.304 47.269 48.3 48.467 ;
     RECT  43.212 47.363 45.264 48.421 ;
     RECT  21.612 47.365 22.656 47.747 ;
     RECT  41.016 47.509 42.144 47.555 ;
     RECT  41.016 47.555 42.528 48.659 ;
     RECT  19.128 47.651 21.3 47.941 ;
     RECT  24.6 47.699 25.128 48.229 ;
     RECT  19.128 47.941 20.64 48.947 ;
     RECT  49.416 48.373 50.832 49.619 ;
     RECT  43.992 48.421 45.264 49.091 ;
     RECT  52.248 48.997 53.7 55.525 ;
     RECT  24.6 49.091 25.128 49.525 ;
     RECT  45.024 49.091 45.264 49.573 ;
     RECT  24.6 49.525 26.112 52.165 ;
     RECT  45.024 49.573 45.168 50.533 ;
     RECT  50.16 49.619 50.832 50.149 ;
     RECT  37.944 50.051 39.312 53.075 ;
     RECT  27.816 50.389 29.232 50.435 ;
     RECT  30.456 50.389 31.872 51.637 ;
     RECT  32.412 51.109 33.6 51.923 ;
     RECT  33.624 51.109 34.8 51.923 ;
     RECT  27.012 51.203 27.816 52.405 ;
     RECT  6.264 51.347 7.296 51.491 ;
     RECT  17.4 51.637 18.6 54.085 ;
     RECT  11.64 52.021 13.104 52.739 ;
     RECT  25.128 52.165 26.112 55.667 ;
     RECT  27.012 52.405 28.464 55.237 ;
     RECT  30.456 52.499 31.872 54.083 ;
     RECT  5.412 52.883 5.544 54.085 ;
     RECT  37.812 53.075 39.312 56.101 ;
     RECT  62.112 53.941 63.264 54.755 ;
     RECT  63.288 53.941 64.5 54.661 ;
     RECT  30.36 54.083 31.872 56.003 ;
     RECT  5.412 54.085 6.528 54.755 ;
     RECT  21.612 54.085 23.04 54.421 ;
     RECT  32.412 54.469 33.84 57.347 ;
     RECT  59.412 54.565 60.384 57.059 ;
     RECT  60.408 54.565 61.8 57.059 ;
     RECT  35.976 54.613 37.5 55.475 ;
     RECT  5.412 54.755 7.392 55.237 ;
     RECT  6.12 55.237 7.392 55.283 ;
     RECT  48.612 55.283 48.936 56.389 ;
     RECT  17.4 55.427 18.6 57.059 ;
     RECT  52.728 55.525 53.7 55.955 ;
     RECT  24.696 55.667 26.112 59.269 ;
     RECT  52.248 55.955 53.7 56.483 ;
     RECT  30.36 56.003 30.504 56.965 ;
     RECT  27.012 56.099 27.984 57.587 ;
     RECT  38.232 56.101 39.312 57.827 ;
     RECT  53.28 56.483 53.7 56.965 ;
     RECT  28.008 56.531 29.28 57.587 ;
     RECT  43.212 56.965 44.496 58.643 ;
     RECT  17.112 57.059 18.6 57.107 ;
     RECT  44.52 57.059 45.6 58.643 ;
     RECT  12.528 57.107 13.2 57.445 ;
     RECT  17.064 57.107 18.6 58.501 ;
     RECT  10.812 57.445 12.048 58.979 ;
     RECT  12.072 57.445 13.2 58.979 ;
     RECT  37.812 57.827 39.312 59.989 ;
     RECT  64.812 58.163 65.544 59.221 ;
     RECT  21.612 58.403 21.768 59.221 ;
     RECT  17.592 58.501 18.6 63.781 ;
     RECT  16.44 58.547 17.568 59.749 ;
     RECT  13.512 59.029 14.736 59.221 ;
     RECT  14.76 59.029 15.9 59.461 ;
     RECT  56.712 59.029 58.128 61.043 ;
     RECT  13.656 59.221 14.736 60.371 ;
     RECT  21.612 59.221 23.136 59.891 ;
     RECT  64.812 59.221 66.288 59.509 ;
     RECT  24.792 59.269 26.112 63.781 ;
     RECT  65.016 59.509 66.288 59.749 ;
     RECT  14.76 59.699 15.9 60.371 ;
     RECT  92.76 59.749 94.2 97.223 ;
     RECT  21.612 59.891 22.104 61.189 ;
     RECT  37.812 59.989 39.264 60.373 ;
     RECT  37.812 60.373 38.88 60.995 ;
     RECT  35.112 60.421 36.48 64.595 ;
     RECT  36.504 60.659 37.5 64.595 ;
     RECT  37.812 60.995 39.216 62.821 ;
     RECT  56.712 61.043 59.1 61.525 ;
     RECT  18.912 61.333 20.352 61.763 ;
     RECT  22.104 61.477 23.232 63.011 ;
     RECT  57.576 61.525 59.1 62.435 ;
     RECT  18.912 61.763 20.496 62.531 ;
     RECT  46.008 62.293 47.04 62.867 ;
     RECT  47.064 62.293 48.3 63.107 ;
     RECT  67.512 62.293 68.88 65.603 ;
     RECT  68.904 62.293 69.9 65.603 ;
     RECT  18.912 62.531 21.3 63.205 ;
     RECT  61.584 62.579 61.8 63.781 ;
     RECT  30.744 62.581 32.1 63.299 ;
     RECT  16.584 62.723 17.568 64.163 ;
     RECT  37.944 62.821 39.216 63.827 ;
     RECT  45.912 62.867 47.04 63.107 ;
     RECT  22.104 63.011 22.2 63.253 ;
     RECT  43.212 63.011 43.464 63.061 ;
     RECT  43.212 63.061 44.976 63.109 ;
     RECT  43.212 63.109 44.88 63.781 ;
     RECT  18.912 63.205 20.16 69.349 ;
     RECT  20.184 63.205 21.3 67.285 ;
     RECT  29.832 63.299 32.1 63.781 ;
     RECT  29.832 63.781 30.864 63.875 ;
     RECT  30.888 63.781 32.1 69.731 ;
     RECT  43.212 63.781 44.448 64.979 ;
     RECT  37.944 63.827 39.312 63.829 ;
     RECT  38.184 63.829 39.312 66.515 ;
     RECT  2.712 63.875 4.272 65.269 ;
     RECT  29.712 63.875 30.864 69.731 ;
     RECT  16.44 64.163 17.568 71.459 ;
     RECT  61.584 64.403 61.8 64.693 ;
     RECT  22.104 64.499 22.2 65.509 ;
     RECT  35.112 64.595 35.832 65.125 ;
     RECT  60.744 64.693 61.8 66.227 ;
     RECT  45.912 64.885 47.328 65.269 ;
     RECT  17.592 65.027 18.6 69.493 ;
     RECT  24.792 65.075 26.16 66.661 ;
     RECT  35.208 65.125 35.832 65.509 ;
     RECT  49.56 65.173 51 67.331 ;
     RECT  3.048 65.269 4.272 66.755 ;
     RECT  45.912 65.269 47.136 66.997 ;
     RECT  22.92 65.509 24 68.965 ;
     RECT  27.96 65.941 29.28 66.085 ;
     RECT  27.96 66.085 29.232 67.235 ;
     RECT  5.412 66.325 6.864 70.739 ;
     RECT  11.688 66.325 13.2 66.805 ;
     RECT  37.944 66.515 39.312 67.283 ;
     RECT  3.048 66.755 4.944 67.765 ;
     RECT  9.096 66.755 10.5 67.283 ;
     RECT  11.688 66.805 12.768 66.947 ;
     RECT  70.584 66.901 71.568 66.947 ;
     RECT  71.592 66.901 72.6 71.267 ;
     RECT  11.688 66.947 13.2 69.973 ;
     RECT  70.212 66.947 71.568 71.173 ;
     RECT  29.136 67.235 29.232 68.389 ;
     RECT  37.812 67.283 39.312 67.813 ;
     RECT  20.184 67.285 21.168 68.341 ;
     RECT  47.16 67.331 48.3 69.349 ;
     RECT  3.432 67.765 4.944 68.675 ;
     RECT  33.384 67.813 34.8 68.101 ;
     RECT  37.812 67.813 38.784 68.627 ;
     RECT  24.792 67.859 26.16 68.435 ;
     RECT  45.912 68.099 46.992 73.765 ;
     RECT  33.432 68.101 34.8 69.587 ;
     RECT  40.512 68.147 41.616 68.627 ;
     RECT  51.864 68.341 53.28 69.109 ;
     RECT  15.792 68.435 15.9 69.493 ;
     RECT  26.112 68.435 26.16 69.349 ;
     RECT  37.812 68.627 39.312 68.965 ;
     RECT  54.012 68.917 55.008 69.445 ;
     RECT  55.032 68.917 56.4 69.491 ;
     RECT  37.944 68.965 39.312 70.213 ;
     RECT  2.712 69.011 2.952 70.117 ;
     RECT  51.864 69.109 53.04 69.251 ;
     RECT  47.208 69.349 48.3 72.325 ;
     RECT  59.784 69.349 61.008 71.891 ;
     RECT  22.92 69.539 24 73.813 ;
     RECT  33.384 69.587 34.8 74.723 ;
     RECT  29.712 69.731 32.1 70.021 ;
     RECT  12.024 69.973 13.2 71.605 ;
     RECT  24.504 70.021 25.824 70.789 ;
     RECT  29.712 70.021 30.96 71.077 ;
     RECT  30.984 70.021 32.1 73.765 ;
     RECT  15.792 70.163 15.9 71.413 ;
     RECT  38.04 70.213 39.312 73.571 ;
     RECT  48.612 70.213 50.112 72.947 ;
     RECT  17.592 70.259 18.6 71.459 ;
     RECT  67.512 70.595 67.608 71.797 ;
     RECT  13.512 70.835 13.704 71.413 ;
     RECT  2.712 71.075 2.952 72.229 ;
     RECT  29.712 71.077 30.816 72.419 ;
     RECT  70.68 71.267 72.6 71.797 ;
     RECT  20.184 71.315 21.3 74.101 ;
     RECT  13.512 71.413 14.736 73.379 ;
     RECT  14.76 71.413 15.9 72.325 ;
     RECT  16.44 71.459 18.6 72.757 ;
     RECT  19.08 71.651 20.064 74.339 ;
     RECT  25.08 71.699 26.7 72.901 ;
     RECT  67.512 71.797 69.024 72.949 ;
     RECT  70.68 71.797 71.808 72.659 ;
     RECT  41.16 72.037 42.528 73.477 ;
     RECT  2.712 72.229 3.744 74.915 ;
     RECT  3.768 72.229 4.944 72.419 ;
     RECT  62.112 72.325 63.312 72.805 ;
     RECT  3.768 72.419 5.1 74.915 ;
     RECT  29.712 72.419 30.96 76.357 ;
     RECT  70.68 72.659 72.6 72.851 ;
     RECT  17.304 72.757 18.6 76.789 ;
     RECT  52.248 72.805 53.568 72.947 ;
     RECT  62.232 72.805 63.312 73.477 ;
     RECT  70.212 72.851 72.6 73.381 ;
     RECT  25.176 72.901 26.7 73.477 ;
     RECT  63.336 73.043 64.5 73.523 ;
     RECT  68.184 73.283 69.552 74.051 ;
     RECT  70.212 73.381 71.328 75.251 ;
     RECT  71.352 73.381 72.6 75.251 ;
     RECT  25.224 73.477 26.7 74.965 ;
     RECT  64.812 73.477 66.24 76.739 ;
     RECT  37.812 73.571 39.312 75.781 ;
     RECT  6.12 74.005 7.44 74.051 ;
     RECT  6.12 74.051 7.632 75.923 ;
     RECT  67.608 74.051 69.552 75.157 ;
     RECT  54.744 74.053 56.016 74.965 ;
     RECT  11.688 74.147 13.2 75.973 ;
     RECT  46.824 74.147 48 75.539 ;
     RECT  62.616 74.147 62.952 75.205 ;
     RECT  19.08 74.339 20.496 76.451 ;
     RECT  41.16 74.579 42.528 76.357 ;
     RECT  33.288 74.723 34.8 75.059 ;
     RECT  2.712 74.915 2.904 76.309 ;
     RECT  54.744 74.965 55.872 75.827 ;
     RECT  56.712 75.013 58.224 75.781 ;
     RECT  68.424 75.157 69.552 76.499 ;
     RECT  63.24 75.205 64.5 75.347 ;
     RECT  62.664 75.347 64.5 75.541 ;
     RECT  79.176 75.397 80.7 76.403 ;
     RECT  28.848 75.539 29.232 76.501 ;
     RECT  62.664 75.541 63.84 76.979 ;
     RECT  30.984 75.683 32.1 78.613 ;
     RECT  38.232 75.781 39.312 76.787 ;
     RECT  56.904 75.781 58.224 76.403 ;
     RECT  12.12 75.973 13.2 77.267 ;
     RECT  10.368 76.019 10.5 76.885 ;
     RECT  25.272 76.403 26.7 76.451 ;
     RECT  56.904 76.403 57 77.365 ;
     RECT  19.08 76.451 20.592 76.979 ;
     RECT  68.424 76.499 69.9 76.643 ;
     RECT  67.608 76.643 69.9 76.979 ;
     RECT  37.812 76.787 39.312 83.317 ;
     RECT  17.304 76.789 18.48 78.659 ;
     RECT  29.088 76.835 29.4 78.037 ;
     RECT  9.096 76.885 10.5 77.509 ;
     RECT  10.812 76.979 12.096 77.267 ;
     RECT  67.512 76.979 69.9 77.557 ;
     RECT  32.412 77.267 33.048 78.229 ;
     RECT  40.512 77.315 41.952 80.101 ;
     RECT  9.096 77.509 10.08 78.467 ;
     RECT  29.832 77.555 30.96 77.699 ;
     RECT  53.04 77.555 53.568 77.939 ;
     RECT  67.512 77.557 68.928 78.421 ;
     RECT  29.712 77.699 30.96 79.189 ;
     RECT  53.04 77.939 53.7 78.997 ;
     RECT  49.608 77.989 51 80.245 ;
     RECT  75.612 78.229 77.04 78.613 ;
     RECT  67.752 78.421 68.928 78.659 ;
     RECT  8.112 78.467 8.232 79.765 ;
     RECT  79.176 78.613 80.7 79.189 ;
     RECT  6.264 78.659 7.68 80.101 ;
     RECT  17.304 78.659 18.6 79.717 ;
     RECT  51.312 78.997 52.464 80.483 ;
     RECT  52.488 78.997 53.7 80.483 ;
     RECT  79.176 79.189 80.352 80.051 ;
     RECT  21.612 79.235 22.8 79.715 ;
     RECT  75.612 79.283 77.04 80.963 ;
     RECT  67.512 79.475 67.752 80.917 ;
     RECT  21.612 79.715 22.896 84.037 ;
     RECT  17.304 79.717 18.288 84.325 ;
     RECT  54.936 79.717 56.4 80.579 ;
     RECT  60.504 79.717 61.8 79.955 ;
     RECT  29.088 79.907 29.184 80.195 ;
     RECT  60.456 79.955 61.8 81.635 ;
     RECT  79.176 80.051 80.7 82.069 ;
     RECT  40.872 80.101 41.952 80.245 ;
     RECT  29.088 80.195 29.4 80.389 ;
     RECT  40.872 80.245 41.856 81.011 ;
     RECT  27.912 80.389 29.4 81.587 ;
     RECT  32.856 80.437 34.128 82.451 ;
     RECT  51.312 80.483 53.7 81.493 ;
     RECT  30.984 80.579 32.1 82.261 ;
     RECT  55.824 80.579 56.4 81.877 ;
     RECT  35.88 80.773 37.056 80.915 ;
     RECT  24.312 80.915 24.408 81.877 ;
     RECT  67.512 80.917 68.976 82.307 ;
     RECT  49.128 80.963 50.352 82.115 ;
     RECT  40.512 81.011 41.856 86.293 ;
     RECT  45.912 81.155 46.008 82.549 ;
     RECT  52.248 81.493 53.7 82.835 ;
     RECT  61.68 81.635 61.8 82.501 ;
     RECT  49.128 82.115 50.4 84.659 ;
     RECT  30.984 82.261 31.968 82.691 ;
     RECT  29.712 82.307 30.96 82.691 ;
     RECT  74.64 82.451 75.3 82.453 ;
     RECT  74.136 82.453 75.3 83.891 ;
     RECT  45.912 82.549 47.328 84.325 ;
     RECT  8.232 82.597 9.36 83.029 ;
     RECT  2.856 82.933 4.224 82.979 ;
     RECT  2.712 82.979 4.224 84.035 ;
     RECT  26.592 82.979 26.7 84.325 ;
     RECT  79.56 82.979 80.7 83.795 ;
     RECT  8.376 83.029 9.36 88.403 ;
     RECT  22.968 83.123 24 85.475 ;
     RECT  54.012 83.171 54.12 84.613 ;
     RECT  35.88 83.653 37.392 84.899 ;
     RECT  72.912 83.795 74.112 83.891 ;
     RECT  79.176 83.795 80.7 84.083 ;
     RECT  72.912 83.891 75.3 84.037 ;
     RECT  2.712 84.035 2.856 85.477 ;
     RECT  21.612 84.037 22.848 84.085 ;
     RECT  72.912 84.037 74.304 85.043 ;
     RECT  21.816 84.085 22.848 85.523 ;
     RECT  24.408 84.325 25.728 84.901 ;
     RECT  46.2 84.325 47.328 85.523 ;
     RECT  27.012 84.805 28.272 84.947 ;
     RECT  28.296 84.805 29.4 84.947 ;
     RECT  22.92 85.475 24 89.653 ;
     RECT  16.44 85.523 17.616 85.907 ;
     RECT  21.612 85.523 22.848 89.699 ;
     RECT  37.812 85.523 39.312 87.013 ;
     RECT  46.2 85.523 47.376 85.955 ;
     RECT  67.512 85.765 68.736 86.675 ;
     RECT  45.912 85.955 47.376 88.117 ;
     RECT  43.212 86.389 44.448 86.771 ;
     RECT  44.472 86.435 45.6 86.771 ;
     RECT  68.76 86.579 69.9 86.675 ;
     RECT  69.12 86.675 69.9 87.829 ;
     RECT  43.212 86.771 45.6 87.397 ;
     RECT  72.24 86.867 72.6 87.733 ;
     RECT  37.944 87.013 39.312 87.875 ;
     RECT  57.672 87.205 59.1 88.931 ;
     RECT  72.912 87.253 73.968 88.115 ;
     RECT  40.872 87.299 41.856 88.547 ;
     RECT  43.752 87.397 45.6 87.923 ;
     RECT  27.012 87.541 28.128 88.931 ;
     RECT  28.152 87.541 29.4 88.885 ;
     RECT  9.384 87.587 10.5 88.931 ;
     RECT  70.212 87.733 71.28 88.643 ;
     RECT  71.304 87.733 72.6 88.643 ;
     RECT  32.52 87.781 33.648 87.827 ;
     RECT  33.672 87.781 34.8 88.643 ;
     RECT  32.412 87.827 33.648 88.643 ;
     RECT  37.812 87.875 39.312 89.461 ;
     RECT  61.2 87.875 61.8 88.309 ;
     RECT  45.072 87.923 45.6 88.021 ;
     RECT  46.008 88.117 47.376 89.459 ;
     RECT  69.12 88.259 69.9 89.317 ;
     RECT  59.412 88.309 60.48 88.979 ;
     RECT  60.504 88.309 61.8 88.979 ;
     RECT  8.112 88.403 9.36 88.885 ;
     RECT  70.212 88.643 70.584 89.845 ;
     RECT  72.48 88.643 72.6 88.885 ;
     RECT  83.712 88.789 84.816 89.555 ;
     RECT  84.84 88.789 86.1 89.555 ;
     RECT  8.112 88.885 9.12 91.187 ;
     RECT  9.144 88.931 10.5 91.187 ;
     RECT  27.012 88.931 28.464 90.565 ;
     RECT  58.992 88.931 59.1 88.933 ;
     RECT  35.64 88.979 35.88 89.941 ;
     RECT  59.412 88.979 61.8 90.085 ;
     RECT  68.28 89.317 69.9 89.701 ;
     RECT  45.912 89.459 47.376 90.469 ;
     RECT  38.184 89.461 39.312 89.891 ;
     RECT  83.712 89.555 83.832 90.517 ;
     RECT  21.612 89.699 22.896 90.037 ;
     RECT  37.812 89.891 39.312 91.045 ;
     RECT  18.912 90.037 20.4 91.571 ;
     RECT  21.768 90.037 22.896 90.707 ;
     RECT  5.412 90.083 6.864 91.093 ;
     RECT  59.412 90.085 60.432 90.611 ;
     RECT  60.456 90.085 61.8 90.611 ;
     RECT  13.656 90.181 15.072 91.331 ;
     RECT  50.16 90.275 51 90.613 ;
     RECT  72.912 90.517 74.16 90.803 ;
     RECT  27.012 90.565 28.08 91.765 ;
     RECT  35.112 90.611 36.528 92.869 ;
     RECT  48.612 90.613 49.968 92.099 ;
     RECT  49.992 90.613 51 92.099 ;
     RECT  70.212 90.659 70.488 91.717 ;
     RECT  21.612 90.707 22.896 94.115 ;
     RECT  28.104 90.755 29.4 94.115 ;
     RECT  2.712 90.899 2.856 92.245 ;
     RECT  64.812 90.947 64.92 92.245 ;
     RECT  68.568 90.947 69.9 93.013 ;
     RECT  37.944 91.045 39.312 92.915 ;
     RECT  5.412 91.093 6.816 92.821 ;
     RECT  89.112 91.141 90.288 94.259 ;
     RECT  90.312 91.141 91.5 94.259 ;
     RECT  52.248 91.717 53.7 92.197 ;
     RECT  27.012 91.765 28.032 92.387 ;
     RECT  72.48 91.859 72.6 93.349 ;
     RECT  50.352 92.099 51 92.293 ;
     RECT  52.44 92.197 53.7 92.963 ;
     RECT  65.736 92.245 67.2 93.205 ;
     RECT  27.012 92.387 28.08 94.115 ;
     RECT  13.104 92.435 13.2 93.493 ;
     RECT  5.544 92.821 6.816 93.635 ;
     RECT  35.112 92.869 36.48 93.059 ;
     RECT  37.812 92.915 39.312 94.691 ;
     RECT  68.376 93.299 69.9 94.595 ;
     RECT  70.488 93.349 71.52 94.595 ;
     RECT  71.544 93.349 72.6 94.549 ;
     RECT  59.412 93.397 60.432 94.595 ;
     RECT  60.456 93.397 61.8 94.595 ;
     RECT  45.024 93.491 45.6 94.645 ;
     RECT  5.412 93.635 6.816 94.691 ;
     RECT  66.96 93.779 67.2 95.125 ;
     RECT  18.912 94.021 19.968 94.403 ;
     RECT  19.992 94.021 21.3 94.403 ;
     RECT  22.92 94.067 24 94.115 ;
     RECT  62.424 94.501 63.696 94.597 ;
     RECT  70.488 94.595 71.76 94.597 ;
     RECT  70.68 94.597 71.76 94.883 ;
     RECT  63.384 94.643 64.5 95.747 ;
     RECT  62.112 94.691 63.36 95.747 ;
     RECT  62.112 95.747 64.5 96.901 ;
     RECT  66.96 95.795 67.2 96.901 ;
     RECT  78.312 95.891 78.84 96.901 ;
     RECT  34.32 95.939 34.8 96.901 ;
     RECT  5.976 96.901 7.152 97.141 ;
     RECT  9 96.901 10.176 97.141 ;
     RECT  13.512 96.901 15.024 97.141 ;
     RECT  16.824 96.901 18 97.429 ;
     RECT  19.848 96.901 21.024 97.141 ;
     RECT  22.872 96.901 24 97.141 ;
     RECT  24.312 96.901 25.824 97.141 ;
     RECT  28.296 96.901 29.4 97.141 ;
     RECT  30.696 96.901 32.1 97.141 ;
     RECT  33.096 96.901 34.8 97.141 ;
     RECT  35.112 96.901 36.096 97.209 ;
     RECT  36.12 96.901 37.296 97.141 ;
     RECT  39.144 96.901 40.2 97.141 ;
     RECT  40.512 96.901 41.52 97.141 ;
     RECT  45.912 96.901 46.944 97.429 ;
     RECT  46.968 96.901 48.144 97.141 ;
     RECT  49.944 96.901 51 97.141 ;
     RECT  52.392 96.901 53.568 97.141 ;
     RECT  60.216 96.901 61.392 97.141 ;
     RECT  63.24 96.901 64.5 97.141 ;
     RECT  64.812 96.901 66.192 97.141 ;
     RECT  66.216 96.901 67.2 97.141 ;
     RECT  68.664 96.901 69.9 97.333 ;
     RECT  73.464 96.901 74.64 97.141 ;
     RECT  76.488 96.901 77.664 98.581 ;
     RECT  79.464 96.901 80.7 97.141 ;
     RECT  83.712 96.901 84.864 97.141 ;
     RECT  87.336 96.901 88.512 97.429 ;
     RECT  89.112 96.901 90.288 97.429 ;
     RECT  90.312 96.901 91.5 97.141 ;
     RECT  13.8 97.141 15.024 98.581 ;
     RECT  24.648 97.141 25.824 98.053 ;
     RECT  30.696 97.141 31.872 97.429 ;
     RECT  33.72 97.141 34.8 97.223 ;
     RECT  44.568 97.141 45.6 97.223 ;
     RECT  65.016 97.141 66.192 97.429 ;
     RECT  34.92 97.209 36.096 98.581 ;
     RECT  33.72 97.223 34.896 98.581 ;
     RECT  44.568 97.223 45.744 98.629 ;
     RECT  68.664 97.333 69.84 97.429 ;
     RECT  11.4 97.429 12.576 98.053 ;
     RECT  54.792 98.053 55.968 98.581 ;
  END
END dsfd_m2l_vc_291x1__he_hwSW
END LIBRARY
